VERSION 5.8 ;
BUSBITCHARS "[]" ;
DIVIDERCHAR "/" ;
UNITS
    DATABASE MICRONS 1000 ;
END UNITS

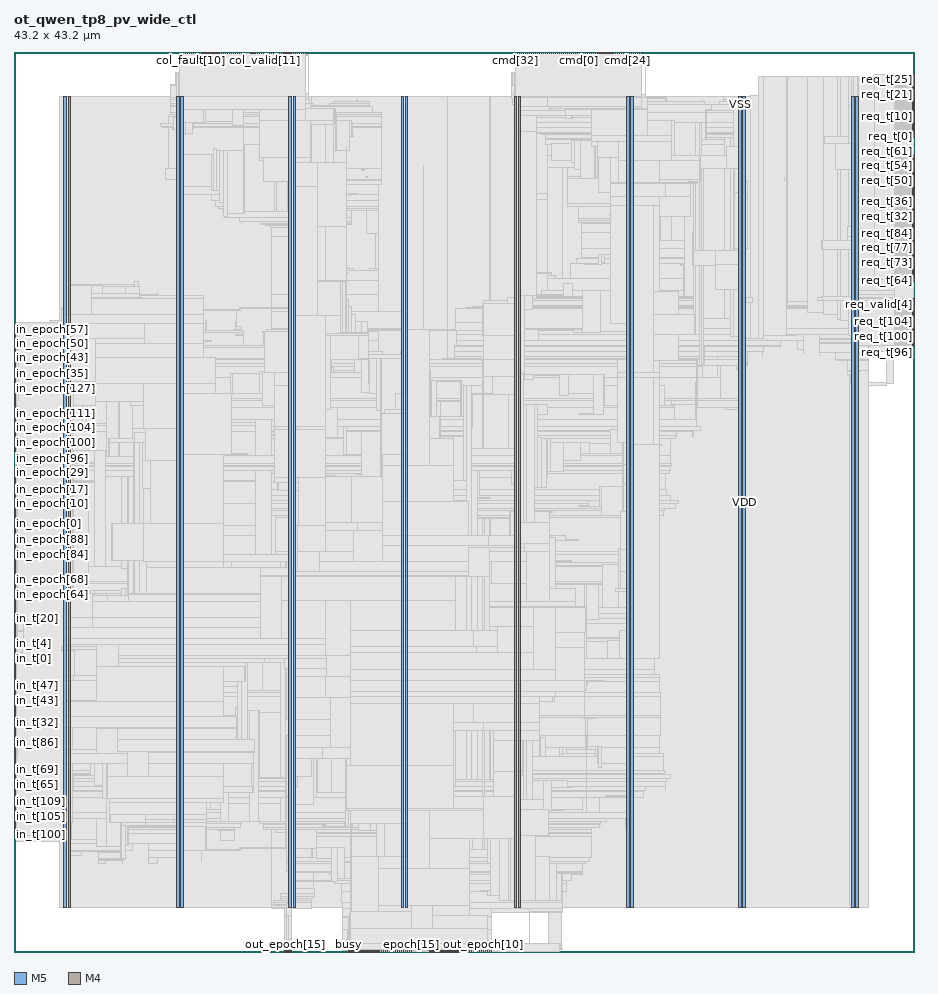
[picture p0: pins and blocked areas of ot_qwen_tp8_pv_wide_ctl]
MACRO ot_qwen_tp8_pv_wide_ctl
  FOREIGN ot_qwen_tp8_pv_wide_ctl 0 0 ;
  CLASS BLOCK ;
  SIZE 43.2 BY 43.2 ;
  PIN busy
    DIRECTION OUTPUT ;
    USE SIGNAL ;
    PORT
      LAYER M5 ;
        RECT  16.08 0 16.104 0.084 ;
    END
  END busy
  PIN clk
    DIRECTION INPUT ;
    USE SIGNAL ;
    PORT
      LAYER M5 ;
        RECT  16.176 0 16.2 0.084 ;
    END
  END clk
  PIN cmd[0]
    DIRECTION OUTPUT ;
    USE SIGNAL ;
    PORT
      LAYER M5 ;
        RECT  27.12 43.116 27.144 43.2 ;
    END
  END cmd[0]
  PIN cmd[10]
    DIRECTION OUTPUT ;
    USE SIGNAL ;
    PORT
      LAYER M5 ;
        RECT  28.08 43.116 28.104 43.2 ;
    END
  END cmd[10]
  PIN cmd[11]
    DIRECTION OUTPUT ;
    USE SIGNAL ;
    PORT
      LAYER M5 ;
        RECT  28.176 43.116 28.2 43.2 ;
    END
  END cmd[11]
  PIN cmd[12]
    DIRECTION OUTPUT ;
    USE SIGNAL ;
    PORT
      LAYER M5 ;
        RECT  28.272 43.116 28.296 43.2 ;
    END
  END cmd[12]
  PIN cmd[13]
    DIRECTION OUTPUT ;
    USE SIGNAL ;
    PORT
      LAYER M5 ;
        RECT  28.368 43.116 28.392 43.2 ;
    END
  END cmd[13]
  PIN cmd[14]
    DIRECTION OUTPUT ;
    USE SIGNAL ;
    PORT
      LAYER M5 ;
        RECT  28.464 43.116 28.488 43.2 ;
    END
  END cmd[14]
  PIN cmd[15]
    DIRECTION OUTPUT ;
    USE SIGNAL ;
    PORT
      LAYER M5 ;
        RECT  28.56 43.116 28.584 43.2 ;
    END
  END cmd[15]
  PIN cmd[16]
    DIRECTION OUTPUT ;
    USE SIGNAL ;
    PORT
      LAYER M5 ;
        RECT  28.656 43.116 28.68 43.2 ;
    END
  END cmd[16]
  PIN cmd[17]
    DIRECTION OUTPUT ;
    USE SIGNAL ;
    PORT
      LAYER M5 ;
        RECT  28.752 43.116 28.776 43.2 ;
    END
  END cmd[17]
  PIN cmd[18]
    DIRECTION OUTPUT ;
    USE SIGNAL ;
    PORT
      LAYER M5 ;
        RECT  28.848 43.116 28.872 43.2 ;
    END
  END cmd[18]
  PIN cmd[19]
    DIRECTION OUTPUT ;
    USE SIGNAL ;
    PORT
      LAYER M5 ;
        RECT  28.944 43.116 28.968 43.2 ;
    END
  END cmd[19]
  PIN cmd[1]
    DIRECTION OUTPUT ;
    USE SIGNAL ;
    PORT
      LAYER M5 ;
        RECT  27.216 43.116 27.24 43.2 ;
    END
  END cmd[1]
  PIN cmd[20]
    DIRECTION OUTPUT ;
    USE SIGNAL ;
    PORT
      LAYER M5 ;
        RECT  29.04 43.116 29.064 43.2 ;
    END
  END cmd[20]
  PIN cmd[21]
    DIRECTION OUTPUT ;
    USE SIGNAL ;
    PORT
      LAYER M5 ;
        RECT  29.136 43.116 29.16 43.2 ;
    END
  END cmd[21]
  PIN cmd[22]
    DIRECTION OUTPUT ;
    USE SIGNAL ;
    PORT
      LAYER M5 ;
        RECT  29.232 43.116 29.256 43.2 ;
    END
  END cmd[22]
  PIN cmd[23]
    DIRECTION OUTPUT ;
    USE SIGNAL ;
    PORT
      LAYER M5 ;
        RECT  29.328 43.116 29.352 43.2 ;
    END
  END cmd[23]
  PIN cmd[24]
    DIRECTION OUTPUT ;
    USE SIGNAL ;
    PORT
      LAYER M5 ;
        RECT  29.424 43.116 29.448 43.2 ;
    END
  END cmd[24]
  PIN cmd[25]
    DIRECTION OUTPUT ;
    USE SIGNAL ;
    PORT
      LAYER M5 ;
        RECT  29.52 43.116 29.544 43.2 ;
    END
  END cmd[25]
  PIN cmd[26]
    DIRECTION OUTPUT ;
    USE SIGNAL ;
    PORT
      LAYER M5 ;
        RECT  29.616 43.116 29.64 43.2 ;
    END
  END cmd[26]
  PIN cmd[27]
    DIRECTION OUTPUT ;
    USE SIGNAL ;
    PORT
      LAYER M5 ;
        RECT  29.712 43.116 29.736 43.2 ;
    END
  END cmd[27]
  PIN cmd[28]
    DIRECTION OUTPUT ;
    USE SIGNAL ;
    PORT
      LAYER M5 ;
        RECT  29.808 43.116 29.832 43.2 ;
    END
  END cmd[28]
  PIN cmd[29]
    DIRECTION OUTPUT ;
    USE SIGNAL ;
    PORT
      LAYER M5 ;
        RECT  29.904 43.116 29.928 43.2 ;
    END
  END cmd[29]
  PIN cmd[2]
    DIRECTION OUTPUT ;
    USE SIGNAL ;
    PORT
      LAYER M5 ;
        RECT  27.312 43.116 27.336 43.2 ;
    END
  END cmd[2]
  PIN cmd[30]
    DIRECTION OUTPUT ;
    USE SIGNAL ;
    PORT
      LAYER M5 ;
        RECT  30 43.116 30.024 43.2 ;
    END
  END cmd[30]
  PIN cmd[31]
    DIRECTION OUTPUT ;
    USE SIGNAL ;
    PORT
      LAYER M5 ;
        RECT  30.096 43.116 30.12 43.2 ;
    END
  END cmd[31]
  PIN cmd[32]
    DIRECTION OUTPUT ;
    USE SIGNAL ;
    PORT
      LAYER M5 ;
        RECT  24.048 43.116 24.072 43.2 ;
    END
  END cmd[32]
  PIN cmd[33]
    DIRECTION OUTPUT ;
    USE SIGNAL ;
    PORT
      LAYER M5 ;
        RECT  24.144 43.116 24.168 43.2 ;
    END
  END cmd[33]
  PIN cmd[34]
    DIRECTION OUTPUT ;
    USE SIGNAL ;
    PORT
      LAYER M5 ;
        RECT  24.24 43.116 24.264 43.2 ;
    END
  END cmd[34]
  PIN cmd[35]
    DIRECTION OUTPUT ;
    USE SIGNAL ;
    PORT
      LAYER M5 ;
        RECT  24.336 43.116 24.36 43.2 ;
    END
  END cmd[35]
  PIN cmd[36]
    DIRECTION OUTPUT ;
    USE SIGNAL ;
    PORT
      LAYER M5 ;
        RECT  24.432 43.116 24.456 43.2 ;
    END
  END cmd[36]
  PIN cmd[37]
    DIRECTION OUTPUT ;
    USE SIGNAL ;
    PORT
      LAYER M5 ;
        RECT  24.528 43.116 24.552 43.2 ;
    END
  END cmd[37]
  PIN cmd[38]
    DIRECTION OUTPUT ;
    USE SIGNAL ;
    PORT
      LAYER M5 ;
        RECT  24.624 43.116 24.648 43.2 ;
    END
  END cmd[38]
  PIN cmd[39]
    DIRECTION OUTPUT ;
    USE SIGNAL ;
    PORT
      LAYER M5 ;
        RECT  24.72 43.116 24.744 43.2 ;
    END
  END cmd[39]
  PIN cmd[3]
    DIRECTION OUTPUT ;
    USE SIGNAL ;
    PORT
      LAYER M5 ;
        RECT  27.408 43.116 27.432 43.2 ;
    END
  END cmd[3]
  PIN cmd[40]
    DIRECTION OUTPUT ;
    USE SIGNAL ;
    PORT
      LAYER M5 ;
        RECT  24.816 43.116 24.84 43.2 ;
    END
  END cmd[40]
  PIN cmd[41]
    DIRECTION OUTPUT ;
    USE SIGNAL ;
    PORT
      LAYER M5 ;
        RECT  24.912 43.116 24.936 43.2 ;
    END
  END cmd[41]
  PIN cmd[42]
    DIRECTION OUTPUT ;
    USE SIGNAL ;
    PORT
      LAYER M5 ;
        RECT  25.008 43.116 25.032 43.2 ;
    END
  END cmd[42]
  PIN cmd[43]
    DIRECTION OUTPUT ;
    USE SIGNAL ;
    PORT
      LAYER M5 ;
        RECT  25.104 43.116 25.128 43.2 ;
    END
  END cmd[43]
  PIN cmd[44]
    DIRECTION OUTPUT ;
    USE SIGNAL ;
    PORT
      LAYER M5 ;
        RECT  25.2 43.116 25.224 43.2 ;
    END
  END cmd[44]
  PIN cmd[45]
    DIRECTION OUTPUT ;
    USE SIGNAL ;
    PORT
      LAYER M5 ;
        RECT  25.296 43.116 25.32 43.2 ;
    END
  END cmd[45]
  PIN cmd[46]
    DIRECTION OUTPUT ;
    USE SIGNAL ;
    PORT
      LAYER M5 ;
        RECT  25.392 43.116 25.416 43.2 ;
    END
  END cmd[46]
  PIN cmd[47]
    DIRECTION OUTPUT ;
    USE SIGNAL ;
    PORT
      LAYER M5 ;
        RECT  25.488 43.116 25.512 43.2 ;
    END
  END cmd[47]
  PIN cmd[48]
    DIRECTION OUTPUT ;
    USE SIGNAL ;
    PORT
      LAYER M5 ;
        RECT  25.584 43.116 25.608 43.2 ;
    END
  END cmd[48]
  PIN cmd[49]
    DIRECTION OUTPUT ;
    USE SIGNAL ;
    PORT
      LAYER M5 ;
        RECT  25.68 43.116 25.704 43.2 ;
    END
  END cmd[49]
  PIN cmd[4]
    DIRECTION OUTPUT ;
    USE SIGNAL ;
    PORT
      LAYER M5 ;
        RECT  27.504 43.116 27.528 43.2 ;
    END
  END cmd[4]
  PIN cmd[50]
    DIRECTION OUTPUT ;
    USE SIGNAL ;
    PORT
      LAYER M5 ;
        RECT  25.776 43.116 25.8 43.2 ;
    END
  END cmd[50]
  PIN cmd[51]
    DIRECTION OUTPUT ;
    USE SIGNAL ;
    PORT
      LAYER M5 ;
        RECT  25.872 43.116 25.896 43.2 ;
    END
  END cmd[51]
  PIN cmd[52]
    DIRECTION OUTPUT ;
    USE SIGNAL ;
    PORT
      LAYER M5 ;
        RECT  25.968 43.116 25.992 43.2 ;
    END
  END cmd[52]
  PIN cmd[53]
    DIRECTION OUTPUT ;
    USE SIGNAL ;
    PORT
      LAYER M5 ;
        RECT  26.064 43.116 26.088 43.2 ;
    END
  END cmd[53]
  PIN cmd[54]
    DIRECTION OUTPUT ;
    USE SIGNAL ;
    PORT
      LAYER M5 ;
        RECT  26.16 43.116 26.184 43.2 ;
    END
  END cmd[54]
  PIN cmd[55]
    DIRECTION OUTPUT ;
    USE SIGNAL ;
    PORT
      LAYER M5 ;
        RECT  26.256 43.116 26.28 43.2 ;
    END
  END cmd[55]
  PIN cmd[56]
    DIRECTION OUTPUT ;
    USE SIGNAL ;
    PORT
      LAYER M5 ;
        RECT  26.352 43.116 26.376 43.2 ;
    END
  END cmd[56]
  PIN cmd[57]
    DIRECTION OUTPUT ;
    USE SIGNAL ;
    PORT
      LAYER M5 ;
        RECT  26.448 43.116 26.472 43.2 ;
    END
  END cmd[57]
  PIN cmd[58]
    DIRECTION OUTPUT ;
    USE SIGNAL ;
    PORT
      LAYER M5 ;
        RECT  26.544 43.116 26.568 43.2 ;
    END
  END cmd[58]
  PIN cmd[59]
    DIRECTION OUTPUT ;
    USE SIGNAL ;
    PORT
      LAYER M5 ;
        RECT  26.64 43.116 26.664 43.2 ;
    END
  END cmd[59]
  PIN cmd[5]
    DIRECTION OUTPUT ;
    USE SIGNAL ;
    PORT
      LAYER M5 ;
        RECT  27.6 43.116 27.624 43.2 ;
    END
  END cmd[5]
  PIN cmd[6]
    DIRECTION OUTPUT ;
    USE SIGNAL ;
    PORT
      LAYER M5 ;
        RECT  27.696 43.116 27.72 43.2 ;
    END
  END cmd[6]
  PIN cmd[7]
    DIRECTION OUTPUT ;
    USE SIGNAL ;
    PORT
      LAYER M5 ;
        RECT  27.792 43.116 27.816 43.2 ;
    END
  END cmd[7]
  PIN cmd[8]
    DIRECTION OUTPUT ;
    USE SIGNAL ;
    PORT
      LAYER M5 ;
        RECT  27.888 43.116 27.912 43.2 ;
    END
  END cmd[8]
  PIN cmd[9]
    DIRECTION OUTPUT ;
    USE SIGNAL ;
    PORT
      LAYER M5 ;
        RECT  27.984 43.116 28.008 43.2 ;
    END
  END cmd[9]
  PIN col_fault[0]
    DIRECTION INPUT ;
    USE SIGNAL ;
    PORT
      LAYER M5 ;
        RECT  26.736 43.116 26.76 43.2 ;
    END
  END col_fault[0]
  PIN col_fault[10]
    DIRECTION INPUT ;
    USE SIGNAL ;
    PORT
      LAYER M5 ;
        RECT  8.496 43.116 8.52 43.2 ;
    END
  END col_fault[10]
  PIN col_fault[11]
    DIRECTION INPUT ;
    USE SIGNAL ;
    PORT
      LAYER M5 ;
        RECT  8.592 43.116 8.616 43.2 ;
    END
  END col_fault[11]
  PIN col_fault[12]
    DIRECTION INPUT ;
    USE SIGNAL ;
    PORT
      LAYER M5 ;
        RECT  8.688 43.116 8.712 43.2 ;
    END
  END col_fault[12]
  PIN col_fault[13]
    DIRECTION INPUT ;
    USE SIGNAL ;
    PORT
      LAYER M5 ;
        RECT  8.784 43.116 8.808 43.2 ;
    END
  END col_fault[13]
  PIN col_fault[14]
    DIRECTION INPUT ;
    USE SIGNAL ;
    PORT
      LAYER M5 ;
        RECT  8.88 43.116 8.904 43.2 ;
    END
  END col_fault[14]
  PIN col_fault[15]
    DIRECTION INPUT ;
    USE SIGNAL ;
    PORT
      LAYER M5 ;
        RECT  8.976 43.116 9 43.2 ;
    END
  END col_fault[15]
  PIN col_fault[16]
    DIRECTION INPUT ;
    USE SIGNAL ;
    PORT
      LAYER M5 ;
        RECT  9.072 43.116 9.096 43.2 ;
    END
  END col_fault[16]
  PIN col_fault[17]
    DIRECTION INPUT ;
    USE SIGNAL ;
    PORT
      LAYER M5 ;
        RECT  9.168 43.116 9.192 43.2 ;
    END
  END col_fault[17]
  PIN col_fault[18]
    DIRECTION INPUT ;
    USE SIGNAL ;
    PORT
      LAYER M5 ;
        RECT  9.264 43.116 9.288 43.2 ;
    END
  END col_fault[18]
  PIN col_fault[19]
    DIRECTION INPUT ;
    USE SIGNAL ;
    PORT
      LAYER M5 ;
        RECT  9.36 43.116 9.384 43.2 ;
    END
  END col_fault[19]
  PIN col_fault[1]
    DIRECTION INPUT ;
    USE SIGNAL ;
    PORT
      LAYER M5 ;
        RECT  26.832 43.116 26.856 43.2 ;
    END
  END col_fault[1]
  PIN col_fault[20]
    DIRECTION INPUT ;
    USE SIGNAL ;
    PORT
      LAYER M5 ;
        RECT  9.456 43.116 9.48 43.2 ;
    END
  END col_fault[20]
  PIN col_fault[21]
    DIRECTION INPUT ;
    USE SIGNAL ;
    PORT
      LAYER M5 ;
        RECT  9.552 43.116 9.576 43.2 ;
    END
  END col_fault[21]
  PIN col_fault[22]
    DIRECTION INPUT ;
    USE SIGNAL ;
    PORT
      LAYER M5 ;
        RECT  9.648 43.116 9.672 43.2 ;
    END
  END col_fault[22]
  PIN col_fault[23]
    DIRECTION INPUT ;
    USE SIGNAL ;
    PORT
      LAYER M5 ;
        RECT  9.744 43.116 9.768 43.2 ;
    END
  END col_fault[23]
  PIN col_fault[24]
    DIRECTION INPUT ;
    USE SIGNAL ;
    PORT
      LAYER M5 ;
        RECT  9.84 43.116 9.864 43.2 ;
    END
  END col_fault[24]
  PIN col_fault[25]
    DIRECTION INPUT ;
    USE SIGNAL ;
    PORT
      LAYER M5 ;
        RECT  9.936 43.116 9.96 43.2 ;
    END
  END col_fault[25]
  PIN col_fault[26]
    DIRECTION INPUT ;
    USE SIGNAL ;
    PORT
      LAYER M5 ;
        RECT  10.032 43.116 10.056 43.2 ;
    END
  END col_fault[26]
  PIN col_fault[27]
    DIRECTION INPUT ;
    USE SIGNAL ;
    PORT
      LAYER M5 ;
        RECT  10.128 43.116 10.152 43.2 ;
    END
  END col_fault[27]
  PIN col_fault[28]
    DIRECTION INPUT ;
    USE SIGNAL ;
    PORT
      LAYER M5 ;
        RECT  10.224 43.116 10.248 43.2 ;
    END
  END col_fault[28]
  PIN col_fault[29]
    DIRECTION INPUT ;
    USE SIGNAL ;
    PORT
      LAYER M5 ;
        RECT  10.32 43.116 10.344 43.2 ;
    END
  END col_fault[29]
  PIN col_fault[2]
    DIRECTION INPUT ;
    USE SIGNAL ;
    PORT
      LAYER M5 ;
        RECT  26.928 43.116 26.952 43.2 ;
    END
  END col_fault[2]
  PIN col_fault[30]
    DIRECTION INPUT ;
    USE SIGNAL ;
    PORT
      LAYER M5 ;
        RECT  10.416 43.116 10.44 43.2 ;
    END
  END col_fault[30]
  PIN col_fault[31]
    DIRECTION INPUT ;
    USE SIGNAL ;
    PORT
      LAYER M5 ;
        RECT  10.512 43.116 10.536 43.2 ;
    END
  END col_fault[31]
  PIN col_fault[3]
    DIRECTION INPUT ;
    USE SIGNAL ;
    PORT
      LAYER M5 ;
        RECT  27.024 43.116 27.048 43.2 ;
    END
  END col_fault[3]
  PIN col_fault[4]
    DIRECTION INPUT ;
    USE SIGNAL ;
    PORT
      LAYER M5 ;
        RECT  7.92 43.116 7.944 43.2 ;
    END
  END col_fault[4]
  PIN col_fault[5]
    DIRECTION INPUT ;
    USE SIGNAL ;
    PORT
      LAYER M5 ;
        RECT  8.016 43.116 8.04 43.2 ;
    END
  END col_fault[5]
  PIN col_fault[6]
    DIRECTION INPUT ;
    USE SIGNAL ;
    PORT
      LAYER M5 ;
        RECT  8.112 43.116 8.136 43.2 ;
    END
  END col_fault[6]
  PIN col_fault[7]
    DIRECTION INPUT ;
    USE SIGNAL ;
    PORT
      LAYER M5 ;
        RECT  8.208 43.116 8.232 43.2 ;
    END
  END col_fault[7]
  PIN col_fault[8]
    DIRECTION INPUT ;
    USE SIGNAL ;
    PORT
      LAYER M5 ;
        RECT  8.304 43.116 8.328 43.2 ;
    END
  END col_fault[8]
  PIN col_fault[9]
    DIRECTION INPUT ;
    USE SIGNAL ;
    PORT
      LAYER M5 ;
        RECT  8.4 43.116 8.424 43.2 ;
    END
  END col_fault[9]
  PIN col_valid[0]
    DIRECTION INPUT ;
    USE SIGNAL ;
    PORT
      LAYER M5 ;
        RECT  10.608 43.116 10.632 43.2 ;
    END
  END col_valid[0]
  PIN col_valid[10]
    DIRECTION INPUT ;
    USE SIGNAL ;
    PORT
      LAYER M5 ;
        RECT  11.952 43.116 11.976 43.2 ;
    END
  END col_valid[10]
  PIN col_valid[11]
    DIRECTION INPUT ;
    USE SIGNAL ;
    PORT
      LAYER M5 ;
        RECT  12.048 43.116 12.072 43.2 ;
    END
  END col_valid[11]
  PIN col_valid[12]
    DIRECTION INPUT ;
    USE SIGNAL ;
    PORT
      LAYER M5 ;
        RECT  12.144 43.116 12.168 43.2 ;
    END
  END col_valid[12]
  PIN col_valid[13]
    DIRECTION INPUT ;
    USE SIGNAL ;
    PORT
      LAYER M5 ;
        RECT  12.24 43.116 12.264 43.2 ;
    END
  END col_valid[13]
  PIN col_valid[14]
    DIRECTION INPUT ;
    USE SIGNAL ;
    PORT
      LAYER M5 ;
        RECT  12.336 43.116 12.36 43.2 ;
    END
  END col_valid[14]
  PIN col_valid[15]
    DIRECTION INPUT ;
    USE SIGNAL ;
    PORT
      LAYER M5 ;
        RECT  12.432 43.116 12.456 43.2 ;
    END
  END col_valid[15]
  PIN col_valid[16]
    DIRECTION INPUT ;
    USE SIGNAL ;
    PORT
      LAYER M5 ;
        RECT  12.528 43.116 12.552 43.2 ;
    END
  END col_valid[16]
  PIN col_valid[17]
    DIRECTION INPUT ;
    USE SIGNAL ;
    PORT
      LAYER M5 ;
        RECT  12.624 43.116 12.648 43.2 ;
    END
  END col_valid[17]
  PIN col_valid[18]
    DIRECTION INPUT ;
    USE SIGNAL ;
    PORT
      LAYER M5 ;
        RECT  12.72 43.116 12.744 43.2 ;
    END
  END col_valid[18]
  PIN col_valid[19]
    DIRECTION INPUT ;
    USE SIGNAL ;
    PORT
      LAYER M5 ;
        RECT  12.816 43.116 12.84 43.2 ;
    END
  END col_valid[19]
  PIN col_valid[1]
    DIRECTION INPUT ;
    USE SIGNAL ;
    PORT
      LAYER M5 ;
        RECT  10.704 43.116 10.728 43.2 ;
    END
  END col_valid[1]
  PIN col_valid[20]
    DIRECTION INPUT ;
    USE SIGNAL ;
    PORT
      LAYER M5 ;
        RECT  12.912 43.116 12.936 43.2 ;
    END
  END col_valid[20]
  PIN col_valid[21]
    DIRECTION INPUT ;
    USE SIGNAL ;
    PORT
      LAYER M5 ;
        RECT  13.008 43.116 13.032 43.2 ;
    END
  END col_valid[21]
  PIN col_valid[22]
    DIRECTION INPUT ;
    USE SIGNAL ;
    PORT
      LAYER M5 ;
        RECT  13.104 43.116 13.128 43.2 ;
    END
  END col_valid[22]
  PIN col_valid[23]
    DIRECTION INPUT ;
    USE SIGNAL ;
    PORT
      LAYER M5 ;
        RECT  13.2 43.116 13.224 43.2 ;
    END
  END col_valid[23]
  PIN col_valid[24]
    DIRECTION INPUT ;
    USE SIGNAL ;
    PORT
      LAYER M5 ;
        RECT  13.296 43.116 13.32 43.2 ;
    END
  END col_valid[24]
  PIN col_valid[25]
    DIRECTION INPUT ;
    USE SIGNAL ;
    PORT
      LAYER M5 ;
        RECT  13.392 43.116 13.416 43.2 ;
    END
  END col_valid[25]
  PIN col_valid[26]
    DIRECTION INPUT ;
    USE SIGNAL ;
    PORT
      LAYER M5 ;
        RECT  13.488 43.116 13.512 43.2 ;
    END
  END col_valid[26]
  PIN col_valid[27]
    DIRECTION INPUT ;
    USE SIGNAL ;
    PORT
      LAYER M5 ;
        RECT  13.584 43.116 13.608 43.2 ;
    END
  END col_valid[27]
  PIN col_valid[28]
    DIRECTION INPUT ;
    USE SIGNAL ;
    PORT
      LAYER M5 ;
        RECT  13.68 43.116 13.704 43.2 ;
    END
  END col_valid[28]
  PIN col_valid[29]
    DIRECTION INPUT ;
    USE SIGNAL ;
    PORT
      LAYER M5 ;
        RECT  13.776 43.116 13.8 43.2 ;
    END
  END col_valid[29]
  PIN col_valid[2]
    DIRECTION INPUT ;
    USE SIGNAL ;
    PORT
      LAYER M5 ;
        RECT  10.8 43.116 10.824 43.2 ;
    END
  END col_valid[2]
  PIN col_valid[30]
    DIRECTION INPUT ;
    USE SIGNAL ;
    PORT
      LAYER M5 ;
        RECT  13.872 43.116 13.896 43.2 ;
    END
  END col_valid[30]
  PIN col_valid[31]
    DIRECTION INPUT ;
    USE SIGNAL ;
    PORT
      LAYER M5 ;
        RECT  13.968 43.116 13.992 43.2 ;
    END
  END col_valid[31]
  PIN col_valid[3]
    DIRECTION INPUT ;
    USE SIGNAL ;
    PORT
      LAYER M5 ;
        RECT  10.896 43.116 10.92 43.2 ;
    END
  END col_valid[3]
  PIN col_valid[4]
    DIRECTION INPUT ;
    USE SIGNAL ;
    PORT
      LAYER M5 ;
        RECT  11.376 43.116 11.4 43.2 ;
    END
  END col_valid[4]
  PIN col_valid[5]
    DIRECTION INPUT ;
    USE SIGNAL ;
    PORT
      LAYER M5 ;
        RECT  11.472 43.116 11.496 43.2 ;
    END
  END col_valid[5]
  PIN col_valid[6]
    DIRECTION INPUT ;
    USE SIGNAL ;
    PORT
      LAYER M5 ;
        RECT  11.568 43.116 11.592 43.2 ;
    END
  END col_valid[6]
  PIN col_valid[7]
    DIRECTION INPUT ;
    USE SIGNAL ;
    PORT
      LAYER M5 ;
        RECT  11.664 43.116 11.688 43.2 ;
    END
  END col_valid[7]
  PIN col_valid[8]
    DIRECTION INPUT ;
    USE SIGNAL ;
    PORT
      LAYER M5 ;
        RECT  11.76 43.116 11.784 43.2 ;
    END
  END col_valid[8]
  PIN col_valid[9]
    DIRECTION INPUT ;
    USE SIGNAL ;
    PORT
      LAYER M5 ;
        RECT  11.856 43.116 11.88 43.2 ;
    END
  END col_valid[9]
  PIN context_len[0]
    DIRECTION INPUT ;
    USE SIGNAL ;
    PORT
      LAYER M5 ;
        RECT  16.272 0 16.296 0.084 ;
    END
  END context_len[0]
  PIN context_len[10]
    DIRECTION INPUT ;
    USE SIGNAL ;
    PORT
      LAYER M5 ;
        RECT  17.232 0 17.256 0.084 ;
    END
  END context_len[10]
  PIN context_len[11]
    DIRECTION INPUT ;
    USE SIGNAL ;
    PORT
      LAYER M5 ;
        RECT  17.328 0 17.352 0.084 ;
    END
  END context_len[11]
  PIN context_len[12]
    DIRECTION INPUT ;
    USE SIGNAL ;
    PORT
      LAYER M5 ;
        RECT  17.424 0 17.448 0.084 ;
    END
  END context_len[12]
  PIN context_len[13]
    DIRECTION INPUT ;
    USE SIGNAL ;
    PORT
      LAYER M5 ;
        RECT  17.52 0 17.544 0.084 ;
    END
  END context_len[13]
  PIN context_len[1]
    DIRECTION INPUT ;
    USE SIGNAL ;
    PORT
      LAYER M5 ;
        RECT  16.368 0 16.392 0.084 ;
    END
  END context_len[1]
  PIN context_len[2]
    DIRECTION INPUT ;
    USE SIGNAL ;
    PORT
      LAYER M5 ;
        RECT  16.464 0 16.488 0.084 ;
    END
  END context_len[2]
  PIN context_len[3]
    DIRECTION INPUT ;
    USE SIGNAL ;
    PORT
      LAYER M5 ;
        RECT  16.56 0 16.584 0.084 ;
    END
  END context_len[3]
  PIN context_len[4]
    DIRECTION INPUT ;
    USE SIGNAL ;
    PORT
      LAYER M5 ;
        RECT  16.656 0 16.68 0.084 ;
    END
  END context_len[4]
  PIN context_len[5]
    DIRECTION INPUT ;
    USE SIGNAL ;
    PORT
      LAYER M5 ;
        RECT  16.752 0 16.776 0.084 ;
    END
  END context_len[5]
  PIN context_len[6]
    DIRECTION INPUT ;
    USE SIGNAL ;
    PORT
      LAYER M5 ;
        RECT  16.848 0 16.872 0.084 ;
    END
  END context_len[6]
  PIN context_len[7]
    DIRECTION INPUT ;
    USE SIGNAL ;
    PORT
      LAYER M5 ;
        RECT  16.944 0 16.968 0.084 ;
    END
  END context_len[7]
  PIN context_len[8]
    DIRECTION INPUT ;
    USE SIGNAL ;
    PORT
      LAYER M5 ;
        RECT  17.04 0 17.064 0.084 ;
    END
  END context_len[8]
  PIN context_len[9]
    DIRECTION INPUT ;
    USE SIGNAL ;
    PORT
      LAYER M5 ;
        RECT  17.136 0 17.16 0.084 ;
    END
  END context_len[9]
  PIN epoch[0]
    DIRECTION INPUT ;
    USE SIGNAL ;
    PORT
      LAYER M5 ;
        RECT  17.616 0 17.64 0.084 ;
    END
  END epoch[0]
  PIN epoch[10]
    DIRECTION INPUT ;
    USE SIGNAL ;
    PORT
      LAYER M5 ;
        RECT  18.576 0 18.6 0.084 ;
    END
  END epoch[10]
  PIN epoch[11]
    DIRECTION INPUT ;
    USE SIGNAL ;
    PORT
      LAYER M5 ;
        RECT  18.672 0 18.696 0.084 ;
    END
  END epoch[11]
  PIN epoch[12]
    DIRECTION INPUT ;
    USE SIGNAL ;
    PORT
      LAYER M5 ;
        RECT  18.768 0 18.792 0.084 ;
    END
  END epoch[12]
  PIN epoch[13]
    DIRECTION INPUT ;
    USE SIGNAL ;
    PORT
      LAYER M5 ;
        RECT  18.864 0 18.888 0.084 ;
    END
  END epoch[13]
  PIN epoch[14]
    DIRECTION INPUT ;
    USE SIGNAL ;
    PORT
      LAYER M5 ;
        RECT  18.96 0 18.984 0.084 ;
    END
  END epoch[14]
  PIN epoch[15]
    DIRECTION INPUT ;
    USE SIGNAL ;
    PORT
      LAYER M5 ;
        RECT  19.056 0 19.08 0.084 ;
    END
  END epoch[15]
  PIN epoch[1]
    DIRECTION INPUT ;
    USE SIGNAL ;
    PORT
      LAYER M5 ;
        RECT  17.712 0 17.736 0.084 ;
    END
  END epoch[1]
  PIN epoch[2]
    DIRECTION INPUT ;
    USE SIGNAL ;
    PORT
      LAYER M5 ;
        RECT  17.808 0 17.832 0.084 ;
    END
  END epoch[2]
  PIN epoch[3]
    DIRECTION INPUT ;
    USE SIGNAL ;
    PORT
      LAYER M5 ;
        RECT  17.904 0 17.928 0.084 ;
    END
  END epoch[3]
  PIN epoch[4]
    DIRECTION INPUT ;
    USE SIGNAL ;
    PORT
      LAYER M5 ;
        RECT  18 0 18.024 0.084 ;
    END
  END epoch[4]
  PIN epoch[5]
    DIRECTION INPUT ;
    USE SIGNAL ;
    PORT
      LAYER M5 ;
        RECT  18.096 0 18.12 0.084 ;
    END
  END epoch[5]
  PIN epoch[6]
    DIRECTION INPUT ;
    USE SIGNAL ;
    PORT
      LAYER M5 ;
        RECT  18.192 0 18.216 0.084 ;
    END
  END epoch[6]
  PIN epoch[7]
    DIRECTION INPUT ;
    USE SIGNAL ;
    PORT
      LAYER M5 ;
        RECT  18.288 0 18.312 0.084 ;
    END
  END epoch[7]
  PIN epoch[8]
    DIRECTION INPUT ;
    USE SIGNAL ;
    PORT
      LAYER M5 ;
        RECT  18.384 0 18.408 0.084 ;
    END
  END epoch[8]
  PIN epoch[9]
    DIRECTION INPUT ;
    USE SIGNAL ;
    PORT
      LAYER M5 ;
        RECT  18.48 0 18.504 0.084 ;
    END
  END epoch[9]
  PIN fault
    DIRECTION OUTPUT ;
    USE SIGNAL ;
    PORT
      LAYER M5 ;
        RECT  19.92 0 19.944 0.084 ;
    END
  END fault
  PIN in_epoch[0]
    DIRECTION INPUT ;
    USE SIGNAL ;
    PORT
      LAYER M4 ;
        RECT  0 20.208 0.084 20.232 ;
    END
  END in_epoch[0]
  PIN in_epoch[100]
    DIRECTION INPUT ;
    USE SIGNAL ;
    PORT
      LAYER M4 ;
        RECT  0 24.432 0.084 24.456 ;
    END
  END in_epoch[100]
  PIN in_epoch[101]
    DIRECTION INPUT ;
    USE SIGNAL ;
    PORT
      LAYER M4 ;
        RECT  0 24.528 0.084 24.552 ;
    END
  END in_epoch[101]
  PIN in_epoch[102]
    DIRECTION INPUT ;
    USE SIGNAL ;
    PORT
      LAYER M4 ;
        RECT  0 24.624 0.084 24.648 ;
    END
  END in_epoch[102]
  PIN in_epoch[103]
    DIRECTION INPUT ;
    USE SIGNAL ;
    PORT
      LAYER M4 ;
        RECT  0 24.72 0.084 24.744 ;
    END
  END in_epoch[103]
  PIN in_epoch[104]
    DIRECTION INPUT ;
    USE SIGNAL ;
    PORT
      LAYER M4 ;
        RECT  0 24.816 0.084 24.84 ;
    END
  END in_epoch[104]
  PIN in_epoch[105]
    DIRECTION INPUT ;
    USE SIGNAL ;
    PORT
      LAYER M4 ;
        RECT  0 24.912 0.084 24.936 ;
    END
  END in_epoch[105]
  PIN in_epoch[106]
    DIRECTION INPUT ;
    USE SIGNAL ;
    PORT
      LAYER M4 ;
        RECT  0 25.008 0.084 25.032 ;
    END
  END in_epoch[106]
  PIN in_epoch[107]
    DIRECTION INPUT ;
    USE SIGNAL ;
    PORT
      LAYER M4 ;
        RECT  0 25.104 0.084 25.128 ;
    END
  END in_epoch[107]
  PIN in_epoch[108]
    DIRECTION INPUT ;
    USE SIGNAL ;
    PORT
      LAYER M4 ;
        RECT  0 25.2 0.084 25.224 ;
    END
  END in_epoch[108]
  PIN in_epoch[109]
    DIRECTION INPUT ;
    USE SIGNAL ;
    PORT
      LAYER M4 ;
        RECT  0 25.296 0.084 25.32 ;
    END
  END in_epoch[109]
  PIN in_epoch[10]
    DIRECTION INPUT ;
    USE SIGNAL ;
    PORT
      LAYER M4 ;
        RECT  0 21.168 0.084 21.192 ;
    END
  END in_epoch[10]
  PIN in_epoch[110]
    DIRECTION INPUT ;
    USE SIGNAL ;
    PORT
      LAYER M4 ;
        RECT  0 25.392 0.084 25.416 ;
    END
  END in_epoch[110]
  PIN in_epoch[111]
    DIRECTION INPUT ;
    USE SIGNAL ;
    PORT
      LAYER M4 ;
        RECT  0 25.488 0.084 25.512 ;
    END
  END in_epoch[111]
  PIN in_epoch[112]
    DIRECTION INPUT ;
    USE SIGNAL ;
    PORT
      LAYER M4 ;
        RECT  0 25.584 0.084 25.608 ;
    END
  END in_epoch[112]
  PIN in_epoch[113]
    DIRECTION INPUT ;
    USE SIGNAL ;
    PORT
      LAYER M4 ;
        RECT  0 25.68 0.084 25.704 ;
    END
  END in_epoch[113]
  PIN in_epoch[114]
    DIRECTION INPUT ;
    USE SIGNAL ;
    PORT
      LAYER M4 ;
        RECT  0 25.776 0.084 25.8 ;
    END
  END in_epoch[114]
  PIN in_epoch[115]
    DIRECTION INPUT ;
    USE SIGNAL ;
    PORT
      LAYER M4 ;
        RECT  0 25.872 0.084 25.896 ;
    END
  END in_epoch[115]
  PIN in_epoch[116]
    DIRECTION INPUT ;
    USE SIGNAL ;
    PORT
      LAYER M4 ;
        RECT  0 25.968 0.084 25.992 ;
    END
  END in_epoch[116]
  PIN in_epoch[117]
    DIRECTION INPUT ;
    USE SIGNAL ;
    PORT
      LAYER M4 ;
        RECT  0 26.064 0.084 26.088 ;
    END
  END in_epoch[117]
  PIN in_epoch[118]
    DIRECTION INPUT ;
    USE SIGNAL ;
    PORT
      LAYER M4 ;
        RECT  0 26.16 0.084 26.184 ;
    END
  END in_epoch[118]
  PIN in_epoch[119]
    DIRECTION INPUT ;
    USE SIGNAL ;
    PORT
      LAYER M4 ;
        RECT  0 26.256 0.084 26.28 ;
    END
  END in_epoch[119]
  PIN in_epoch[11]
    DIRECTION INPUT ;
    USE SIGNAL ;
    PORT
      LAYER M4 ;
        RECT  0 21.264 0.084 21.288 ;
    END
  END in_epoch[11]
  PIN in_epoch[120]
    DIRECTION INPUT ;
    USE SIGNAL ;
    PORT
      LAYER M4 ;
        RECT  0 26.352 0.084 26.376 ;
    END
  END in_epoch[120]
  PIN in_epoch[121]
    DIRECTION INPUT ;
    USE SIGNAL ;
    PORT
      LAYER M4 ;
        RECT  0 26.448 0.084 26.472 ;
    END
  END in_epoch[121]
  PIN in_epoch[122]
    DIRECTION INPUT ;
    USE SIGNAL ;
    PORT
      LAYER M4 ;
        RECT  0 26.544 0.084 26.568 ;
    END
  END in_epoch[122]
  PIN in_epoch[123]
    DIRECTION INPUT ;
    USE SIGNAL ;
    PORT
      LAYER M4 ;
        RECT  0 26.64 0.084 26.664 ;
    END
  END in_epoch[123]
  PIN in_epoch[124]
    DIRECTION INPUT ;
    USE SIGNAL ;
    PORT
      LAYER M4 ;
        RECT  0 26.736 0.084 26.76 ;
    END
  END in_epoch[124]
  PIN in_epoch[125]
    DIRECTION INPUT ;
    USE SIGNAL ;
    PORT
      LAYER M4 ;
        RECT  0 26.832 0.084 26.856 ;
    END
  END in_epoch[125]
  PIN in_epoch[126]
    DIRECTION INPUT ;
    USE SIGNAL ;
    PORT
      LAYER M4 ;
        RECT  0 26.928 0.084 26.952 ;
    END
  END in_epoch[126]
  PIN in_epoch[127]
    DIRECTION INPUT ;
    USE SIGNAL ;
    PORT
      LAYER M4 ;
        RECT  0 27.024 0.084 27.048 ;
    END
  END in_epoch[127]
  PIN in_epoch[12]
    DIRECTION INPUT ;
    USE SIGNAL ;
    PORT
      LAYER M4 ;
        RECT  0 21.36 0.084 21.384 ;
    END
  END in_epoch[12]
  PIN in_epoch[13]
    DIRECTION INPUT ;
    USE SIGNAL ;
    PORT
      LAYER M4 ;
        RECT  0 21.456 0.084 21.48 ;
    END
  END in_epoch[13]
  PIN in_epoch[14]
    DIRECTION INPUT ;
    USE SIGNAL ;
    PORT
      LAYER M4 ;
        RECT  0 21.552 0.084 21.576 ;
    END
  END in_epoch[14]
  PIN in_epoch[15]
    DIRECTION INPUT ;
    USE SIGNAL ;
    PORT
      LAYER M4 ;
        RECT  0 21.648 0.084 21.672 ;
    END
  END in_epoch[15]
  PIN in_epoch[16]
    DIRECTION INPUT ;
    USE SIGNAL ;
    PORT
      LAYER M4 ;
        RECT  0 21.744 0.084 21.768 ;
    END
  END in_epoch[16]
  PIN in_epoch[17]
    DIRECTION INPUT ;
    USE SIGNAL ;
    PORT
      LAYER M4 ;
        RECT  0 21.84 0.084 21.864 ;
    END
  END in_epoch[17]
  PIN in_epoch[18]
    DIRECTION INPUT ;
    USE SIGNAL ;
    PORT
      LAYER M4 ;
        RECT  0 21.936 0.084 21.96 ;
    END
  END in_epoch[18]
  PIN in_epoch[19]
    DIRECTION INPUT ;
    USE SIGNAL ;
    PORT
      LAYER M4 ;
        RECT  0 22.032 0.084 22.056 ;
    END
  END in_epoch[19]
  PIN in_epoch[1]
    DIRECTION INPUT ;
    USE SIGNAL ;
    PORT
      LAYER M4 ;
        RECT  0 20.304 0.084 20.328 ;
    END
  END in_epoch[1]
  PIN in_epoch[20]
    DIRECTION INPUT ;
    USE SIGNAL ;
    PORT
      LAYER M4 ;
        RECT  0 22.128 0.084 22.152 ;
    END
  END in_epoch[20]
  PIN in_epoch[21]
    DIRECTION INPUT ;
    USE SIGNAL ;
    PORT
      LAYER M4 ;
        RECT  0 22.224 0.084 22.248 ;
    END
  END in_epoch[21]
  PIN in_epoch[22]
    DIRECTION INPUT ;
    USE SIGNAL ;
    PORT
      LAYER M4 ;
        RECT  0 22.32 0.084 22.344 ;
    END
  END in_epoch[22]
  PIN in_epoch[23]
    DIRECTION INPUT ;
    USE SIGNAL ;
    PORT
      LAYER M4 ;
        RECT  0 22.416 0.084 22.44 ;
    END
  END in_epoch[23]
  PIN in_epoch[24]
    DIRECTION INPUT ;
    USE SIGNAL ;
    PORT
      LAYER M4 ;
        RECT  0 22.512 0.084 22.536 ;
    END
  END in_epoch[24]
  PIN in_epoch[25]
    DIRECTION INPUT ;
    USE SIGNAL ;
    PORT
      LAYER M4 ;
        RECT  0 22.608 0.084 22.632 ;
    END
  END in_epoch[25]
  PIN in_epoch[26]
    DIRECTION INPUT ;
    USE SIGNAL ;
    PORT
      LAYER M4 ;
        RECT  0 22.704 0.084 22.728 ;
    END
  END in_epoch[26]
  PIN in_epoch[27]
    DIRECTION INPUT ;
    USE SIGNAL ;
    PORT
      LAYER M4 ;
        RECT  0 22.8 0.084 22.824 ;
    END
  END in_epoch[27]
  PIN in_epoch[28]
    DIRECTION INPUT ;
    USE SIGNAL ;
    PORT
      LAYER M4 ;
        RECT  0 22.896 0.084 22.92 ;
    END
  END in_epoch[28]
  PIN in_epoch[29]
    DIRECTION INPUT ;
    USE SIGNAL ;
    PORT
      LAYER M4 ;
        RECT  0 22.992 0.084 23.016 ;
    END
  END in_epoch[29]
  PIN in_epoch[2]
    DIRECTION INPUT ;
    USE SIGNAL ;
    PORT
      LAYER M4 ;
        RECT  0 20.4 0.084 20.424 ;
    END
  END in_epoch[2]
  PIN in_epoch[30]
    DIRECTION INPUT ;
    USE SIGNAL ;
    PORT
      LAYER M4 ;
        RECT  0 23.088 0.084 23.112 ;
    END
  END in_epoch[30]
  PIN in_epoch[31]
    DIRECTION INPUT ;
    USE SIGNAL ;
    PORT
      LAYER M4 ;
        RECT  0 23.184 0.084 23.208 ;
    END
  END in_epoch[31]
  PIN in_epoch[32]
    DIRECTION INPUT ;
    USE SIGNAL ;
    PORT
      LAYER M4 ;
        RECT  0 27.12 0.084 27.144 ;
    END
  END in_epoch[32]
  PIN in_epoch[33]
    DIRECTION INPUT ;
    USE SIGNAL ;
    PORT
      LAYER M4 ;
        RECT  0 27.216 0.084 27.24 ;
    END
  END in_epoch[33]
  PIN in_epoch[34]
    DIRECTION INPUT ;
    USE SIGNAL ;
    PORT
      LAYER M4 ;
        RECT  0 27.312 0.084 27.336 ;
    END
  END in_epoch[34]
  PIN in_epoch[35]
    DIRECTION INPUT ;
    USE SIGNAL ;
    PORT
      LAYER M4 ;
        RECT  0 27.408 0.084 27.432 ;
    END
  END in_epoch[35]
  PIN in_epoch[36]
    DIRECTION INPUT ;
    USE SIGNAL ;
    PORT
      LAYER M4 ;
        RECT  0 27.504 0.084 27.528 ;
    END
  END in_epoch[36]
  PIN in_epoch[37]
    DIRECTION INPUT ;
    USE SIGNAL ;
    PORT
      LAYER M4 ;
        RECT  0 27.6 0.084 27.624 ;
    END
  END in_epoch[37]
  PIN in_epoch[38]
    DIRECTION INPUT ;
    USE SIGNAL ;
    PORT
      LAYER M4 ;
        RECT  0 27.696 0.084 27.72 ;
    END
  END in_epoch[38]
  PIN in_epoch[39]
    DIRECTION INPUT ;
    USE SIGNAL ;
    PORT
      LAYER M4 ;
        RECT  0 27.792 0.084 27.816 ;
    END
  END in_epoch[39]
  PIN in_epoch[3]
    DIRECTION INPUT ;
    USE SIGNAL ;
    PORT
      LAYER M4 ;
        RECT  0 20.496 0.084 20.52 ;
    END
  END in_epoch[3]
  PIN in_epoch[40]
    DIRECTION INPUT ;
    USE SIGNAL ;
    PORT
      LAYER M4 ;
        RECT  0 27.888 0.084 27.912 ;
    END
  END in_epoch[40]
  PIN in_epoch[41]
    DIRECTION INPUT ;
    USE SIGNAL ;
    PORT
      LAYER M4 ;
        RECT  0 27.984 0.084 28.008 ;
    END
  END in_epoch[41]
  PIN in_epoch[42]
    DIRECTION INPUT ;
    USE SIGNAL ;
    PORT
      LAYER M4 ;
        RECT  0 28.08 0.084 28.104 ;
    END
  END in_epoch[42]
  PIN in_epoch[43]
    DIRECTION INPUT ;
    USE SIGNAL ;
    PORT
      LAYER M4 ;
        RECT  0 28.176 0.084 28.2 ;
    END
  END in_epoch[43]
  PIN in_epoch[44]
    DIRECTION INPUT ;
    USE SIGNAL ;
    PORT
      LAYER M4 ;
        RECT  0 28.272 0.084 28.296 ;
    END
  END in_epoch[44]
  PIN in_epoch[45]
    DIRECTION INPUT ;
    USE SIGNAL ;
    PORT
      LAYER M4 ;
        RECT  0 28.368 0.084 28.392 ;
    END
  END in_epoch[45]
  PIN in_epoch[46]
    DIRECTION INPUT ;
    USE SIGNAL ;
    PORT
      LAYER M4 ;
        RECT  0 28.464 0.084 28.488 ;
    END
  END in_epoch[46]
  PIN in_epoch[47]
    DIRECTION INPUT ;
    USE SIGNAL ;
    PORT
      LAYER M4 ;
        RECT  0 28.56 0.084 28.584 ;
    END
  END in_epoch[47]
  PIN in_epoch[48]
    DIRECTION INPUT ;
    USE SIGNAL ;
    PORT
      LAYER M4 ;
        RECT  0 28.656 0.084 28.68 ;
    END
  END in_epoch[48]
  PIN in_epoch[49]
    DIRECTION INPUT ;
    USE SIGNAL ;
    PORT
      LAYER M4 ;
        RECT  0 28.752 0.084 28.776 ;
    END
  END in_epoch[49]
  PIN in_epoch[4]
    DIRECTION INPUT ;
    USE SIGNAL ;
    PORT
      LAYER M4 ;
        RECT  0 20.592 0.084 20.616 ;
    END
  END in_epoch[4]
  PIN in_epoch[50]
    DIRECTION INPUT ;
    USE SIGNAL ;
    PORT
      LAYER M4 ;
        RECT  0 28.848 0.084 28.872 ;
    END
  END in_epoch[50]
  PIN in_epoch[51]
    DIRECTION INPUT ;
    USE SIGNAL ;
    PORT
      LAYER M4 ;
        RECT  0 28.944 0.084 28.968 ;
    END
  END in_epoch[51]
  PIN in_epoch[52]
    DIRECTION INPUT ;
    USE SIGNAL ;
    PORT
      LAYER M4 ;
        RECT  0 29.04 0.084 29.064 ;
    END
  END in_epoch[52]
  PIN in_epoch[53]
    DIRECTION INPUT ;
    USE SIGNAL ;
    PORT
      LAYER M4 ;
        RECT  0 29.136 0.084 29.16 ;
    END
  END in_epoch[53]
  PIN in_epoch[54]
    DIRECTION INPUT ;
    USE SIGNAL ;
    PORT
      LAYER M4 ;
        RECT  0 29.232 0.084 29.256 ;
    END
  END in_epoch[54]
  PIN in_epoch[55]
    DIRECTION INPUT ;
    USE SIGNAL ;
    PORT
      LAYER M4 ;
        RECT  0 29.328 0.084 29.352 ;
    END
  END in_epoch[55]
  PIN in_epoch[56]
    DIRECTION INPUT ;
    USE SIGNAL ;
    PORT
      LAYER M4 ;
        RECT  0 29.424 0.084 29.448 ;
    END
  END in_epoch[56]
  PIN in_epoch[57]
    DIRECTION INPUT ;
    USE SIGNAL ;
    PORT
      LAYER M4 ;
        RECT  0 29.52 0.084 29.544 ;
    END
  END in_epoch[57]
  PIN in_epoch[58]
    DIRECTION INPUT ;
    USE SIGNAL ;
    PORT
      LAYER M4 ;
        RECT  0 29.616 0.084 29.64 ;
    END
  END in_epoch[58]
  PIN in_epoch[59]
    DIRECTION INPUT ;
    USE SIGNAL ;
    PORT
      LAYER M4 ;
        RECT  0 29.712 0.084 29.736 ;
    END
  END in_epoch[59]
  PIN in_epoch[5]
    DIRECTION INPUT ;
    USE SIGNAL ;
    PORT
      LAYER M4 ;
        RECT  0 20.688 0.084 20.712 ;
    END
  END in_epoch[5]
  PIN in_epoch[60]
    DIRECTION INPUT ;
    USE SIGNAL ;
    PORT
      LAYER M4 ;
        RECT  0 29.808 0.084 29.832 ;
    END
  END in_epoch[60]
  PIN in_epoch[61]
    DIRECTION INPUT ;
    USE SIGNAL ;
    PORT
      LAYER M4 ;
        RECT  0 29.904 0.084 29.928 ;
    END
  END in_epoch[61]
  PIN in_epoch[62]
    DIRECTION INPUT ;
    USE SIGNAL ;
    PORT
      LAYER M4 ;
        RECT  0 30 0.084 30.024 ;
    END
  END in_epoch[62]
  PIN in_epoch[63]
    DIRECTION INPUT ;
    USE SIGNAL ;
    PORT
      LAYER M4 ;
        RECT  0 30.096 0.084 30.12 ;
    END
  END in_epoch[63]
  PIN in_epoch[64]
    DIRECTION INPUT ;
    USE SIGNAL ;
    PORT
      LAYER M4 ;
        RECT  0 17.136 0.084 17.16 ;
    END
  END in_epoch[64]
  PIN in_epoch[65]
    DIRECTION INPUT ;
    USE SIGNAL ;
    PORT
      LAYER M4 ;
        RECT  0 17.232 0.084 17.256 ;
    END
  END in_epoch[65]
  PIN in_epoch[66]
    DIRECTION INPUT ;
    USE SIGNAL ;
    PORT
      LAYER M4 ;
        RECT  0 17.328 0.084 17.352 ;
    END
  END in_epoch[66]
  PIN in_epoch[67]
    DIRECTION INPUT ;
    USE SIGNAL ;
    PORT
      LAYER M4 ;
        RECT  0 17.424 0.084 17.448 ;
    END
  END in_epoch[67]
  PIN in_epoch[68]
    DIRECTION INPUT ;
    USE SIGNAL ;
    PORT
      LAYER M4 ;
        RECT  0 17.52 0.084 17.544 ;
    END
  END in_epoch[68]
  PIN in_epoch[69]
    DIRECTION INPUT ;
    USE SIGNAL ;
    PORT
      LAYER M4 ;
        RECT  0 17.616 0.084 17.64 ;
    END
  END in_epoch[69]
  PIN in_epoch[6]
    DIRECTION INPUT ;
    USE SIGNAL ;
    PORT
      LAYER M4 ;
        RECT  0 20.784 0.084 20.808 ;
    END
  END in_epoch[6]
  PIN in_epoch[70]
    DIRECTION INPUT ;
    USE SIGNAL ;
    PORT
      LAYER M4 ;
        RECT  0 17.712 0.084 17.736 ;
    END
  END in_epoch[70]
  PIN in_epoch[71]
    DIRECTION INPUT ;
    USE SIGNAL ;
    PORT
      LAYER M4 ;
        RECT  0 17.808 0.084 17.832 ;
    END
  END in_epoch[71]
  PIN in_epoch[72]
    DIRECTION INPUT ;
    USE SIGNAL ;
    PORT
      LAYER M4 ;
        RECT  0 17.904 0.084 17.928 ;
    END
  END in_epoch[72]
  PIN in_epoch[73]
    DIRECTION INPUT ;
    USE SIGNAL ;
    PORT
      LAYER M4 ;
        RECT  0 18 0.084 18.024 ;
    END
  END in_epoch[73]
  PIN in_epoch[74]
    DIRECTION INPUT ;
    USE SIGNAL ;
    PORT
      LAYER M4 ;
        RECT  0 18.096 0.084 18.12 ;
    END
  END in_epoch[74]
  PIN in_epoch[75]
    DIRECTION INPUT ;
    USE SIGNAL ;
    PORT
      LAYER M4 ;
        RECT  0 18.192 0.084 18.216 ;
    END
  END in_epoch[75]
  PIN in_epoch[76]
    DIRECTION INPUT ;
    USE SIGNAL ;
    PORT
      LAYER M4 ;
        RECT  0 18.288 0.084 18.312 ;
    END
  END in_epoch[76]
  PIN in_epoch[77]
    DIRECTION INPUT ;
    USE SIGNAL ;
    PORT
      LAYER M4 ;
        RECT  0 18.384 0.084 18.408 ;
    END
  END in_epoch[77]
  PIN in_epoch[78]
    DIRECTION INPUT ;
    USE SIGNAL ;
    PORT
      LAYER M4 ;
        RECT  0 18.48 0.084 18.504 ;
    END
  END in_epoch[78]
  PIN in_epoch[79]
    DIRECTION INPUT ;
    USE SIGNAL ;
    PORT
      LAYER M4 ;
        RECT  0 18.576 0.084 18.6 ;
    END
  END in_epoch[79]
  PIN in_epoch[7]
    DIRECTION INPUT ;
    USE SIGNAL ;
    PORT
      LAYER M4 ;
        RECT  0 20.88 0.084 20.904 ;
    END
  END in_epoch[7]
  PIN in_epoch[80]
    DIRECTION INPUT ;
    USE SIGNAL ;
    PORT
      LAYER M4 ;
        RECT  0 18.672 0.084 18.696 ;
    END
  END in_epoch[80]
  PIN in_epoch[81]
    DIRECTION INPUT ;
    USE SIGNAL ;
    PORT
      LAYER M4 ;
        RECT  0 18.768 0.084 18.792 ;
    END
  END in_epoch[81]
  PIN in_epoch[82]
    DIRECTION INPUT ;
    USE SIGNAL ;
    PORT
      LAYER M4 ;
        RECT  0 18.864 0.084 18.888 ;
    END
  END in_epoch[82]
  PIN in_epoch[83]
    DIRECTION INPUT ;
    USE SIGNAL ;
    PORT
      LAYER M4 ;
        RECT  0 18.96 0.084 18.984 ;
    END
  END in_epoch[83]
  PIN in_epoch[84]
    DIRECTION INPUT ;
    USE SIGNAL ;
    PORT
      LAYER M4 ;
        RECT  0 19.056 0.084 19.08 ;
    END
  END in_epoch[84]
  PIN in_epoch[85]
    DIRECTION INPUT ;
    USE SIGNAL ;
    PORT
      LAYER M4 ;
        RECT  0 19.152 0.084 19.176 ;
    END
  END in_epoch[85]
  PIN in_epoch[86]
    DIRECTION INPUT ;
    USE SIGNAL ;
    PORT
      LAYER M4 ;
        RECT  0 19.248 0.084 19.272 ;
    END
  END in_epoch[86]
  PIN in_epoch[87]
    DIRECTION INPUT ;
    USE SIGNAL ;
    PORT
      LAYER M4 ;
        RECT  0 19.344 0.084 19.368 ;
    END
  END in_epoch[87]
  PIN in_epoch[88]
    DIRECTION INPUT ;
    USE SIGNAL ;
    PORT
      LAYER M4 ;
        RECT  0 19.44 0.084 19.464 ;
    END
  END in_epoch[88]
  PIN in_epoch[89]
    DIRECTION INPUT ;
    USE SIGNAL ;
    PORT
      LAYER M4 ;
        RECT  0 19.536 0.084 19.56 ;
    END
  END in_epoch[89]
  PIN in_epoch[8]
    DIRECTION INPUT ;
    USE SIGNAL ;
    PORT
      LAYER M4 ;
        RECT  0 20.976 0.084 21 ;
    END
  END in_epoch[8]
  PIN in_epoch[90]
    DIRECTION INPUT ;
    USE SIGNAL ;
    PORT
      LAYER M4 ;
        RECT  0 19.632 0.084 19.656 ;
    END
  END in_epoch[90]
  PIN in_epoch[91]
    DIRECTION INPUT ;
    USE SIGNAL ;
    PORT
      LAYER M4 ;
        RECT  0 19.728 0.084 19.752 ;
    END
  END in_epoch[91]
  PIN in_epoch[92]
    DIRECTION INPUT ;
    USE SIGNAL ;
    PORT
      LAYER M4 ;
        RECT  0 19.824 0.084 19.848 ;
    END
  END in_epoch[92]
  PIN in_epoch[93]
    DIRECTION INPUT ;
    USE SIGNAL ;
    PORT
      LAYER M4 ;
        RECT  0 19.92 0.084 19.944 ;
    END
  END in_epoch[93]
  PIN in_epoch[94]
    DIRECTION INPUT ;
    USE SIGNAL ;
    PORT
      LAYER M4 ;
        RECT  0 20.016 0.084 20.04 ;
    END
  END in_epoch[94]
  PIN in_epoch[95]
    DIRECTION INPUT ;
    USE SIGNAL ;
    PORT
      LAYER M4 ;
        RECT  0 20.112 0.084 20.136 ;
    END
  END in_epoch[95]
  PIN in_epoch[96]
    DIRECTION INPUT ;
    USE SIGNAL ;
    PORT
      LAYER M4 ;
        RECT  0 24.048 0.084 24.072 ;
    END
  END in_epoch[96]
  PIN in_epoch[97]
    DIRECTION INPUT ;
    USE SIGNAL ;
    PORT
      LAYER M4 ;
        RECT  0 24.144 0.084 24.168 ;
    END
  END in_epoch[97]
  PIN in_epoch[98]
    DIRECTION INPUT ;
    USE SIGNAL ;
    PORT
      LAYER M4 ;
        RECT  0 24.24 0.084 24.264 ;
    END
  END in_epoch[98]
  PIN in_epoch[99]
    DIRECTION INPUT ;
    USE SIGNAL ;
    PORT
      LAYER M4 ;
        RECT  0 24.336 0.084 24.36 ;
    END
  END in_epoch[99]
  PIN in_epoch[9]
    DIRECTION INPUT ;
    USE SIGNAL ;
    PORT
      LAYER M4 ;
        RECT  0 21.072 0.084 21.096 ;
    END
  END in_epoch[9]
  PIN in_t[0]
    DIRECTION INPUT ;
    USE SIGNAL ;
    PORT
      LAYER M4 ;
        RECT  0 14.064 0.084 14.088 ;
    END
  END in_t[0]
  PIN in_t[100]
    DIRECTION INPUT ;
    USE SIGNAL ;
    PORT
      LAYER M4 ;
        RECT  0 6 0.084 6.024 ;
    END
  END in_t[100]
  PIN in_t[101]
    DIRECTION INPUT ;
    USE SIGNAL ;
    PORT
      LAYER M4 ;
        RECT  0 6.096 0.084 6.12 ;
    END
  END in_t[101]
  PIN in_t[102]
    DIRECTION INPUT ;
    USE SIGNAL ;
    PORT
      LAYER M4 ;
        RECT  0 6.192 0.084 6.216 ;
    END
  END in_t[102]
  PIN in_t[103]
    DIRECTION INPUT ;
    USE SIGNAL ;
    PORT
      LAYER M4 ;
        RECT  0 6.288 0.084 6.312 ;
    END
  END in_t[103]
  PIN in_t[104]
    DIRECTION INPUT ;
    USE SIGNAL ;
    PORT
      LAYER M4 ;
        RECT  0 6.384 0.084 6.408 ;
    END
  END in_t[104]
  PIN in_t[105]
    DIRECTION INPUT ;
    USE SIGNAL ;
    PORT
      LAYER M4 ;
        RECT  0 6.48 0.084 6.504 ;
    END
  END in_t[105]
  PIN in_t[106]
    DIRECTION INPUT ;
    USE SIGNAL ;
    PORT
      LAYER M4 ;
        RECT  0 6.576 0.084 6.6 ;
    END
  END in_t[106]
  PIN in_t[107]
    DIRECTION INPUT ;
    USE SIGNAL ;
    PORT
      LAYER M4 ;
        RECT  0 6.672 0.084 6.696 ;
    END
  END in_t[107]
  PIN in_t[108]
    DIRECTION INPUT ;
    USE SIGNAL ;
    PORT
      LAYER M4 ;
        RECT  0 6.768 0.084 6.792 ;
    END
  END in_t[108]
  PIN in_t[109]
    DIRECTION INPUT ;
    USE SIGNAL ;
    PORT
      LAYER M4 ;
        RECT  0 6.864 0.084 6.888 ;
    END
  END in_t[109]
  PIN in_t[10]
    DIRECTION INPUT ;
    USE SIGNAL ;
    PORT
      LAYER M4 ;
        RECT  0 15.024 0.084 15.048 ;
    END
  END in_t[10]
  PIN in_t[110]
    DIRECTION INPUT ;
    USE SIGNAL ;
    PORT
      LAYER M4 ;
        RECT  0 6.96 0.084 6.984 ;
    END
  END in_t[110]
  PIN in_t[111]
    DIRECTION INPUT ;
    USE SIGNAL ;
    PORT
      LAYER M4 ;
        RECT  0 7.056 0.084 7.08 ;
    END
  END in_t[111]
  PIN in_t[11]
    DIRECTION INPUT ;
    USE SIGNAL ;
    PORT
      LAYER M4 ;
        RECT  0 15.12 0.084 15.144 ;
    END
  END in_t[11]
  PIN in_t[12]
    DIRECTION INPUT ;
    USE SIGNAL ;
    PORT
      LAYER M4 ;
        RECT  0 15.216 0.084 15.24 ;
    END
  END in_t[12]
  PIN in_t[13]
    DIRECTION INPUT ;
    USE SIGNAL ;
    PORT
      LAYER M4 ;
        RECT  0 15.312 0.084 15.336 ;
    END
  END in_t[13]
  PIN in_t[14]
    DIRECTION INPUT ;
    USE SIGNAL ;
    PORT
      LAYER M4 ;
        RECT  0 15.408 0.084 15.432 ;
    END
  END in_t[14]
  PIN in_t[15]
    DIRECTION INPUT ;
    USE SIGNAL ;
    PORT
      LAYER M4 ;
        RECT  0 15.504 0.084 15.528 ;
    END
  END in_t[15]
  PIN in_t[16]
    DIRECTION INPUT ;
    USE SIGNAL ;
    PORT
      LAYER M4 ;
        RECT  0 15.6 0.084 15.624 ;
    END
  END in_t[16]
  PIN in_t[17]
    DIRECTION INPUT ;
    USE SIGNAL ;
    PORT
      LAYER M4 ;
        RECT  0 15.696 0.084 15.72 ;
    END
  END in_t[17]
  PIN in_t[18]
    DIRECTION INPUT ;
    USE SIGNAL ;
    PORT
      LAYER M4 ;
        RECT  0 15.792 0.084 15.816 ;
    END
  END in_t[18]
  PIN in_t[19]
    DIRECTION INPUT ;
    USE SIGNAL ;
    PORT
      LAYER M4 ;
        RECT  0 15.888 0.084 15.912 ;
    END
  END in_t[19]
  PIN in_t[1]
    DIRECTION INPUT ;
    USE SIGNAL ;
    PORT
      LAYER M4 ;
        RECT  0 14.16 0.084 14.184 ;
    END
  END in_t[1]
  PIN in_t[20]
    DIRECTION INPUT ;
    USE SIGNAL ;
    PORT
      LAYER M4 ;
        RECT  0 15.984 0.084 16.008 ;
    END
  END in_t[20]
  PIN in_t[21]
    DIRECTION INPUT ;
    USE SIGNAL ;
    PORT
      LAYER M4 ;
        RECT  0 16.08 0.084 16.104 ;
    END
  END in_t[21]
  PIN in_t[22]
    DIRECTION INPUT ;
    USE SIGNAL ;
    PORT
      LAYER M4 ;
        RECT  0 16.176 0.084 16.2 ;
    END
  END in_t[22]
  PIN in_t[23]
    DIRECTION INPUT ;
    USE SIGNAL ;
    PORT
      LAYER M4 ;
        RECT  0 16.272 0.084 16.296 ;
    END
  END in_t[23]
  PIN in_t[24]
    DIRECTION INPUT ;
    USE SIGNAL ;
    PORT
      LAYER M4 ;
        RECT  0 16.368 0.084 16.392 ;
    END
  END in_t[24]
  PIN in_t[25]
    DIRECTION INPUT ;
    USE SIGNAL ;
    PORT
      LAYER M4 ;
        RECT  0 16.464 0.084 16.488 ;
    END
  END in_t[25]
  PIN in_t[26]
    DIRECTION INPUT ;
    USE SIGNAL ;
    PORT
      LAYER M4 ;
        RECT  0 16.56 0.084 16.584 ;
    END
  END in_t[26]
  PIN in_t[27]
    DIRECTION INPUT ;
    USE SIGNAL ;
    PORT
      LAYER M4 ;
        RECT  0 16.656 0.084 16.68 ;
    END
  END in_t[27]
  PIN in_t[28]
    DIRECTION INPUT ;
    USE SIGNAL ;
    PORT
      LAYER M4 ;
        RECT  0 16.752 0.084 16.776 ;
    END
  END in_t[28]
  PIN in_t[29]
    DIRECTION INPUT ;
    USE SIGNAL ;
    PORT
      LAYER M4 ;
        RECT  0 16.848 0.084 16.872 ;
    END
  END in_t[29]
  PIN in_t[2]
    DIRECTION INPUT ;
    USE SIGNAL ;
    PORT
      LAYER M4 ;
        RECT  0 14.256 0.084 14.28 ;
    END
  END in_t[2]
  PIN in_t[30]
    DIRECTION INPUT ;
    USE SIGNAL ;
    PORT
      LAYER M4 ;
        RECT  0 16.944 0.084 16.968 ;
    END
  END in_t[30]
  PIN in_t[31]
    DIRECTION INPUT ;
    USE SIGNAL ;
    PORT
      LAYER M4 ;
        RECT  0 17.04 0.084 17.064 ;
    END
  END in_t[31]
  PIN in_t[32]
    DIRECTION INPUT ;
    USE SIGNAL ;
    PORT
      LAYER M4 ;
        RECT  0 10.992 0.084 11.016 ;
    END
  END in_t[32]
  PIN in_t[33]
    DIRECTION INPUT ;
    USE SIGNAL ;
    PORT
      LAYER M4 ;
        RECT  0 11.088 0.084 11.112 ;
    END
  END in_t[33]
  PIN in_t[34]
    DIRECTION INPUT ;
    USE SIGNAL ;
    PORT
      LAYER M4 ;
        RECT  0 11.184 0.084 11.208 ;
    END
  END in_t[34]
  PIN in_t[35]
    DIRECTION INPUT ;
    USE SIGNAL ;
    PORT
      LAYER M4 ;
        RECT  0 11.28 0.084 11.304 ;
    END
  END in_t[35]
  PIN in_t[36]
    DIRECTION INPUT ;
    USE SIGNAL ;
    PORT
      LAYER M4 ;
        RECT  0 11.376 0.084 11.4 ;
    END
  END in_t[36]
  PIN in_t[37]
    DIRECTION INPUT ;
    USE SIGNAL ;
    PORT
      LAYER M4 ;
        RECT  0 11.472 0.084 11.496 ;
    END
  END in_t[37]
  PIN in_t[38]
    DIRECTION INPUT ;
    USE SIGNAL ;
    PORT
      LAYER M4 ;
        RECT  0 11.568 0.084 11.592 ;
    END
  END in_t[38]
  PIN in_t[39]
    DIRECTION INPUT ;
    USE SIGNAL ;
    PORT
      LAYER M4 ;
        RECT  0 11.664 0.084 11.688 ;
    END
  END in_t[39]
  PIN in_t[3]
    DIRECTION INPUT ;
    USE SIGNAL ;
    PORT
      LAYER M4 ;
        RECT  0 14.352 0.084 14.376 ;
    END
  END in_t[3]
  PIN in_t[40]
    DIRECTION INPUT ;
    USE SIGNAL ;
    PORT
      LAYER M4 ;
        RECT  0 11.76 0.084 11.784 ;
    END
  END in_t[40]
  PIN in_t[41]
    DIRECTION INPUT ;
    USE SIGNAL ;
    PORT
      LAYER M4 ;
        RECT  0 11.856 0.084 11.88 ;
    END
  END in_t[41]
  PIN in_t[42]
    DIRECTION INPUT ;
    USE SIGNAL ;
    PORT
      LAYER M4 ;
        RECT  0 11.952 0.084 11.976 ;
    END
  END in_t[42]
  PIN in_t[43]
    DIRECTION INPUT ;
    USE SIGNAL ;
    PORT
      LAYER M4 ;
        RECT  0 12.048 0.084 12.072 ;
    END
  END in_t[43]
  PIN in_t[44]
    DIRECTION INPUT ;
    USE SIGNAL ;
    PORT
      LAYER M4 ;
        RECT  0 12.144 0.084 12.168 ;
    END
  END in_t[44]
  PIN in_t[45]
    DIRECTION INPUT ;
    USE SIGNAL ;
    PORT
      LAYER M4 ;
        RECT  0 12.24 0.084 12.264 ;
    END
  END in_t[45]
  PIN in_t[46]
    DIRECTION INPUT ;
    USE SIGNAL ;
    PORT
      LAYER M4 ;
        RECT  0 12.336 0.084 12.36 ;
    END
  END in_t[46]
  PIN in_t[47]
    DIRECTION INPUT ;
    USE SIGNAL ;
    PORT
      LAYER M4 ;
        RECT  0 12.432 0.084 12.456 ;
    END
  END in_t[47]
  PIN in_t[48]
    DIRECTION INPUT ;
    USE SIGNAL ;
    PORT
      LAYER M4 ;
        RECT  0 12.528 0.084 12.552 ;
    END
  END in_t[48]
  PIN in_t[49]
    DIRECTION INPUT ;
    USE SIGNAL ;
    PORT
      LAYER M4 ;
        RECT  0 12.624 0.084 12.648 ;
    END
  END in_t[49]
  PIN in_t[4]
    DIRECTION INPUT ;
    USE SIGNAL ;
    PORT
      LAYER M4 ;
        RECT  0 14.448 0.084 14.472 ;
    END
  END in_t[4]
  PIN in_t[50]
    DIRECTION INPUT ;
    USE SIGNAL ;
    PORT
      LAYER M4 ;
        RECT  0 12.72 0.084 12.744 ;
    END
  END in_t[50]
  PIN in_t[51]
    DIRECTION INPUT ;
    USE SIGNAL ;
    PORT
      LAYER M4 ;
        RECT  0 12.816 0.084 12.84 ;
    END
  END in_t[51]
  PIN in_t[52]
    DIRECTION INPUT ;
    USE SIGNAL ;
    PORT
      LAYER M4 ;
        RECT  0 12.912 0.084 12.936 ;
    END
  END in_t[52]
  PIN in_t[53]
    DIRECTION INPUT ;
    USE SIGNAL ;
    PORT
      LAYER M4 ;
        RECT  0 13.008 0.084 13.032 ;
    END
  END in_t[53]
  PIN in_t[54]
    DIRECTION INPUT ;
    USE SIGNAL ;
    PORT
      LAYER M4 ;
        RECT  0 13.104 0.084 13.128 ;
    END
  END in_t[54]
  PIN in_t[55]
    DIRECTION INPUT ;
    USE SIGNAL ;
    PORT
      LAYER M4 ;
        RECT  0 13.2 0.084 13.224 ;
    END
  END in_t[55]
  PIN in_t[56]
    DIRECTION INPUT ;
    USE SIGNAL ;
    PORT
      LAYER M4 ;
        RECT  0 13.296 0.084 13.32 ;
    END
  END in_t[56]
  PIN in_t[57]
    DIRECTION INPUT ;
    USE SIGNAL ;
    PORT
      LAYER M4 ;
        RECT  0 13.392 0.084 13.416 ;
    END
  END in_t[57]
  PIN in_t[58]
    DIRECTION INPUT ;
    USE SIGNAL ;
    PORT
      LAYER M4 ;
        RECT  0 13.488 0.084 13.512 ;
    END
  END in_t[58]
  PIN in_t[59]
    DIRECTION INPUT ;
    USE SIGNAL ;
    PORT
      LAYER M4 ;
        RECT  0 13.584 0.084 13.608 ;
    END
  END in_t[59]
  PIN in_t[5]
    DIRECTION INPUT ;
    USE SIGNAL ;
    PORT
      LAYER M4 ;
        RECT  0 14.544 0.084 14.568 ;
    END
  END in_t[5]
  PIN in_t[60]
    DIRECTION INPUT ;
    USE SIGNAL ;
    PORT
      LAYER M4 ;
        RECT  0 13.68 0.084 13.704 ;
    END
  END in_t[60]
  PIN in_t[61]
    DIRECTION INPUT ;
    USE SIGNAL ;
    PORT
      LAYER M4 ;
        RECT  0 13.776 0.084 13.8 ;
    END
  END in_t[61]
  PIN in_t[62]
    DIRECTION INPUT ;
    USE SIGNAL ;
    PORT
      LAYER M4 ;
        RECT  0 13.872 0.084 13.896 ;
    END
  END in_t[62]
  PIN in_t[63]
    DIRECTION INPUT ;
    USE SIGNAL ;
    PORT
      LAYER M4 ;
        RECT  0 13.968 0.084 13.992 ;
    END
  END in_t[63]
  PIN in_t[64]
    DIRECTION INPUT ;
    USE SIGNAL ;
    PORT
      LAYER M4 ;
        RECT  0 7.92 0.084 7.944 ;
    END
  END in_t[64]
  PIN in_t[65]
    DIRECTION INPUT ;
    USE SIGNAL ;
    PORT
      LAYER M4 ;
        RECT  0 8.016 0.084 8.04 ;
    END
  END in_t[65]
  PIN in_t[66]
    DIRECTION INPUT ;
    USE SIGNAL ;
    PORT
      LAYER M4 ;
        RECT  0 8.112 0.084 8.136 ;
    END
  END in_t[66]
  PIN in_t[67]
    DIRECTION INPUT ;
    USE SIGNAL ;
    PORT
      LAYER M4 ;
        RECT  0 8.208 0.084 8.232 ;
    END
  END in_t[67]
  PIN in_t[68]
    DIRECTION INPUT ;
    USE SIGNAL ;
    PORT
      LAYER M4 ;
        RECT  0 8.304 0.084 8.328 ;
    END
  END in_t[68]
  PIN in_t[69]
    DIRECTION INPUT ;
    USE SIGNAL ;
    PORT
      LAYER M4 ;
        RECT  0 8.4 0.084 8.424 ;
    END
  END in_t[69]
  PIN in_t[6]
    DIRECTION INPUT ;
    USE SIGNAL ;
    PORT
      LAYER M4 ;
        RECT  0 14.64 0.084 14.664 ;
    END
  END in_t[6]
  PIN in_t[70]
    DIRECTION INPUT ;
    USE SIGNAL ;
    PORT
      LAYER M4 ;
        RECT  0 8.496 0.084 8.52 ;
    END
  END in_t[70]
  PIN in_t[71]
    DIRECTION INPUT ;
    USE SIGNAL ;
    PORT
      LAYER M4 ;
        RECT  0 8.592 0.084 8.616 ;
    END
  END in_t[71]
  PIN in_t[72]
    DIRECTION INPUT ;
    USE SIGNAL ;
    PORT
      LAYER M4 ;
        RECT  0 8.688 0.084 8.712 ;
    END
  END in_t[72]
  PIN in_t[73]
    DIRECTION INPUT ;
    USE SIGNAL ;
    PORT
      LAYER M4 ;
        RECT  0 8.784 0.084 8.808 ;
    END
  END in_t[73]
  PIN in_t[74]
    DIRECTION INPUT ;
    USE SIGNAL ;
    PORT
      LAYER M4 ;
        RECT  0 8.88 0.084 8.904 ;
    END
  END in_t[74]
  PIN in_t[75]
    DIRECTION INPUT ;
    USE SIGNAL ;
    PORT
      LAYER M4 ;
        RECT  0 8.976 0.084 9 ;
    END
  END in_t[75]
  PIN in_t[76]
    DIRECTION INPUT ;
    USE SIGNAL ;
    PORT
      LAYER M4 ;
        RECT  0 9.072 0.084 9.096 ;
    END
  END in_t[76]
  PIN in_t[77]
    DIRECTION INPUT ;
    USE SIGNAL ;
    PORT
      LAYER M4 ;
        RECT  0 9.168 0.084 9.192 ;
    END
  END in_t[77]
  PIN in_t[78]
    DIRECTION INPUT ;
    USE SIGNAL ;
    PORT
      LAYER M4 ;
        RECT  0 9.264 0.084 9.288 ;
    END
  END in_t[78]
  PIN in_t[79]
    DIRECTION INPUT ;
    USE SIGNAL ;
    PORT
      LAYER M4 ;
        RECT  0 9.36 0.084 9.384 ;
    END
  END in_t[79]
  PIN in_t[7]
    DIRECTION INPUT ;
    USE SIGNAL ;
    PORT
      LAYER M4 ;
        RECT  0 14.736 0.084 14.76 ;
    END
  END in_t[7]
  PIN in_t[80]
    DIRECTION INPUT ;
    USE SIGNAL ;
    PORT
      LAYER M4 ;
        RECT  0 9.456 0.084 9.48 ;
    END
  END in_t[80]
  PIN in_t[81]
    DIRECTION INPUT ;
    USE SIGNAL ;
    PORT
      LAYER M4 ;
        RECT  0 9.552 0.084 9.576 ;
    END
  END in_t[81]
  PIN in_t[82]
    DIRECTION INPUT ;
    USE SIGNAL ;
    PORT
      LAYER M4 ;
        RECT  0 9.648 0.084 9.672 ;
    END
  END in_t[82]
  PIN in_t[83]
    DIRECTION INPUT ;
    USE SIGNAL ;
    PORT
      LAYER M4 ;
        RECT  0 9.744 0.084 9.768 ;
    END
  END in_t[83]
  PIN in_t[84]
    DIRECTION INPUT ;
    USE SIGNAL ;
    PORT
      LAYER M4 ;
        RECT  0 9.84 0.084 9.864 ;
    END
  END in_t[84]
  PIN in_t[85]
    DIRECTION INPUT ;
    USE SIGNAL ;
    PORT
      LAYER M4 ;
        RECT  0 9.936 0.084 9.96 ;
    END
  END in_t[85]
  PIN in_t[86]
    DIRECTION INPUT ;
    USE SIGNAL ;
    PORT
      LAYER M4 ;
        RECT  0 10.032 0.084 10.056 ;
    END
  END in_t[86]
  PIN in_t[87]
    DIRECTION INPUT ;
    USE SIGNAL ;
    PORT
      LAYER M4 ;
        RECT  0 10.128 0.084 10.152 ;
    END
  END in_t[87]
  PIN in_t[88]
    DIRECTION INPUT ;
    USE SIGNAL ;
    PORT
      LAYER M4 ;
        RECT  0 10.224 0.084 10.248 ;
    END
  END in_t[88]
  PIN in_t[89]
    DIRECTION INPUT ;
    USE SIGNAL ;
    PORT
      LAYER M4 ;
        RECT  0 10.32 0.084 10.344 ;
    END
  END in_t[89]
  PIN in_t[8]
    DIRECTION INPUT ;
    USE SIGNAL ;
    PORT
      LAYER M4 ;
        RECT  0 14.832 0.084 14.856 ;
    END
  END in_t[8]
  PIN in_t[90]
    DIRECTION INPUT ;
    USE SIGNAL ;
    PORT
      LAYER M4 ;
        RECT  0 10.416 0.084 10.44 ;
    END
  END in_t[90]
  PIN in_t[91]
    DIRECTION INPUT ;
    USE SIGNAL ;
    PORT
      LAYER M4 ;
        RECT  0 10.512 0.084 10.536 ;
    END
  END in_t[91]
  PIN in_t[92]
    DIRECTION INPUT ;
    USE SIGNAL ;
    PORT
      LAYER M4 ;
        RECT  0 10.608 0.084 10.632 ;
    END
  END in_t[92]
  PIN in_t[93]
    DIRECTION INPUT ;
    USE SIGNAL ;
    PORT
      LAYER M4 ;
        RECT  0 10.704 0.084 10.728 ;
    END
  END in_t[93]
  PIN in_t[94]
    DIRECTION INPUT ;
    USE SIGNAL ;
    PORT
      LAYER M4 ;
        RECT  0 10.8 0.084 10.824 ;
    END
  END in_t[94]
  PIN in_t[95]
    DIRECTION INPUT ;
    USE SIGNAL ;
    PORT
      LAYER M4 ;
        RECT  0 10.896 0.084 10.92 ;
    END
  END in_t[95]
  PIN in_t[96]
    DIRECTION INPUT ;
    USE SIGNAL ;
    PORT
      LAYER M4 ;
        RECT  0 5.616 0.084 5.64 ;
    END
  END in_t[96]
  PIN in_t[97]
    DIRECTION INPUT ;
    USE SIGNAL ;
    PORT
      LAYER M4 ;
        RECT  0 5.712 0.084 5.736 ;
    END
  END in_t[97]
  PIN in_t[98]
    DIRECTION INPUT ;
    USE SIGNAL ;
    PORT
      LAYER M4 ;
        RECT  0 5.808 0.084 5.832 ;
    END
  END in_t[98]
  PIN in_t[99]
    DIRECTION INPUT ;
    USE SIGNAL ;
    PORT
      LAYER M4 ;
        RECT  0 5.904 0.084 5.928 ;
    END
  END in_t[99]
  PIN in_t[9]
    DIRECTION INPUT ;
    USE SIGNAL ;
    PORT
      LAYER M4 ;
        RECT  0 14.928 0.084 14.952 ;
    END
  END in_t[9]
  PIN in_valid[0]
    DIRECTION INPUT ;
    USE SIGNAL ;
    PORT
      LAYER M4 ;
        RECT  0 7.152 0.084 7.176 ;
    END
  END in_valid[0]
  PIN in_valid[1]
    DIRECTION INPUT ;
    USE SIGNAL ;
    PORT
      LAYER M4 ;
        RECT  0 7.248 0.084 7.272 ;
    END
  END in_valid[1]
  PIN in_valid[2]
    DIRECTION INPUT ;
    USE SIGNAL ;
    PORT
      LAYER M4 ;
        RECT  0 7.344 0.084 7.368 ;
    END
  END in_valid[2]
  PIN in_valid[3]
    DIRECTION INPUT ;
    USE SIGNAL ;
    PORT
      LAYER M4 ;
        RECT  0 7.44 0.084 7.464 ;
    END
  END in_valid[3]
  PIN in_valid[4]
    DIRECTION INPUT ;
    USE SIGNAL ;
    PORT
      LAYER M4 ;
        RECT  0 7.536 0.084 7.56 ;
    END
  END in_valid[4]
  PIN in_valid[5]
    DIRECTION INPUT ;
    USE SIGNAL ;
    PORT
      LAYER M4 ;
        RECT  0 7.632 0.084 7.656 ;
    END
  END in_valid[5]
  PIN in_valid[6]
    DIRECTION INPUT ;
    USE SIGNAL ;
    PORT
      LAYER M4 ;
        RECT  0 7.728 0.084 7.752 ;
    END
  END in_valid[6]
  PIN in_valid[7]
    DIRECTION INPUT ;
    USE SIGNAL ;
    PORT
      LAYER M4 ;
        RECT  0 7.824 0.084 7.848 ;
    END
  END in_valid[7]
  PIN out_age[0]
    DIRECTION OUTPUT ;
    USE SIGNAL ;
    PORT
      LAYER M5 ;
        RECT  20.016 0 20.04 0.084 ;
    END
  END out_age[0]
  PIN out_age[10]
    DIRECTION OUTPUT ;
    USE SIGNAL ;
    PORT
      LAYER M5 ;
        RECT  20.976 0 21 0.084 ;
    END
  END out_age[10]
  PIN out_age[11]
    DIRECTION OUTPUT ;
    USE SIGNAL ;
    PORT
      LAYER M5 ;
        RECT  21.072 0 21.096 0.084 ;
    END
  END out_age[11]
  PIN out_age[12]
    DIRECTION OUTPUT ;
    USE SIGNAL ;
    PORT
      LAYER M5 ;
        RECT  21.168 0 21.192 0.084 ;
    END
  END out_age[12]
  PIN out_age[13]
    DIRECTION OUTPUT ;
    USE SIGNAL ;
    PORT
      LAYER M5 ;
        RECT  21.264 0 21.288 0.084 ;
    END
  END out_age[13]
  PIN out_age[14]
    DIRECTION OUTPUT ;
    USE SIGNAL ;
    PORT
      LAYER M5 ;
        RECT  21.36 0 21.384 0.084 ;
    END
  END out_age[14]
  PIN out_age[15]
    DIRECTION OUTPUT ;
    USE SIGNAL ;
    PORT
      LAYER M5 ;
        RECT  21.456 0 21.48 0.084 ;
    END
  END out_age[15]
  PIN out_age[1]
    DIRECTION OUTPUT ;
    USE SIGNAL ;
    PORT
      LAYER M5 ;
        RECT  20.112 0 20.136 0.084 ;
    END
  END out_age[1]
  PIN out_age[2]
    DIRECTION OUTPUT ;
    USE SIGNAL ;
    PORT
      LAYER M5 ;
        RECT  20.208 0 20.232 0.084 ;
    END
  END out_age[2]
  PIN out_age[3]
    DIRECTION OUTPUT ;
    USE SIGNAL ;
    PORT
      LAYER M5 ;
        RECT  20.304 0 20.328 0.084 ;
    END
  END out_age[3]
  PIN out_age[4]
    DIRECTION OUTPUT ;
    USE SIGNAL ;
    PORT
      LAYER M5 ;
        RECT  20.4 0 20.424 0.084 ;
    END
  END out_age[4]
  PIN out_age[5]
    DIRECTION OUTPUT ;
    USE SIGNAL ;
    PORT
      LAYER M5 ;
        RECT  20.496 0 20.52 0.084 ;
    END
  END out_age[5]
  PIN out_age[6]
    DIRECTION OUTPUT ;
    USE SIGNAL ;
    PORT
      LAYER M5 ;
        RECT  20.592 0 20.616 0.084 ;
    END
  END out_age[6]
  PIN out_age[7]
    DIRECTION OUTPUT ;
    USE SIGNAL ;
    PORT
      LAYER M5 ;
        RECT  20.688 0 20.712 0.084 ;
    END
  END out_age[7]
  PIN out_age[8]
    DIRECTION OUTPUT ;
    USE SIGNAL ;
    PORT
      LAYER M5 ;
        RECT  20.784 0 20.808 0.084 ;
    END
  END out_age[8]
  PIN out_age[9]
    DIRECTION OUTPUT ;
    USE SIGNAL ;
    PORT
      LAYER M5 ;
        RECT  20.88 0 20.904 0.084 ;
    END
  END out_age[9]
  PIN out_epoch[0]
    DIRECTION OUTPUT ;
    USE SIGNAL ;
    PORT
      LAYER M5 ;
        RECT  21.552 0 21.576 0.084 ;
    END
  END out_epoch[0]
  PIN out_epoch[10]
    DIRECTION OUTPUT ;
    USE SIGNAL ;
    PORT
      LAYER M5 ;
        RECT  22.512 0 22.536 0.084 ;
    END
  END out_epoch[10]
  PIN out_epoch[11]
    DIRECTION OUTPUT ;
    USE SIGNAL ;
    PORT
      LAYER M5 ;
        RECT  22.608 0 22.632 0.084 ;
    END
  END out_epoch[11]
  PIN out_epoch[12]
    DIRECTION OUTPUT ;
    USE SIGNAL ;
    PORT
      LAYER M5 ;
        RECT  22.704 0 22.728 0.084 ;
    END
  END out_epoch[12]
  PIN out_epoch[13]
    DIRECTION OUTPUT ;
    USE SIGNAL ;
    PORT
      LAYER M5 ;
        RECT  22.8 0 22.824 0.084 ;
    END
  END out_epoch[13]
  PIN out_epoch[14]
    DIRECTION OUTPUT ;
    USE SIGNAL ;
    PORT
      LAYER M5 ;
        RECT  22.896 0 22.92 0.084 ;
    END
  END out_epoch[14]
  PIN out_epoch[15]
    DIRECTION OUTPUT ;
    USE SIGNAL ;
    PORT
      LAYER M5 ;
        RECT  13.008 0 13.032 0.084 ;
    END
  END out_epoch[15]
  PIN out_epoch[1]
    DIRECTION OUTPUT ;
    USE SIGNAL ;
    PORT
      LAYER M5 ;
        RECT  21.648 0 21.672 0.084 ;
    END
  END out_epoch[1]
  PIN out_epoch[2]
    DIRECTION OUTPUT ;
    USE SIGNAL ;
    PORT
      LAYER M5 ;
        RECT  21.744 0 21.768 0.084 ;
    END
  END out_epoch[2]
  PIN out_epoch[3]
    DIRECTION OUTPUT ;
    USE SIGNAL ;
    PORT
      LAYER M5 ;
        RECT  21.84 0 21.864 0.084 ;
    END
  END out_epoch[3]
  PIN out_epoch[4]
    DIRECTION OUTPUT ;
    USE SIGNAL ;
    PORT
      LAYER M5 ;
        RECT  21.936 0 21.96 0.084 ;
    END
  END out_epoch[4]
  PIN out_epoch[5]
    DIRECTION OUTPUT ;
    USE SIGNAL ;
    PORT
      LAYER M5 ;
        RECT  22.032 0 22.056 0.084 ;
    END
  END out_epoch[5]
  PIN out_epoch[6]
    DIRECTION OUTPUT ;
    USE SIGNAL ;
    PORT
      LAYER M5 ;
        RECT  22.128 0 22.152 0.084 ;
    END
  END out_epoch[6]
  PIN out_epoch[7]
    DIRECTION OUTPUT ;
    USE SIGNAL ;
    PORT
      LAYER M5 ;
        RECT  22.224 0 22.248 0.084 ;
    END
  END out_epoch[7]
  PIN out_epoch[8]
    DIRECTION OUTPUT ;
    USE SIGNAL ;
    PORT
      LAYER M5 ;
        RECT  22.32 0 22.344 0.084 ;
    END
  END out_epoch[8]
  PIN out_epoch[9]
    DIRECTION OUTPUT ;
    USE SIGNAL ;
    PORT
      LAYER M5 ;
        RECT  22.416 0 22.44 0.084 ;
    END
  END out_epoch[9]
  PIN pair_id
    DIRECTION INPUT ;
    USE SIGNAL ;
    PORT
      LAYER M5 ;
        RECT  13.104 0 13.128 0.084 ;
    END
  END pair_id
  PIN req_t[0]
    DIRECTION OUTPUT ;
    USE SIGNAL ;
    PORT
      LAYER M4 ;
        RECT  43.116 39.12 43.2 39.144 ;
    END
  END req_t[0]
  PIN req_t[100]
    DIRECTION OUTPUT ;
    USE SIGNAL ;
    PORT
      LAYER M4 ;
        RECT  43.116 29.52 43.2 29.544 ;
    END
  END req_t[100]
  PIN req_t[101]
    DIRECTION OUTPUT ;
    USE SIGNAL ;
    PORT
      LAYER M4 ;
        RECT  43.116 29.616 43.2 29.64 ;
    END
  END req_t[101]
  PIN req_t[102]
    DIRECTION OUTPUT ;
    USE SIGNAL ;
    PORT
      LAYER M4 ;
        RECT  43.116 29.712 43.2 29.736 ;
    END
  END req_t[102]
  PIN req_t[103]
    DIRECTION OUTPUT ;
    USE SIGNAL ;
    PORT
      LAYER M4 ;
        RECT  43.116 29.808 43.2 29.832 ;
    END
  END req_t[103]
  PIN req_t[104]
    DIRECTION OUTPUT ;
    USE SIGNAL ;
    PORT
      LAYER M4 ;
        RECT  43.116 29.904 43.2 29.928 ;
    END
  END req_t[104]
  PIN req_t[105]
    DIRECTION OUTPUT ;
    USE SIGNAL ;
    PORT
      LAYER M4 ;
        RECT  43.116 30 43.2 30.024 ;
    END
  END req_t[105]
  PIN req_t[106]
    DIRECTION OUTPUT ;
    USE SIGNAL ;
    PORT
      LAYER M4 ;
        RECT  43.116 30.096 43.2 30.12 ;
    END
  END req_t[106]
  PIN req_t[107]
    DIRECTION OUTPUT ;
    USE SIGNAL ;
    PORT
      LAYER M4 ;
        RECT  43.116 30.192 43.2 30.216 ;
    END
  END req_t[107]
  PIN req_t[108]
    DIRECTION OUTPUT ;
    USE SIGNAL ;
    PORT
      LAYER M4 ;
        RECT  43.116 30.288 43.2 30.312 ;
    END
  END req_t[108]
  PIN req_t[109]
    DIRECTION OUTPUT ;
    USE SIGNAL ;
    PORT
      LAYER M4 ;
        RECT  43.116 30.384 43.2 30.408 ;
    END
  END req_t[109]
  PIN req_t[10]
    DIRECTION OUTPUT ;
    USE SIGNAL ;
    PORT
      LAYER M4 ;
        RECT  43.116 40.08 43.2 40.104 ;
    END
  END req_t[10]
  PIN req_t[110]
    DIRECTION OUTPUT ;
    USE SIGNAL ;
    PORT
      LAYER M4 ;
        RECT  43.116 30.48 43.2 30.504 ;
    END
  END req_t[110]
  PIN req_t[111]
    DIRECTION OUTPUT ;
    USE SIGNAL ;
    PORT
      LAYER M4 ;
        RECT  43.116 30.576 43.2 30.6 ;
    END
  END req_t[111]
  PIN req_t[11]
    DIRECTION OUTPUT ;
    USE SIGNAL ;
    PORT
      LAYER M4 ;
        RECT  43.116 40.176 43.2 40.2 ;
    END
  END req_t[11]
  PIN req_t[12]
    DIRECTION OUTPUT ;
    USE SIGNAL ;
    PORT
      LAYER M4 ;
        RECT  43.116 40.272 43.2 40.296 ;
    END
  END req_t[12]
  PIN req_t[13]
    DIRECTION OUTPUT ;
    USE SIGNAL ;
    PORT
      LAYER M4 ;
        RECT  43.116 40.368 43.2 40.392 ;
    END
  END req_t[13]
  PIN req_t[14]
    DIRECTION OUTPUT ;
    USE SIGNAL ;
    PORT
      LAYER M4 ;
        RECT  43.116 40.464 43.2 40.488 ;
    END
  END req_t[14]
  PIN req_t[15]
    DIRECTION OUTPUT ;
    USE SIGNAL ;
    PORT
      LAYER M4 ;
        RECT  43.116 40.56 43.2 40.584 ;
    END
  END req_t[15]
  PIN req_t[16]
    DIRECTION OUTPUT ;
    USE SIGNAL ;
    PORT
      LAYER M4 ;
        RECT  43.116 40.656 43.2 40.68 ;
    END
  END req_t[16]
  PIN req_t[17]
    DIRECTION OUTPUT ;
    USE SIGNAL ;
    PORT
      LAYER M4 ;
        RECT  43.116 40.752 43.2 40.776 ;
    END
  END req_t[17]
  PIN req_t[18]
    DIRECTION OUTPUT ;
    USE SIGNAL ;
    PORT
      LAYER M4 ;
        RECT  43.116 40.848 43.2 40.872 ;
    END
  END req_t[18]
  PIN req_t[19]
    DIRECTION OUTPUT ;
    USE SIGNAL ;
    PORT
      LAYER M4 ;
        RECT  43.116 40.944 43.2 40.968 ;
    END
  END req_t[19]
  PIN req_t[1]
    DIRECTION OUTPUT ;
    USE SIGNAL ;
    PORT
      LAYER M4 ;
        RECT  43.116 39.216 43.2 39.24 ;
    END
  END req_t[1]
  PIN req_t[20]
    DIRECTION OUTPUT ;
    USE SIGNAL ;
    PORT
      LAYER M4 ;
        RECT  43.116 41.04 43.2 41.064 ;
    END
  END req_t[20]
  PIN req_t[21]
    DIRECTION OUTPUT ;
    USE SIGNAL ;
    PORT
      LAYER M4 ;
        RECT  43.116 41.136 43.2 41.16 ;
    END
  END req_t[21]
  PIN req_t[22]
    DIRECTION OUTPUT ;
    USE SIGNAL ;
    PORT
      LAYER M4 ;
        RECT  43.116 41.232 43.2 41.256 ;
    END
  END req_t[22]
  PIN req_t[23]
    DIRECTION OUTPUT ;
    USE SIGNAL ;
    PORT
      LAYER M4 ;
        RECT  43.116 41.328 43.2 41.352 ;
    END
  END req_t[23]
  PIN req_t[24]
    DIRECTION OUTPUT ;
    USE SIGNAL ;
    PORT
      LAYER M4 ;
        RECT  43.116 41.424 43.2 41.448 ;
    END
  END req_t[24]
  PIN req_t[25]
    DIRECTION OUTPUT ;
    USE SIGNAL ;
    PORT
      LAYER M4 ;
        RECT  43.116 41.52 43.2 41.544 ;
    END
  END req_t[25]
  PIN req_t[26]
    DIRECTION OUTPUT ;
    USE SIGNAL ;
    PORT
      LAYER M4 ;
        RECT  43.116 41.616 43.2 41.64 ;
    END
  END req_t[26]
  PIN req_t[27]
    DIRECTION OUTPUT ;
    USE SIGNAL ;
    PORT
      LAYER M4 ;
        RECT  43.116 41.712 43.2 41.736 ;
    END
  END req_t[27]
  PIN req_t[28]
    DIRECTION OUTPUT ;
    USE SIGNAL ;
    PORT
      LAYER M4 ;
        RECT  43.116 41.808 43.2 41.832 ;
    END
  END req_t[28]
  PIN req_t[29]
    DIRECTION OUTPUT ;
    USE SIGNAL ;
    PORT
      LAYER M4 ;
        RECT  43.116 41.904 43.2 41.928 ;
    END
  END req_t[29]
  PIN req_t[2]
    DIRECTION OUTPUT ;
    USE SIGNAL ;
    PORT
      LAYER M4 ;
        RECT  43.116 39.312 43.2 39.336 ;
    END
  END req_t[2]
  PIN req_t[30]
    DIRECTION OUTPUT ;
    USE SIGNAL ;
    PORT
      LAYER M4 ;
        RECT  43.116 42 43.2 42.024 ;
    END
  END req_t[30]
  PIN req_t[31]
    DIRECTION OUTPUT ;
    USE SIGNAL ;
    PORT
      LAYER M4 ;
        RECT  43.116 42.096 43.2 42.12 ;
    END
  END req_t[31]
  PIN req_t[32]
    DIRECTION OUTPUT ;
    USE SIGNAL ;
    PORT
      LAYER M4 ;
        RECT  43.116 35.28 43.2 35.304 ;
    END
  END req_t[32]
  PIN req_t[33]
    DIRECTION OUTPUT ;
    USE SIGNAL ;
    PORT
      LAYER M4 ;
        RECT  43.116 35.376 43.2 35.4 ;
    END
  END req_t[33]
  PIN req_t[34]
    DIRECTION OUTPUT ;
    USE SIGNAL ;
    PORT
      LAYER M4 ;
        RECT  43.116 35.472 43.2 35.496 ;
    END
  END req_t[34]
  PIN req_t[35]
    DIRECTION OUTPUT ;
    USE SIGNAL ;
    PORT
      LAYER M4 ;
        RECT  43.116 35.568 43.2 35.592 ;
    END
  END req_t[35]
  PIN req_t[36]
    DIRECTION OUTPUT ;
    USE SIGNAL ;
    PORT
      LAYER M4 ;
        RECT  43.116 35.664 43.2 35.688 ;
    END
  END req_t[36]
  PIN req_t[37]
    DIRECTION OUTPUT ;
    USE SIGNAL ;
    PORT
      LAYER M4 ;
        RECT  43.116 35.76 43.2 35.784 ;
    END
  END req_t[37]
  PIN req_t[38]
    DIRECTION OUTPUT ;
    USE SIGNAL ;
    PORT
      LAYER M4 ;
        RECT  43.116 35.856 43.2 35.88 ;
    END
  END req_t[38]
  PIN req_t[39]
    DIRECTION OUTPUT ;
    USE SIGNAL ;
    PORT
      LAYER M4 ;
        RECT  43.116 35.952 43.2 35.976 ;
    END
  END req_t[39]
  PIN req_t[3]
    DIRECTION OUTPUT ;
    USE SIGNAL ;
    PORT
      LAYER M4 ;
        RECT  43.116 39.408 43.2 39.432 ;
    END
  END req_t[3]
  PIN req_t[40]
    DIRECTION OUTPUT ;
    USE SIGNAL ;
    PORT
      LAYER M4 ;
        RECT  43.116 36.048 43.2 36.072 ;
    END
  END req_t[40]
  PIN req_t[41]
    DIRECTION OUTPUT ;
    USE SIGNAL ;
    PORT
      LAYER M4 ;
        RECT  43.116 36.144 43.2 36.168 ;
    END
  END req_t[41]
  PIN req_t[42]
    DIRECTION OUTPUT ;
    USE SIGNAL ;
    PORT
      LAYER M4 ;
        RECT  43.116 36.24 43.2 36.264 ;
    END
  END req_t[42]
  PIN req_t[43]
    DIRECTION OUTPUT ;
    USE SIGNAL ;
    PORT
      LAYER M4 ;
        RECT  43.116 36.336 43.2 36.36 ;
    END
  END req_t[43]
  PIN req_t[44]
    DIRECTION OUTPUT ;
    USE SIGNAL ;
    PORT
      LAYER M4 ;
        RECT  43.116 36.432 43.2 36.456 ;
    END
  END req_t[44]
  PIN req_t[45]
    DIRECTION OUTPUT ;
    USE SIGNAL ;
    PORT
      LAYER M4 ;
        RECT  43.116 36.528 43.2 36.552 ;
    END
  END req_t[45]
  PIN req_t[46]
    DIRECTION OUTPUT ;
    USE SIGNAL ;
    PORT
      LAYER M4 ;
        RECT  43.116 36.624 43.2 36.648 ;
    END
  END req_t[46]
  PIN req_t[47]
    DIRECTION OUTPUT ;
    USE SIGNAL ;
    PORT
      LAYER M4 ;
        RECT  43.116 36.72 43.2 36.744 ;
    END
  END req_t[47]
  PIN req_t[48]
    DIRECTION OUTPUT ;
    USE SIGNAL ;
    PORT
      LAYER M4 ;
        RECT  43.116 36.816 43.2 36.84 ;
    END
  END req_t[48]
  PIN req_t[49]
    DIRECTION OUTPUT ;
    USE SIGNAL ;
    PORT
      LAYER M4 ;
        RECT  43.116 36.912 43.2 36.936 ;
    END
  END req_t[49]
  PIN req_t[4]
    DIRECTION OUTPUT ;
    USE SIGNAL ;
    PORT
      LAYER M4 ;
        RECT  43.116 39.504 43.2 39.528 ;
    END
  END req_t[4]
  PIN req_t[50]
    DIRECTION OUTPUT ;
    USE SIGNAL ;
    PORT
      LAYER M4 ;
        RECT  43.116 37.008 43.2 37.032 ;
    END
  END req_t[50]
  PIN req_t[51]
    DIRECTION OUTPUT ;
    USE SIGNAL ;
    PORT
      LAYER M4 ;
        RECT  43.116 37.104 43.2 37.128 ;
    END
  END req_t[51]
  PIN req_t[52]
    DIRECTION OUTPUT ;
    USE SIGNAL ;
    PORT
      LAYER M4 ;
        RECT  43.116 37.2 43.2 37.224 ;
    END
  END req_t[52]
  PIN req_t[53]
    DIRECTION OUTPUT ;
    USE SIGNAL ;
    PORT
      LAYER M4 ;
        RECT  43.116 37.296 43.2 37.32 ;
    END
  END req_t[53]
  PIN req_t[54]
    DIRECTION OUTPUT ;
    USE SIGNAL ;
    PORT
      LAYER M4 ;
        RECT  43.116 37.392 43.2 37.416 ;
    END
  END req_t[54]
  PIN req_t[55]
    DIRECTION OUTPUT ;
    USE SIGNAL ;
    PORT
      LAYER M4 ;
        RECT  43.116 37.488 43.2 37.512 ;
    END
  END req_t[55]
  PIN req_t[56]
    DIRECTION OUTPUT ;
    USE SIGNAL ;
    PORT
      LAYER M4 ;
        RECT  43.116 37.584 43.2 37.608 ;
    END
  END req_t[56]
  PIN req_t[57]
    DIRECTION OUTPUT ;
    USE SIGNAL ;
    PORT
      LAYER M4 ;
        RECT  43.116 37.68 43.2 37.704 ;
    END
  END req_t[57]
  PIN req_t[58]
    DIRECTION OUTPUT ;
    USE SIGNAL ;
    PORT
      LAYER M4 ;
        RECT  43.116 37.776 43.2 37.8 ;
    END
  END req_t[58]
  PIN req_t[59]
    DIRECTION OUTPUT ;
    USE SIGNAL ;
    PORT
      LAYER M4 ;
        RECT  43.116 37.872 43.2 37.896 ;
    END
  END req_t[59]
  PIN req_t[5]
    DIRECTION OUTPUT ;
    USE SIGNAL ;
    PORT
      LAYER M4 ;
        RECT  43.116 39.6 43.2 39.624 ;
    END
  END req_t[5]
  PIN req_t[60]
    DIRECTION OUTPUT ;
    USE SIGNAL ;
    PORT
      LAYER M4 ;
        RECT  43.116 37.968 43.2 37.992 ;
    END
  END req_t[60]
  PIN req_t[61]
    DIRECTION OUTPUT ;
    USE SIGNAL ;
    PORT
      LAYER M4 ;
        RECT  43.116 38.064 43.2 38.088 ;
    END
  END req_t[61]
  PIN req_t[62]
    DIRECTION OUTPUT ;
    USE SIGNAL ;
    PORT
      LAYER M4 ;
        RECT  43.116 38.16 43.2 38.184 ;
    END
  END req_t[62]
  PIN req_t[63]
    DIRECTION OUTPUT ;
    USE SIGNAL ;
    PORT
      LAYER M4 ;
        RECT  43.116 38.256 43.2 38.28 ;
    END
  END req_t[63]
  PIN req_t[64]
    DIRECTION OUTPUT ;
    USE SIGNAL ;
    PORT
      LAYER M4 ;
        RECT  43.116 32.208 43.2 32.232 ;
    END
  END req_t[64]
  PIN req_t[65]
    DIRECTION OUTPUT ;
    USE SIGNAL ;
    PORT
      LAYER M4 ;
        RECT  43.116 32.304 43.2 32.328 ;
    END
  END req_t[65]
  PIN req_t[66]
    DIRECTION OUTPUT ;
    USE SIGNAL ;
    PORT
      LAYER M4 ;
        RECT  43.116 32.4 43.2 32.424 ;
    END
  END req_t[66]
  PIN req_t[67]
    DIRECTION OUTPUT ;
    USE SIGNAL ;
    PORT
      LAYER M4 ;
        RECT  43.116 32.496 43.2 32.52 ;
    END
  END req_t[67]
  PIN req_t[68]
    DIRECTION OUTPUT ;
    USE SIGNAL ;
    PORT
      LAYER M4 ;
        RECT  43.116 32.592 43.2 32.616 ;
    END
  END req_t[68]
  PIN req_t[69]
    DIRECTION OUTPUT ;
    USE SIGNAL ;
    PORT
      LAYER M4 ;
        RECT  43.116 32.688 43.2 32.712 ;
    END
  END req_t[69]
  PIN req_t[6]
    DIRECTION OUTPUT ;
    USE SIGNAL ;
    PORT
      LAYER M4 ;
        RECT  43.116 39.696 43.2 39.72 ;
    END
  END req_t[6]
  PIN req_t[70]
    DIRECTION OUTPUT ;
    USE SIGNAL ;
    PORT
      LAYER M4 ;
        RECT  43.116 32.784 43.2 32.808 ;
    END
  END req_t[70]
  PIN req_t[71]
    DIRECTION OUTPUT ;
    USE SIGNAL ;
    PORT
      LAYER M4 ;
        RECT  43.116 32.88 43.2 32.904 ;
    END
  END req_t[71]
  PIN req_t[72]
    DIRECTION OUTPUT ;
    USE SIGNAL ;
    PORT
      LAYER M4 ;
        RECT  43.116 32.976 43.2 33 ;
    END
  END req_t[72]
  PIN req_t[73]
    DIRECTION OUTPUT ;
    USE SIGNAL ;
    PORT
      LAYER M4 ;
        RECT  43.116 33.072 43.2 33.096 ;
    END
  END req_t[73]
  PIN req_t[74]
    DIRECTION OUTPUT ;
    USE SIGNAL ;
    PORT
      LAYER M4 ;
        RECT  43.116 33.168 43.2 33.192 ;
    END
  END req_t[74]
  PIN req_t[75]
    DIRECTION OUTPUT ;
    USE SIGNAL ;
    PORT
      LAYER M4 ;
        RECT  43.116 33.264 43.2 33.288 ;
    END
  END req_t[75]
  PIN req_t[76]
    DIRECTION OUTPUT ;
    USE SIGNAL ;
    PORT
      LAYER M4 ;
        RECT  43.116 33.36 43.2 33.384 ;
    END
  END req_t[76]
  PIN req_t[77]
    DIRECTION OUTPUT ;
    USE SIGNAL ;
    PORT
      LAYER M4 ;
        RECT  43.116 33.456 43.2 33.48 ;
    END
  END req_t[77]
  PIN req_t[78]
    DIRECTION OUTPUT ;
    USE SIGNAL ;
    PORT
      LAYER M4 ;
        RECT  43.116 33.552 43.2 33.576 ;
    END
  END req_t[78]
  PIN req_t[79]
    DIRECTION OUTPUT ;
    USE SIGNAL ;
    PORT
      LAYER M4 ;
        RECT  43.116 33.648 43.2 33.672 ;
    END
  END req_t[79]
  PIN req_t[7]
    DIRECTION OUTPUT ;
    USE SIGNAL ;
    PORT
      LAYER M4 ;
        RECT  43.116 39.792 43.2 39.816 ;
    END
  END req_t[7]
  PIN req_t[80]
    DIRECTION OUTPUT ;
    USE SIGNAL ;
    PORT
      LAYER M4 ;
        RECT  43.116 33.744 43.2 33.768 ;
    END
  END req_t[80]
  PIN req_t[81]
    DIRECTION OUTPUT ;
    USE SIGNAL ;
    PORT
      LAYER M4 ;
        RECT  43.116 33.84 43.2 33.864 ;
    END
  END req_t[81]
  PIN req_t[82]
    DIRECTION OUTPUT ;
    USE SIGNAL ;
    PORT
      LAYER M4 ;
        RECT  43.116 33.936 43.2 33.96 ;
    END
  END req_t[82]
  PIN req_t[83]
    DIRECTION OUTPUT ;
    USE SIGNAL ;
    PORT
      LAYER M4 ;
        RECT  43.116 34.032 43.2 34.056 ;
    END
  END req_t[83]
  PIN req_t[84]
    DIRECTION OUTPUT ;
    USE SIGNAL ;
    PORT
      LAYER M4 ;
        RECT  43.116 34.128 43.2 34.152 ;
    END
  END req_t[84]
  PIN req_t[85]
    DIRECTION OUTPUT ;
    USE SIGNAL ;
    PORT
      LAYER M4 ;
        RECT  43.116 34.224 43.2 34.248 ;
    END
  END req_t[85]
  PIN req_t[86]
    DIRECTION OUTPUT ;
    USE SIGNAL ;
    PORT
      LAYER M4 ;
        RECT  43.116 34.32 43.2 34.344 ;
    END
  END req_t[86]
  PIN req_t[87]
    DIRECTION OUTPUT ;
    USE SIGNAL ;
    PORT
      LAYER M4 ;
        RECT  43.116 34.416 43.2 34.44 ;
    END
  END req_t[87]
  PIN req_t[88]
    DIRECTION OUTPUT ;
    USE SIGNAL ;
    PORT
      LAYER M4 ;
        RECT  43.116 34.512 43.2 34.536 ;
    END
  END req_t[88]
  PIN req_t[89]
    DIRECTION OUTPUT ;
    USE SIGNAL ;
    PORT
      LAYER M4 ;
        RECT  43.116 34.608 43.2 34.632 ;
    END
  END req_t[89]
  PIN req_t[8]
    DIRECTION OUTPUT ;
    USE SIGNAL ;
    PORT
      LAYER M4 ;
        RECT  43.116 39.888 43.2 39.912 ;
    END
  END req_t[8]
  PIN req_t[90]
    DIRECTION OUTPUT ;
    USE SIGNAL ;
    PORT
      LAYER M4 ;
        RECT  43.116 34.704 43.2 34.728 ;
    END
  END req_t[90]
  PIN req_t[91]
    DIRECTION OUTPUT ;
    USE SIGNAL ;
    PORT
      LAYER M4 ;
        RECT  43.116 34.8 43.2 34.824 ;
    END
  END req_t[91]
  PIN req_t[92]
    DIRECTION OUTPUT ;
    USE SIGNAL ;
    PORT
      LAYER M4 ;
        RECT  43.116 34.896 43.2 34.92 ;
    END
  END req_t[92]
  PIN req_t[93]
    DIRECTION OUTPUT ;
    USE SIGNAL ;
    PORT
      LAYER M4 ;
        RECT  43.116 34.992 43.2 35.016 ;
    END
  END req_t[93]
  PIN req_t[94]
    DIRECTION OUTPUT ;
    USE SIGNAL ;
    PORT
      LAYER M4 ;
        RECT  43.116 35.088 43.2 35.112 ;
    END
  END req_t[94]
  PIN req_t[95]
    DIRECTION OUTPUT ;
    USE SIGNAL ;
    PORT
      LAYER M4 ;
        RECT  43.116 35.184 43.2 35.208 ;
    END
  END req_t[95]
  PIN req_t[96]
    DIRECTION OUTPUT ;
    USE SIGNAL ;
    PORT
      LAYER M4 ;
        RECT  43.116 29.136 43.2 29.16 ;
    END
  END req_t[96]
  PIN req_t[97]
    DIRECTION OUTPUT ;
    USE SIGNAL ;
    PORT
      LAYER M4 ;
        RECT  43.116 29.232 43.2 29.256 ;
    END
  END req_t[97]
  PIN req_t[98]
    DIRECTION OUTPUT ;
    USE SIGNAL ;
    PORT
      LAYER M4 ;
        RECT  43.116 29.328 43.2 29.352 ;
    END
  END req_t[98]
  PIN req_t[99]
    DIRECTION OUTPUT ;
    USE SIGNAL ;
    PORT
      LAYER M4 ;
        RECT  43.116 29.424 43.2 29.448 ;
    END
  END req_t[99]
  PIN req_t[9]
    DIRECTION OUTPUT ;
    USE SIGNAL ;
    PORT
      LAYER M4 ;
        RECT  43.116 39.984 43.2 40.008 ;
    END
  END req_t[9]
  PIN req_valid[0]
    DIRECTION OUTPUT ;
    USE SIGNAL ;
    PORT
      LAYER M4 ;
        RECT  43.116 30.672 43.2 30.696 ;
    END
  END req_valid[0]
  PIN req_valid[1]
    DIRECTION OUTPUT ;
    USE SIGNAL ;
    PORT
      LAYER M4 ;
        RECT  43.116 30.768 43.2 30.792 ;
    END
  END req_valid[1]
  PIN req_valid[2]
    DIRECTION OUTPUT ;
    USE SIGNAL ;
    PORT
      LAYER M4 ;
        RECT  43.116 30.864 43.2 30.888 ;
    END
  END req_valid[2]
  PIN req_valid[3]
    DIRECTION OUTPUT ;
    USE SIGNAL ;
    PORT
      LAYER M4 ;
        RECT  43.116 30.96 43.2 30.984 ;
    END
  END req_valid[3]
  PIN req_valid[4]
    DIRECTION OUTPUT ;
    USE SIGNAL ;
    PORT
      LAYER M4 ;
        RECT  43.116 31.056 43.2 31.08 ;
    END
  END req_valid[4]
  PIN req_valid[5]
    DIRECTION OUTPUT ;
    USE SIGNAL ;
    PORT
      LAYER M4 ;
        RECT  43.116 31.152 43.2 31.176 ;
    END
  END req_valid[5]
  PIN req_valid[6]
    DIRECTION OUTPUT ;
    USE SIGNAL ;
    PORT
      LAYER M4 ;
        RECT  43.116 31.248 43.2 31.272 ;
    END
  END req_valid[6]
  PIN req_valid[7]
    DIRECTION OUTPUT ;
    USE SIGNAL ;
    PORT
      LAYER M4 ;
        RECT  43.116 31.344 43.2 31.368 ;
    END
  END req_valid[7]
  PIN rst_n
    DIRECTION INPUT ;
    USE SIGNAL ;
    PORT
      LAYER M5 ;
        RECT  13.2 0 13.224 0.084 ;
    END
  END rst_n
  PIN start
    DIRECTION INPUT ;
    USE SIGNAL ;
    PORT
      LAYER M5 ;
        RECT  13.296 0 13.32 0.084 ;
    END
  END start
  PIN VDD
    DIRECTION INOUT ;
    USE POWER ;
    PORT
      LAYER M5 ;
        RECT  40.392 2.151 40.512 41.049 ;
        RECT  34.992 2.151 35.112 41.049 ;
        RECT  29.592 2.151 29.712 41.049 ;
        RECT  24.192 2.151 24.312 41.049 ;
        RECT  18.792 2.151 18.912 41.049 ;
        RECT  13.392 2.151 13.512 41.049 ;
        RECT  7.992 2.151 8.112 41.049 ;
        RECT  2.592 2.151 2.712 41.049 ;
    END
  END VDD
  PIN VSS
    DIRECTION INOUT ;
    USE GROUND ;
    PORT
      LAYER M5 ;
        RECT  40.2 2.137 40.32 41.063 ;
        RECT  34.8 2.137 34.92 41.063 ;
        RECT  29.4 2.137 29.52 41.063 ;
        RECT  24 2.137 24.12 41.063 ;
        RECT  18.6 2.137 18.72 41.063 ;
        RECT  13.2 2.137 13.32 41.063 ;
        RECT  7.8 2.137 7.92 41.063 ;
        RECT  2.4 2.137 2.52 41.063 ;
    END
  END VSS
  # OT_OBS_CLOSED layer=M5 d_um=1.536 added=127
  OBS
    LAYER RVTN ;
     RECT  2.16 2.16 41.04 2.295 ;
     RECT  2.16 2.565 41.04 2.835 ;
     RECT  2.16 3.105 41.04 3.375 ;
     RECT  2.16 3.645 41.04 3.915 ;
     RECT  2.16 4.185 41.04 4.455 ;
     RECT  2.16 4.725 41.04 4.995 ;
     RECT  2.16 5.265 41.04 5.535 ;
     RECT  2.16 5.805 41.04 6.075 ;
     RECT  2.16 6.345 41.04 6.615 ;
     RECT  2.16 6.885 41.04 7.155 ;
     RECT  2.16 7.425 41.04 7.695 ;
     RECT  2.16 7.965 41.04 8.235 ;
     RECT  2.16 8.505 41.04 8.775 ;
     RECT  2.16 9.045 41.04 9.315 ;
     RECT  2.16 9.585 41.04 9.855 ;
     RECT  2.16 10.125 41.04 10.395 ;
     RECT  2.16 10.665 41.04 10.935 ;
     RECT  2.16 11.205 41.04 11.475 ;
     RECT  2.16 11.745 41.04 12.015 ;
     RECT  2.16 12.285 41.04 12.555 ;
     RECT  2.16 12.825 41.04 13.095 ;
     RECT  2.16 13.365 41.04 13.635 ;
     RECT  2.16 13.905 41.04 14.175 ;
     RECT  2.16 14.445 41.04 14.715 ;
     RECT  2.16 14.985 41.04 15.255 ;
     RECT  2.16 15.525 41.04 15.795 ;
     RECT  2.16 16.065 41.04 16.335 ;
     RECT  2.16 16.605 41.04 16.875 ;
     RECT  2.16 17.145 41.04 17.415 ;
     RECT  2.16 17.685 41.04 17.955 ;
     RECT  2.16 18.225 41.04 18.495 ;
     RECT  2.16 18.765 41.04 19.035 ;
     RECT  2.16 19.305 41.04 19.575 ;
     RECT  2.16 19.845 41.04 20.115 ;
     RECT  2.16 20.385 41.04 20.655 ;
     RECT  2.16 20.925 41.04 21.195 ;
     RECT  2.16 21.465 41.04 21.735 ;
     RECT  2.16 22.005 41.04 22.275 ;
     RECT  2.16 22.545 41.04 22.815 ;
     RECT  2.16 23.085 41.04 23.355 ;
     RECT  2.16 23.625 41.04 23.895 ;
     RECT  2.16 24.165 41.04 24.435 ;
     RECT  2.16 24.705 41.04 24.975 ;
     RECT  2.16 25.245 41.04 25.515 ;
     RECT  2.16 25.785 41.04 26.055 ;
     RECT  2.16 26.325 41.04 26.595 ;
     RECT  2.16 26.865 41.04 27.135 ;
     RECT  2.16 27.405 41.04 27.675 ;
     RECT  2.16 27.945 41.04 28.215 ;
     RECT  2.16 28.485 41.04 28.755 ;
     RECT  2.16 29.025 41.04 29.295 ;
     RECT  2.16 29.565 41.04 29.835 ;
     RECT  2.16 30.105 41.04 30.375 ;
     RECT  2.16 30.645 41.04 30.915 ;
     RECT  2.16 31.185 41.04 31.455 ;
     RECT  2.16 31.725 41.04 31.995 ;
     RECT  2.16 32.265 41.04 32.535 ;
     RECT  2.16 32.805 41.04 33.075 ;
     RECT  2.16 33.345 41.04 33.615 ;
     RECT  2.16 33.885 41.04 34.155 ;
     RECT  2.16 34.425 41.04 34.695 ;
     RECT  2.16 34.965 41.04 35.235 ;
     RECT  2.16 35.505 41.04 35.775 ;
     RECT  2.16 36.045 41.04 36.315 ;
     RECT  2.16 36.585 41.04 36.855 ;
     RECT  2.16 37.125 41.04 37.395 ;
     RECT  2.16 37.665 41.04 37.935 ;
     RECT  2.16 38.205 41.04 38.475 ;
     RECT  2.16 38.745 41.04 39.015 ;
     RECT  2.16 39.285 41.04 39.555 ;
     RECT  2.16 39.825 41.04 40.095 ;
     RECT  2.16 40.365 41.04 40.635 ;
     RECT  2.16 40.905 41.04 41.04 ;
    LAYER RVTP ;
     RECT  2.16 2.295 41.04 2.565 ;
     RECT  2.16 2.835 41.04 3.105 ;
     RECT  2.16 3.375 41.04 3.645 ;
     RECT  2.16 3.915 41.04 4.185 ;
     RECT  2.16 4.455 41.04 4.725 ;
     RECT  2.16 4.995 41.04 5.265 ;
     RECT  2.16 5.535 41.04 5.805 ;
     RECT  2.16 6.075 41.04 6.345 ;
     RECT  2.16 6.615 41.04 6.885 ;
     RECT  2.16 7.155 41.04 7.425 ;
     RECT  2.16 7.695 41.04 7.965 ;
     RECT  2.16 8.235 41.04 8.505 ;
     RECT  2.16 8.775 41.04 9.045 ;
     RECT  2.16 9.315 41.04 9.585 ;
     RECT  2.16 9.855 41.04 10.125 ;
     RECT  2.16 10.395 41.04 10.665 ;
     RECT  2.16 10.935 41.04 11.205 ;
     RECT  2.16 11.475 41.04 11.745 ;
     RECT  2.16 12.015 41.04 12.285 ;
     RECT  2.16 12.555 41.04 12.825 ;
     RECT  2.16 13.095 41.04 13.365 ;
     RECT  2.16 13.635 41.04 13.905 ;
     RECT  2.16 14.175 41.04 14.445 ;
     RECT  2.16 14.715 41.04 14.985 ;
     RECT  2.16 15.255 41.04 15.525 ;
     RECT  2.16 15.795 41.04 16.065 ;
     RECT  2.16 16.335 41.04 16.605 ;
     RECT  2.16 16.875 41.04 17.145 ;
     RECT  2.16 17.415 41.04 17.685 ;
     RECT  2.16 17.955 41.04 18.225 ;
     RECT  2.16 18.495 41.04 18.765 ;
     RECT  2.16 19.035 41.04 19.305 ;
     RECT  2.16 19.575 41.04 19.845 ;
     RECT  2.16 20.115 41.04 20.385 ;
     RECT  2.16 20.655 41.04 20.925 ;
     RECT  2.16 21.195 41.04 21.465 ;
     RECT  2.16 21.735 41.04 22.005 ;
     RECT  2.16 22.275 41.04 22.545 ;
     RECT  2.16 22.815 41.04 23.085 ;
     RECT  2.16 23.355 41.04 23.625 ;
     RECT  2.16 23.895 41.04 24.165 ;
     RECT  2.16 24.435 41.04 24.705 ;
     RECT  2.16 24.975 41.04 25.245 ;
     RECT  2.16 25.515 41.04 25.785 ;
     RECT  2.16 26.055 41.04 26.325 ;
     RECT  2.16 26.595 41.04 26.865 ;
     RECT  2.16 27.135 41.04 27.405 ;
     RECT  2.16 27.675 41.04 27.945 ;
     RECT  2.16 28.215 41.04 28.485 ;
     RECT  2.16 28.755 41.04 29.025 ;
     RECT  2.16 29.295 41.04 29.565 ;
     RECT  2.16 29.835 41.04 30.105 ;
     RECT  2.16 30.375 41.04 30.645 ;
     RECT  2.16 30.915 41.04 31.185 ;
     RECT  2.16 31.455 41.04 31.725 ;
     RECT  2.16 31.995 41.04 32.265 ;
     RECT  2.16 32.535 41.04 32.805 ;
     RECT  2.16 33.075 41.04 33.345 ;
     RECT  2.16 33.615 41.04 33.885 ;
     RECT  2.16 34.155 41.04 34.425 ;
     RECT  2.16 34.695 41.04 34.965 ;
     RECT  2.16 35.235 41.04 35.505 ;
     RECT  2.16 35.775 41.04 36.045 ;
     RECT  2.16 36.315 41.04 36.585 ;
     RECT  2.16 36.855 41.04 37.125 ;
     RECT  2.16 37.395 41.04 37.665 ;
     RECT  2.16 37.935 41.04 38.205 ;
     RECT  2.16 38.475 41.04 38.745 ;
     RECT  2.16 39.015 41.04 39.285 ;
     RECT  2.16 39.555 41.04 39.825 ;
     RECT  2.16 40.095 41.04 40.365 ;
     RECT  2.16 40.635 41.04 40.905 ;
    LAYER M1 ;
     RECT  2.16 2.151 41.04 41.049 ;
    LAYER M2 ;
     RECT  0.103 5.31 0.139 5.328 ;
     RECT  0.103 23.904 0.175 24.66 ;
     RECT  0.103 25.758 0.175 25.776 ;
     RECT  0.103 19.278 0.203 19.368 ;
     RECT  0.175 23.904 0.203 25.776 ;
     RECT  0.139 8.244 0.275 8.262 ;
     RECT  0.103 26.64 0.347 26.658 ;
     RECT  0.103 28.26 0.347 28.278 ;
     RECT  0.103 29.502 0.347 29.52 ;
     RECT  0.103 9.054 0.499 9.072 ;
     RECT  0.499 7.236 0.535 7.254 ;
     RECT  0.103 12.87 0.535 12.888 ;
     RECT  0.499 13.644 0.535 13.662 ;
     RECT  0.103 17.964 1.723 17.982 ;
     RECT  1.723 16.074 1.759 16.092 ;
     RECT  1.759 16.074 1.795 16.398 ;
     RECT  0.139 5.31 2.16 5.868 ;
     RECT  0.535 6.696 2.16 7.254 ;
     RECT  0.499 8.28 2.16 9.072 ;
     RECT  0.499 10.98 2.16 10.998 ;
     RECT  0.535 12.87 2.16 13.662 ;
     RECT  1.759 15.192 2.16 15.21 ;
     RECT  1.795 16.074 2.16 16.866 ;
     RECT  1.723 17.766 2.16 17.982 ;
     RECT  0.203 19.35 2.16 19.368 ;
     RECT  0.535 22.086 2.16 22.104 ;
     RECT  0.203 23.904 2.16 25.038 ;
     RECT  1.723 30.312 2.16 30.33 ;
     RECT  2.16 2.151 12.343 41.049 ;
     RECT  12.343 2.106 14.279 41.049 ;
     RECT  14.279 2.151 20.803 41.049 ;
     RECT  20.803 2.034 22.819 41.049 ;
     RECT  22.819 1.962 22.855 41.049 ;
     RECT  22.855 1.881 26.339 41.049 ;
     RECT  26.339 2.151 40.099 41.049 ;
     RECT  40.099 2.151 40.415 41.094 ;
     RECT  40.415 2.151 41.04 41.049 ;
     RECT  41.04 28.836 41.063 37.386 ;
     RECT  41.063 30.312 41.423 31.914 ;
     RECT  41.063 32.85 41.639 37.386 ;
     RECT  41.04 27.18 41.891 27.324 ;
     RECT  41.063 28.836 41.927 29.484 ;
     RECT  41.639 32.886 41.927 37.386 ;
     RECT  41.927 35.748 41.999 37.386 ;
     RECT  41.04 38.25 42.035 39.546 ;
     RECT  41.999 35.748 42.071 37.116 ;
     RECT  41.927 28.836 42.179 29.394 ;
     RECT  41.423 30.312 42.179 31.824 ;
     RECT  42.071 35.784 42.179 37.116 ;
     RECT  41.891 27.306 42.215 27.324 ;
     RECT  41.927 32.886 42.215 34.614 ;
     RECT  42.179 30.312 42.251 31.554 ;
     RECT  42.215 33.246 42.359 34.614 ;
     RECT  42.251 30.312 43.043 31.41 ;
     RECT  42.035 38.718 43.043 39.546 ;
     RECT  42.359 33.246 43.079 33.3 ;
     RECT  42.359 34.398 43.079 34.614 ;
     RECT  43.043 30.312 43.115 30.6 ;
     RECT  43.043 31.392 43.115 31.41 ;
     RECT  43.079 33.282 43.115 33.3 ;
     RECT  43.079 34.398 43.115 34.524 ;
     RECT  42.179 35.784 43.115 36.846 ;
     RECT  43.043 38.718 43.115 39.312 ;
     RECT  42.179 28.836 43.151 28.854 ;
     RECT  43.115 38.718 43.151 38.772 ;
     RECT  43.115 30.312 43.187 30.33 ;
     RECT  43.115 34.506 43.187 34.524 ;
    LAYER M3 ;
     RECT  20.196 0.043 20.214 0.091 ;
     RECT  22.536 0.043 22.554 0.091 ;
     RECT  26.136 0.043 26.154 0.091 ;
     RECT  21.816 0.091 22.626 0.139 ;
     RECT  25.848 0.091 26.154 0.139 ;
     RECT  20.196 0.091 20.646 0.173 ;
     RECT  25.848 0.139 26.298 0.235 ;
     RECT  21.384 0.139 22.626 0.331 ;
     RECT  17.388 0.043 17.406 0.523 ;
     RECT  12.96 0.091 12.978 0.571 ;
     RECT  15.768 0.091 15.786 0.571 ;
     RECT  20.34 0.173 20.646 0.571 ;
     RECT  21.384 0.331 22.914 0.571 ;
     RECT  15.768 0.571 16.002 1.099 ;
     RECT  20.34 0.571 22.914 1.099 ;
     RECT  15.768 1.099 16.074 1.675 ;
     RECT  17.316 0.523 17.406 1.675 ;
     RECT  12.96 0.571 13.122 1.723 ;
     RECT  15.768 1.675 16.362 1.723 ;
     RECT  17.316 1.675 17.73 1.723 ;
     RECT  19.728 1.099 22.914 1.723 ;
     RECT  25.668 0.235 26.298 1.876 ;
     RECT  24.732 0.283 24.75 1.957 ;
     RECT  25.668 1.876 26.334 1.957 ;
     RECT  12.96 1.723 13.194 2.101 ;
     RECT  15.768 1.723 22.914 2.101 ;
     RECT  23.832 2.029 23.85 2.101 ;
     RECT  24.732 1.957 26.334 2.101 ;
     RECT  12.348 2.101 13.194 2.143 ;
     RECT  12.348 2.143 13.305 2.255 ;
     RECT  12.456 2.255 13.305 2.299 ;
     RECT  12.456 2.299 13.374 2.371 ;
     RECT  14.256 2.101 14.274 2.371 ;
     RECT  15.768 2.101 26.334 2.371 ;
     RECT  2.415 2.143 2.505 2.413 ;
     RECT  7.815 2.143 7.905 2.413 ;
     RECT  29.415 2.143 29.505 2.413 ;
     RECT  34.815 2.143 34.905 2.413 ;
     RECT  40.215 2.143 40.305 2.413 ;
     RECT  12.456 2.371 14.274 2.489 ;
     RECT  12.78 2.489 14.274 2.569 ;
     RECT  12.78 2.569 14.346 2.641 ;
     RECT  12.78 2.641 14.418 2.795 ;
     RECT  15.696 2.371 26.334 2.911 ;
     RECT  13.176 2.795 14.418 3.029 ;
     RECT  15.696 2.911 26.514 3.271 ;
     RECT  15.408 3.271 26.514 3.451 ;
     RECT  15.408 3.451 26.73 3.721 ;
     RECT  15.156 3.721 26.73 3.739 ;
     RECT  13.176 3.029 14.382 3.811 ;
     RECT  15.156 3.739 27.27 3.811 ;
     RECT  13.176 3.811 27.27 3.883 ;
     RECT  4.032 4.225 4.05 4.261 ;
     RECT  6.444 4.225 6.462 4.261 ;
     RECT  13.104 3.883 27.27 4.261 ;
     RECT  13.104 4.261 27.414 4.351 ;
     RECT  4.032 4.261 4.374 4.387 ;
     RECT  5.184 4.225 5.202 4.387 ;
     RECT  4.032 4.387 5.202 4.423 ;
     RECT  4.032 4.423 5.31 4.495 ;
     RECT  13.104 4.351 27.63 4.523 ;
     RECT  6.444 4.261 6.894 4.531 ;
     RECT  7.815 2.413 8.097 4.531 ;
     RECT  14.328 4.523 27.63 4.531 ;
     RECT  13.104 4.523 13.497 4.546 ;
     RECT  2.415 2.413 2.697 4.621 ;
     RECT  4.032 4.495 5.346 4.765 ;
     RECT  2.415 4.621 3.258 4.801 ;
     RECT  3.996 4.765 5.346 4.801 ;
     RECT  2.415 4.801 5.346 4.891 ;
     RECT  6.444 4.531 8.097 4.891 ;
     RECT  9 4.351 9.018 4.891 ;
     RECT  10.836 4.891 10.854 5.021 ;
     RECT  2.415 4.891 5.706 5.197 ;
     RECT  6.444 4.891 9.018 5.197 ;
     RECT  9.9 5.305 9.918 5.341 ;
     RECT  0.108 5.305 0.126 5.467 ;
     RECT  13.176 4.546 13.497 5.539 ;
     RECT  14.328 4.531 27.702 5.539 ;
     RECT  13.176 5.539 27.702 5.701 ;
     RECT  2.415 5.197 9.09 5.707 ;
     RECT  13.068 5.701 27.702 5.737 ;
     RECT  9.9 5.341 10.566 5.845 ;
     RECT  0.108 5.467 0.198 5.846 ;
     RECT  2.34 5.707 9.09 5.881 ;
     RECT  9.828 5.845 10.566 5.881 ;
     RECT  12.564 5.737 27.702 5.881 ;
     RECT  2.304 5.881 10.566 5.971 ;
     RECT  11.988 5.881 27.702 5.971 ;
     RECT  29.415 2.413 29.697 6.043 ;
     RECT  11.988 5.971 28.098 6.115 ;
     RECT  2.304 5.971 10.854 6.151 ;
     RECT  11.988 6.115 28.17 6.151 ;
     RECT  11.772 6.151 28.17 6.241 ;
     RECT  2.304 6.151 10.926 6.277 ;
     RECT  11.772 6.241 28.458 6.277 ;
     RECT  2.304 6.277 28.458 6.385 ;
     RECT  29.34 6.043 29.697 6.385 ;
     RECT  0.108 5.846 0.162 6.413 ;
     RECT  0.144 6.413 0.162 6.691 ;
     RECT  2.304 6.385 29.697 6.691 ;
     RECT  0.144 6.691 0.558 6.989 ;
     RECT  0.324 6.989 0.558 7.181 ;
     RECT  2.268 6.691 29.697 7.429 ;
     RECT  0.504 7.181 0.558 7.469 ;
     RECT  2.268 7.429 30.222 7.727 ;
     RECT  2.304 7.727 30.222 7.771 ;
     RECT  2.304 7.771 30.33 7.933 ;
     RECT  31.248 7.771 31.266 7.933 ;
     RECT  0.504 7.469 0.522 8.107 ;
     RECT  2.304 7.933 31.266 8.167 ;
     RECT  0.324 8.107 0.522 8.203 ;
     RECT  0.144 8.203 0.522 8.267 ;
     RECT  0.252 8.267 0.522 8.275 ;
     RECT  2.304 8.167 31.338 8.311 ;
     RECT  2.304 8.311 31.518 8.501 ;
     RECT  2.304 8.501 31.23 8.581 ;
     RECT  2.268 8.581 31.23 8.699 ;
     RECT  0.252 8.275 0.558 9.049 ;
     RECT  0.108 9.049 0.558 9.197 ;
     RECT  2.268 8.699 31.158 9.403 ;
     RECT  2.232 9.403 31.158 9.545 ;
     RECT  0.144 9.197 0.558 9.677 ;
     RECT  2.232 9.545 30.978 9.815 ;
     RECT  0.18 9.677 0.558 9.965 ;
     RECT  0.18 9.965 0.342 10.157 ;
     RECT  0.18 10.157 0.27 10.253 ;
     RECT  2.304 9.815 30.978 10.399 ;
     RECT  0.144 10.651 0.162 10.829 ;
     RECT  2.304 10.399 31.05 11.275 ;
     RECT  2.268 11.275 31.05 11.371 ;
     RECT  2.196 11.371 31.05 12.245 ;
     RECT  0.504 10.975 0.522 12.427 ;
     RECT  2.304 12.245 31.05 12.479 ;
     RECT  0.324 12.427 0.522 12.523 ;
     RECT  0.144 12.523 0.522 12.865 ;
     RECT  2.304 12.479 30.978 13.003 ;
     RECT  2.268 13.003 30.978 13.163 ;
     RECT  2.304 13.163 30.978 13.325 ;
     RECT  0.108 12.865 0.522 13.405 ;
     RECT  0.108 13.405 0.558 13.421 ;
     RECT  2.304 13.325 30.762 13.559 ;
     RECT  0.144 13.421 0.558 14.381 ;
     RECT  2.304 13.559 30.726 14.539 ;
     RECT  2.268 14.539 30.726 14.639 ;
     RECT  2.268 14.639 30.582 14.675 ;
     RECT  0.144 14.381 0.342 14.765 ;
     RECT  0.144 14.765 0.234 15.005 ;
     RECT  2.268 14.675 30.546 15.067 ;
     RECT  0.216 15.005 0.234 15.101 ;
     RECT  1.872 15.067 30.546 15.115 ;
     RECT  1.728 15.115 30.546 15.791 ;
     RECT  1.728 15.791 30.51 15.989 ;
     RECT  1.728 15.989 30.474 16.259 ;
     RECT  0.324 16.747 0.342 16.877 ;
     RECT  0.144 16.939 0.162 17.117 ;
     RECT  1.728 16.259 30.33 17.375 ;
     RECT  1.728 17.375 30.258 17.681 ;
     RECT  1.728 17.681 30.222 17.789 ;
     RECT  0.324 17.803 0.342 17.933 ;
     RECT  2.268 17.789 30.222 18.527 ;
     RECT  2.304 18.527 30.222 18.535 ;
     RECT  0.108 17.959 0.126 18.667 ;
     RECT  2.304 18.535 30.438 18.689 ;
     RECT  0.108 18.667 0.342 18.797 ;
     RECT  2.304 18.689 30.33 19.103 ;
     RECT  12.528 19.103 30.33 19.229 ;
     RECT  0.108 18.797 0.198 19.723 ;
     RECT  0.108 19.723 0.342 19.853 ;
     RECT  0.108 19.853 0.162 19.949 ;
     RECT  2.304 19.103 11.61 20.011 ;
     RECT  0.108 19.949 0.126 20.237 ;
     RECT  2.268 20.011 11.61 20.453 ;
     RECT  0.144 20.731 0.162 20.779 ;
     RECT  12.528 19.229 30.294 20.857 ;
     RECT  0.144 20.779 0.342 20.909 ;
     RECT  12.528 20.857 30.582 20.929 ;
     RECT  12.528 20.929 30.87 20.965 ;
     RECT  0.252 20.909 0.342 21.101 ;
     RECT  12.348 20.965 31.194 21.199 ;
     RECT  12.348 21.199 31.23 21.271 ;
     RECT  1.152 21.259 1.17 21.437 ;
     RECT  0.324 21.101 0.342 21.485 ;
     RECT  2.304 20.453 11.61 21.505 ;
     RECT  12.348 21.271 31.734 21.541 ;
     RECT  12.348 21.541 31.878 21.659 ;
     RECT  12.348 21.659 31.518 21.929 ;
     RECT  12.348 21.929 31.338 22.199 ;
     RECT  0.54 22.081 0.558 22.253 ;
     RECT  2.268 21.505 11.61 22.603 ;
     RECT  2.232 22.603 11.61 22.649 ;
     RECT  12.348 22.199 31.266 22.981 ;
     RECT  12.348 22.981 31.446 23.089 ;
     RECT  2.268 22.649 11.61 23.125 ;
     RECT  12.348 23.089 31.518 23.125 ;
     RECT  2.268 23.125 31.518 23.315 ;
     RECT  2.304 23.315 31.518 23.359 ;
     RECT  2.304 23.359 31.554 23.459 ;
     RECT  2.304 23.459 31.518 23.819 ;
     RECT  12.348 23.819 31.518 24.637 ;
     RECT  12.348 24.637 31.734 24.781 ;
     RECT  12.348 24.781 31.806 24.979 ;
     RECT  32.58 24.745 32.598 24.979 ;
     RECT  2.304 23.819 11.61 25.003 ;
     RECT  0.108 23.179 0.126 25.015 ;
     RECT  12.348 24.979 32.598 25.051 ;
     RECT  0.108 25.015 0.198 25.099 ;
     RECT  12.348 25.051 32.958 25.241 ;
     RECT  2.232 25.003 11.61 25.277 ;
     RECT  2.268 25.277 11.61 25.421 ;
     RECT  2.304 25.421 11.61 25.555 ;
     RECT  12.348 25.241 32.742 25.555 ;
     RECT  0.108 25.099 0.342 25.805 ;
     RECT  34.815 2.413 35.097 26.059 ;
     RECT  2.304 25.555 32.742 26.131 ;
     RECT  34.164 26.059 35.097 26.131 ;
     RECT  2.304 26.131 35.097 26.491 ;
     RECT  0.324 25.805 0.342 26.539 ;
     RECT  2.268 26.491 35.097 26.555 ;
     RECT  0.108 26.539 0.342 26.663 ;
     RECT  0.144 26.663 0.342 26.669 ;
     RECT  0.144 26.669 0.198 26.765 ;
     RECT  0.144 26.765 0.162 27.101 ;
     RECT  41.868 27.175 41.886 27.301 ;
     RECT  40.215 2.413 40.497 27.337 ;
     RECT  2.268 26.555 33.93 27.599 ;
     RECT  40.14 27.337 40.497 27.715 ;
     RECT  39.996 27.715 40.497 27.841 ;
     RECT  39.996 27.841 40.626 27.913 ;
     RECT  34.815 26.555 35.097 27.949 ;
     RECT  2.268 27.599 33.03 28.123 ;
     RECT  0.324 28.075 0.342 28.171 ;
     RECT  34.668 27.949 35.097 28.171 ;
     RECT  2.232 28.123 33.03 28.247 ;
     RECT  0.108 28.171 0.342 28.283 ;
     RECT  33.768 27.599 33.93 28.291 ;
     RECT  34.668 28.171 35.19 28.291 ;
     RECT  39.996 27.913 41.022 28.381 ;
     RECT  2.268 28.247 33.03 28.445 ;
     RECT  39.528 28.381 41.022 28.453 ;
     RECT  20.556 28.445 33.03 28.481 ;
     RECT  2.268 28.445 19.674 28.493 ;
     RECT  21.168 28.481 33.03 28.561 ;
     RECT  33.768 28.291 35.19 28.561 ;
     RECT  16.956 28.493 19.674 28.679 ;
     RECT  18.54 28.679 19.674 28.787 ;
     RECT  38.664 28.651 38.682 28.795 ;
     RECT  39.42 28.453 41.022 28.795 ;
     RECT  16.956 28.679 17.694 28.823 ;
     RECT  18.54 28.787 18.897 28.823 ;
     RECT  21.168 28.561 35.19 28.831 ;
     RECT  35.928 28.561 35.946 28.831 ;
     RECT  37.872 28.723 37.89 28.921 ;
     RECT  2.268 28.493 15.894 29.035 ;
     RECT  21.168 28.831 35.982 29.065 ;
     RECT  36.792 29.029 36.81 29.065 ;
     RECT  21.168 29.065 36.81 29.093 ;
     RECT  1.728 29.035 15.894 29.129 ;
     RECT  38.664 28.795 41.022 29.191 ;
     RECT  41.868 27.301 42.21 29.191 ;
     RECT  11.952 29.129 15.894 29.227 ;
     RECT  38.664 29.191 42.21 29.261 ;
     RECT  11.952 29.227 16.074 29.335 ;
     RECT  21.24 29.093 36.81 29.335 ;
     RECT  37.62 28.921 37.89 29.335 ;
     RECT  11.952 29.335 16.182 29.371 ;
     RECT  16.956 28.823 17.514 29.371 ;
     RECT  38.664 29.261 42.174 29.399 ;
     RECT  0.324 28.283 0.342 29.419 ;
     RECT  38.664 29.399 42.138 29.453 ;
     RECT  21.24 29.335 37.89 29.641 ;
     RECT  38.664 29.453 41.922 29.641 ;
     RECT  1.728 29.129 10.998 29.759 ;
     RECT  11.952 29.371 17.514 29.795 ;
     RECT  9.216 29.759 10.998 29.831 ;
     RECT  0.108 29.419 0.342 29.837 ;
     RECT  12.096 29.795 17.514 29.867 ;
     RECT  10.512 29.831 10.926 29.903 ;
     RECT  12.24 29.867 17.514 29.903 ;
     RECT  12.348 29.903 17.514 29.911 ;
     RECT  18.615 28.823 18.897 29.911 ;
     RECT  21.24 29.641 41.922 29.911 ;
     RECT  1.728 29.759 8.478 30.029 ;
     RECT  10.62 29.903 10.926 30.029 ;
     RECT  10.62 30.029 10.674 30.209 ;
     RECT  0.108 29.837 0.126 30.221 ;
     RECT  9.216 29.831 9.234 30.299 ;
     RECT  43.128 28.831 43.146 30.307 ;
     RECT  1.728 30.029 8.226 30.335 ;
     RECT  2.268 30.335 8.226 30.479 ;
     RECT  43.128 30.307 43.182 30.568 ;
     RECT  10.656 30.209 10.674 30.749 ;
     RECT  12.348 29.911 18.897 30.749 ;
     RECT  43.092 30.568 43.182 30.763 ;
     RECT  2.268 30.479 8.097 30.839 ;
     RECT  2.268 30.839 6.966 30.875 ;
     RECT  42.912 30.763 43.182 30.893 ;
     RECT  21.204 29.911 41.922 30.911 ;
     RECT  10.836 30.811 10.854 30.941 ;
     RECT  2.304 30.875 6.966 30.947 ;
     RECT  21.708 30.911 41.922 30.947 ;
     RECT  21.996 30.947 41.922 30.983 ;
     RECT  43.02 30.893 43.182 31.019 ;
     RECT  22.536 30.983 41.922 31.051 ;
     RECT  2.376 30.947 6.966 31.145 ;
     RECT  2.415 31.145 6.966 31.181 ;
     RECT  22.536 31.051 42.282 31.289 ;
     RECT  23.688 31.289 42.282 31.373 ;
     RECT  23.688 31.373 42.246 31.421 ;
     RECT  2.415 31.181 6.894 31.559 ;
     RECT  12.348 30.749 17.514 31.559 ;
     RECT  24.015 31.421 42.246 31.565 ;
     RECT  2.415 31.559 6.03 31.649 ;
     RECT  6.876 31.559 6.894 31.649 ;
     RECT  25.308 31.565 42.246 31.757 ;
     RECT  2.415 31.649 2.97 31.829 ;
     RECT  43.092 31.019 43.182 31.915 ;
     RECT  3.708 31.649 3.87 31.919 ;
     RECT  4.644 31.649 6.03 31.919 ;
     RECT  4.716 31.919 5.958 31.949 ;
     RECT  3.708 31.919 3.726 31.955 ;
     RECT  4.716 31.949 4.734 32 ;
     RECT  5.76 31.949 5.958 32.189 ;
     RECT  5.76 32.189 5.778 32.225 ;
     RECT  14.724 31.559 17.514 32.237 ;
     RECT  43.056 31.915 43.182 32.237 ;
     RECT  25.596 31.757 42.246 32.333 ;
     RECT  25.596 32.333 25.974 32.459 ;
     RECT  25.596 32.459 25.794 32.621 ;
     RECT  14.868 32.237 17.514 32.729 ;
     RECT  14.868 32.729 16.29 32.801 ;
     RECT  17.064 32.729 17.514 32.801 ;
     RECT  14.868 32.801 16.002 32.873 ;
     RECT  26.712 32.333 42.246 33.035 ;
     RECT  43.164 32.237 43.182 33.241 ;
     RECT  27 33.035 42.246 33.269 ;
     RECT  27.216 33.269 42.246 33.313 ;
     RECT  27.216 33.313 42.318 33.781 ;
     RECT  43.056 33.241 43.182 33.781 ;
     RECT  12.348 31.559 13.878 34.321 ;
     RECT  14.868 32.873 15.93 34.321 ;
     RECT  17.352 32.801 17.514 34.501 ;
     RECT  27.216 33.781 43.182 34.529 ;
     RECT  12.348 34.321 15.93 34.771 ;
     RECT  12.312 34.771 15.93 34.861 ;
     RECT  12.06 34.861 15.93 34.933 ;
     RECT  11.88 34.933 16.182 34.969 ;
     RECT  27.216 34.529 43.11 34.973 ;
     RECT  27.216 34.973 42.318 35.005 ;
     RECT  10.908 34.969 10.926 35.041 ;
     RECT  11.808 34.969 16.182 35.041 ;
     RECT  27.072 35.005 42.318 35.117 ;
     RECT  27.072 35.117 42.246 35.213 ;
     RECT  10.8 35.041 16.182 35.239 ;
     RECT  10.692 35.239 16.182 35.275 ;
     RECT  10.08 35.275 16.182 35.581 ;
     RECT  16.92 34.501 17.514 35.581 ;
     RECT  10.008 35.581 17.514 35.707 ;
     RECT  9.828 35.707 17.514 35.779 ;
     RECT  27.072 35.213 42.066 35.779 ;
     RECT  26.568 35.779 42.066 35.947 ;
     RECT  9.684 35.779 17.514 36.049 ;
     RECT  25.596 32.621 25.614 36.121 ;
     RECT  7.815 30.839 8.097 36.355 ;
     RECT  9.504 36.049 17.514 36.355 ;
     RECT  25.092 36.121 25.614 36.419 ;
     RECT  7.815 36.355 17.514 36.823 ;
     RECT  43.092 34.973 43.11 36.941 ;
     RECT  7.815 36.823 17.622 37.051 ;
     RECT  7.812 37.051 17.622 37.057 ;
     RECT  26.568 35.947 42.174 37.121 ;
     RECT  26.568 37.121 42.03 37.229 ;
     RECT  7.272 37.057 17.622 37.625 ;
     RECT  25.596 36.419 25.614 37.633 ;
     RECT  26.568 37.229 41.994 37.633 ;
     RECT  19.656 28.787 19.674 37.769 ;
     RECT  25.596 37.633 41.994 38.245 ;
     RECT  25.596 38.245 42.03 38.749 ;
     RECT  43.128 38.713 43.146 38.749 ;
     RECT  43.056 38.749 43.146 38.777 ;
     RECT  25.524 38.749 42.03 38.983 ;
     RECT  25.524 38.983 42.21 39.055 ;
     RECT  25.524 39.055 42.246 39.217 ;
     RECT  25.308 39.217 42.246 39.289 ;
     RECT  25.128 39.289 42.246 39.355 ;
     RECT  43.056 38.777 43.11 39.361 ;
     RECT  7.416 37.625 17.622 39.595 ;
     RECT  24.015 31.565 24.297 39.595 ;
     RECT  25.02 39.355 42.246 39.595 ;
     RECT  7.128 39.595 17.622 39.631 ;
     RECT  7.02 39.631 17.622 39.749 ;
     RECT  24.015 39.595 42.246 39.821 ;
     RECT  43.02 39.361 43.11 40.013 ;
     RECT  7.416 39.749 17.622 40.127 ;
     RECT  7.452 40.127 17.622 40.199 ;
     RECT  7.524 40.199 17.622 40.289 ;
     RECT  24.015 39.821 42.174 40.289 ;
     RECT  43.056 40.013 43.11 40.589 ;
     RECT  7.524 40.289 17.226 40.595 ;
     RECT  7.524 40.595 17.046 40.631 ;
     RECT  24.015 40.289 40.554 40.667 ;
     RECT  24.015 40.667 36.918 40.675 ;
     RECT  23.94 40.675 36.918 40.685 ;
     RECT  41.292 40.289 42.174 40.685 ;
     RECT  7.524 40.631 14.382 40.739 ;
     RECT  15.156 40.631 17.046 40.739 ;
     RECT  2.415 31.829 2.697 40.787 ;
     RECT  18.615 30.749 18.897 40.787 ;
     RECT  15.336 40.739 17.046 40.829 ;
     RECT  23.94 40.685 33.138 40.829 ;
     RECT  33.876 40.685 36.918 40.829 ;
     RECT  37.8 40.667 40.554 40.829 ;
     RECT  16.452 40.829 16.506 40.865 ;
     RECT  37.98 40.829 39.186 40.877 ;
     RECT  42.912 40.747 42.93 40.877 ;
     RECT  16.488 40.865 16.506 40.901 ;
     RECT  7.524 40.739 14.202 40.937 ;
     RECT  33.048 40.829 33.066 40.937 ;
     RECT  34.056 40.829 36.918 40.937 ;
     RECT  37.98 40.877 38.826 40.973 ;
     RECT  41.292 40.685 41.958 40.973 ;
     RECT  23.94 40.829 30.33 40.981 ;
     RECT  7.524 40.937 14.13 41.009 ;
     RECT  31.248 40.829 31.338 41.009 ;
     RECT  34.056 40.937 34.074 41.009 ;
     RECT  37.98 40.973 38.25 41.009 ;
     RECT  40.104 40.829 40.554 41.009 ;
     RECT  7.524 41.009 10.422 41.021 ;
     RECT  31.248 41.009 31.266 41.021 ;
     RECT  11.268 41.009 11.322 41.032 ;
     RECT  2.415 40.787 2.505 41.057 ;
     RECT  18.615 40.787 18.705 41.057 ;
     RECT  34.815 40.937 36.918 41.057 ;
     RECT  40.104 41.009 40.41 41.099 ;
     RECT  35.352 41.057 36.918 41.117 ;
     RECT  40.104 41.099 40.122 41.117 ;
     RECT  23.868 40.981 30.33 41.165 ;
     RECT  12.06 41.009 14.13 41.213 ;
     RECT  12.06 41.213 13.374 41.261 ;
     RECT  38.232 41.009 38.25 41.261 ;
     RECT  41.292 40.973 41.922 41.549 ;
     RECT  7.524 41.021 9.738 41.597 ;
     RECT  7.524 41.597 8.622 41.645 ;
     RECT  12.06 41.261 12.978 41.645 ;
     RECT  23.868 41.165 29.286 41.645 ;
     RECT  35.748 41.117 36.918 41.741 ;
     RECT  36.54 41.741 36.918 41.837 ;
     RECT  36.54 41.837 36.558 41.933 ;
     RECT  35.748 41.741 35.766 42.029 ;
     RECT  41.292 41.549 41.31 42.125 ;
     RECT  7.776 41.645 8.622 42.173 ;
     RECT  27.936 41.645 29.286 42.173 ;
     RECT  7.776 42.173 7.794 42.221 ;
     RECT  9.684 41.597 9.738 42.221 ;
     RECT  11.304 41.032 11.322 42.221 ;
     RECT  23.868 41.645 26.658 42.221 ;
     RECT  28.584 42.173 29.286 42.221 ;
     RECT  24.264 42.221 25.902 42.269 ;
     RECT  9.72 42.221 9.738 42.317 ;
     RECT  24.264 42.269 25.542 42.317 ;
     RECT  30.312 41.165 30.33 42.941 ;
     RECT  8.604 42.173 8.622 43.085 ;
     RECT  12.06 41.645 12.078 43.085 ;
     RECT  14.112 41.213 14.13 43.085 ;
     RECT  24.264 42.317 24.282 43.085 ;
     RECT  25.02 42.317 25.542 43.085 ;
     RECT  26.64 42.221 26.658 43.085 ;
    LAYER M4 ;
     RECT  0.084 5.616 0.097 5.64 ;
     RECT  0.06 5.64 0.097 5.712 ;
     RECT  0.084 5.712 0.097 5.736 ;
     RECT  0.06 5.736 0.097 5.808 ;
     RECT  0.084 5.808 0.097 5.832 ;
     RECT  0.06 5.832 0.097 5.904 ;
     RECT  0.084 5.904 0.097 5.928 ;
     RECT  0.06 5.928 0.097 6 ;
     RECT  0.084 6 0.097 6.024 ;
     RECT  0.06 6.024 0.097 6.096 ;
     RECT  0.084 6.096 0.097 6.12 ;
     RECT  0.06 6.12 0.097 6.192 ;
     RECT  0.084 6.192 0.097 6.216 ;
     RECT  0.06 6.216 0.097 6.288 ;
     RECT  0.084 6.288 0.097 6.312 ;
     RECT  0.06 6.312 0.097 6.384 ;
     RECT  0.084 6.384 0.097 6.408 ;
     RECT  0.06 6.408 0.097 6.48 ;
     RECT  0.084 6.48 0.097 6.504 ;
     RECT  0.06 6.504 0.097 6.576 ;
     RECT  0.084 6.576 0.097 6.6 ;
     RECT  0.06 6.6 0.097 6.672 ;
     RECT  0.084 6.672 0.097 6.696 ;
     RECT  0.06 6.696 0.097 6.768 ;
     RECT  0.084 6.768 0.097 6.792 ;
     RECT  0.06 6.792 0.097 6.864 ;
     RECT  0.084 6.864 0.097 6.888 ;
     RECT  0.06 6.888 0.097 6.96 ;
     RECT  0.084 6.96 0.097 6.984 ;
     RECT  0.06 6.984 0.097 7.056 ;
     RECT  0.084 7.056 0.097 7.08 ;
     RECT  0.06 7.08 0.097 7.152 ;
     RECT  0.084 7.152 0.097 7.176 ;
     RECT  0.06 7.176 0.097 7.248 ;
     RECT  0.084 7.248 0.097 7.272 ;
     RECT  0.06 7.272 0.097 7.344 ;
     RECT  0.084 7.344 0.097 7.368 ;
     RECT  0.06 7.368 0.097 7.44 ;
     RECT  0.084 7.44 0.097 7.464 ;
     RECT  0.06 7.464 0.097 7.536 ;
     RECT  0.084 7.536 0.097 7.56 ;
     RECT  0.06 7.56 0.097 7.632 ;
     RECT  0.084 7.632 0.097 7.656 ;
     RECT  0.06 7.656 0.097 7.728 ;
     RECT  0.084 7.728 0.097 7.752 ;
     RECT  0.06 7.752 0.097 7.824 ;
     RECT  0.084 7.824 0.097 7.848 ;
     RECT  0.06 7.848 0.097 7.92 ;
     RECT  0.084 7.92 0.097 7.944 ;
     RECT  0.06 7.944 0.097 8.016 ;
     RECT  0.084 8.016 0.097 8.04 ;
     RECT  0.06 8.04 0.097 8.112 ;
     RECT  0.084 8.112 0.097 8.136 ;
     RECT  0.06 8.136 0.097 8.208 ;
     RECT  0.084 8.208 0.097 8.232 ;
     RECT  0.06 8.232 0.097 8.304 ;
     RECT  0.084 8.304 0.097 8.328 ;
     RECT  0.06 8.328 0.097 8.4 ;
     RECT  0.084 8.4 0.097 8.424 ;
     RECT  0.06 8.424 0.097 8.496 ;
     RECT  0.084 8.496 0.097 8.52 ;
     RECT  0.06 8.52 0.097 8.592 ;
     RECT  0.084 8.592 0.097 8.616 ;
     RECT  0.06 8.616 0.097 8.688 ;
     RECT  0.084 8.688 0.097 8.712 ;
     RECT  0.06 8.712 0.097 8.784 ;
     RECT  0.084 8.784 0.097 8.808 ;
     RECT  0.06 8.808 0.097 8.88 ;
     RECT  0.084 8.88 0.097 8.904 ;
     RECT  0.06 8.904 0.097 8.976 ;
     RECT  0.084 8.976 0.097 9 ;
     RECT  0.06 9 0.097 9.072 ;
     RECT  0.084 9.072 0.097 9.096 ;
     RECT  0.06 9.096 0.097 9.168 ;
     RECT  0.084 9.168 0.097 9.192 ;
     RECT  0.06 9.192 0.097 9.264 ;
     RECT  0.084 9.264 0.097 9.288 ;
     RECT  0.06 9.288 0.097 9.36 ;
     RECT  0.084 9.36 0.097 9.384 ;
     RECT  0.06 9.384 0.097 9.456 ;
     RECT  0.084 9.456 0.097 9.48 ;
     RECT  0.06 9.48 0.097 9.552 ;
     RECT  0.084 9.552 0.097 9.576 ;
     RECT  0.06 9.576 0.097 9.648 ;
     RECT  0.084 9.648 0.097 9.672 ;
     RECT  0.06 9.672 0.097 9.744 ;
     RECT  0.084 9.744 0.097 9.768 ;
     RECT  0.06 9.768 0.097 9.84 ;
     RECT  0.084 9.84 0.097 9.864 ;
     RECT  0.06 9.864 0.097 9.936 ;
     RECT  0.084 9.936 0.097 9.96 ;
     RECT  0.06 9.96 0.097 10.032 ;
     RECT  0.084 10.032 0.097 10.056 ;
     RECT  0.06 10.056 0.097 10.128 ;
     RECT  0.084 10.128 0.097 10.152 ;
     RECT  0.06 10.152 0.097 10.224 ;
     RECT  0.084 10.224 0.097 10.248 ;
     RECT  0.06 10.248 0.097 10.32 ;
     RECT  0.084 10.32 0.097 10.344 ;
     RECT  0.06 10.344 0.097 10.416 ;
     RECT  0.084 10.416 0.097 10.44 ;
     RECT  0.06 10.44 0.097 10.512 ;
     RECT  0.084 10.512 0.097 10.536 ;
     RECT  0.06 10.536 0.097 10.608 ;
     RECT  0.084 10.608 0.097 10.632 ;
     RECT  0.06 10.632 0.097 10.704 ;
     RECT  0.084 10.704 0.097 10.728 ;
     RECT  0.06 10.728 0.097 10.8 ;
     RECT  0.084 10.8 0.097 10.824 ;
     RECT  0.06 10.824 0.097 10.896 ;
     RECT  0.084 10.896 0.097 10.92 ;
     RECT  0.06 10.92 0.097 10.992 ;
     RECT  0.084 10.992 0.097 11.016 ;
     RECT  0.06 11.016 0.097 11.088 ;
     RECT  0.084 11.088 0.097 11.112 ;
     RECT  0.06 11.112 0.097 11.184 ;
     RECT  0.084 11.184 0.097 11.208 ;
     RECT  0.06 11.208 0.097 11.28 ;
     RECT  0.084 11.28 0.097 11.304 ;
     RECT  0.06 11.304 0.097 11.376 ;
     RECT  0.084 11.376 0.097 11.4 ;
     RECT  0.06 11.4 0.097 11.472 ;
     RECT  0.084 11.472 0.097 11.496 ;
     RECT  0.06 11.496 0.097 11.568 ;
     RECT  0.084 11.568 0.097 11.592 ;
     RECT  0.06 11.592 0.097 11.664 ;
     RECT  0.084 11.664 0.097 11.688 ;
     RECT  0.06 11.688 0.097 11.76 ;
     RECT  0.084 11.76 0.097 11.784 ;
     RECT  0.06 11.784 0.097 11.856 ;
     RECT  0.084 11.856 0.097 11.88 ;
     RECT  0.06 11.88 0.097 11.952 ;
     RECT  0.084 11.952 0.097 11.976 ;
     RECT  0.06 11.976 0.097 12.048 ;
     RECT  0.084 12.048 0.097 12.072 ;
     RECT  0.06 12.072 0.097 12.144 ;
     RECT  0.084 12.144 0.097 12.168 ;
     RECT  0.06 12.168 0.097 12.24 ;
     RECT  0.084 12.24 0.097 12.264 ;
     RECT  0.06 12.264 0.097 12.336 ;
     RECT  0.084 12.336 0.097 12.36 ;
     RECT  0.06 12.36 0.097 12.432 ;
     RECT  0.084 12.432 0.097 12.456 ;
     RECT  0.06 12.456 0.097 12.528 ;
     RECT  0.084 12.528 0.097 12.552 ;
     RECT  0.06 12.552 0.097 12.624 ;
     RECT  0.084 12.624 0.097 12.648 ;
     RECT  0.06 12.648 0.097 12.72 ;
     RECT  0.084 12.72 0.097 12.744 ;
     RECT  0.06 12.744 0.097 12.816 ;
     RECT  0.084 12.816 0.097 12.84 ;
     RECT  0.06 12.84 0.097 12.912 ;
     RECT  0.084 12.912 0.097 12.936 ;
     RECT  0.06 12.936 0.097 13.008 ;
     RECT  0.084 13.008 0.097 13.032 ;
     RECT  0.06 13.032 0.097 13.104 ;
     RECT  0.084 13.104 0.097 13.128 ;
     RECT  0.06 13.128 0.097 13.2 ;
     RECT  0.084 13.2 0.097 13.224 ;
     RECT  0.06 13.224 0.097 13.296 ;
     RECT  0.084 13.296 0.097 13.32 ;
     RECT  0.06 13.32 0.097 13.392 ;
     RECT  0.084 13.392 0.097 13.416 ;
     RECT  0.06 13.416 0.097 13.488 ;
     RECT  0.084 13.488 0.097 13.512 ;
     RECT  0.06 13.512 0.097 13.584 ;
     RECT  0.084 13.584 0.097 13.608 ;
     RECT  0.06 13.608 0.097 13.68 ;
     RECT  0.084 13.68 0.097 13.704 ;
     RECT  0.06 13.704 0.097 13.776 ;
     RECT  0.084 13.776 0.097 13.8 ;
     RECT  0.06 13.8 0.097 13.872 ;
     RECT  0.084 13.872 0.097 13.896 ;
     RECT  0.06 13.896 0.097 13.968 ;
     RECT  0.084 13.968 0.097 13.992 ;
     RECT  0.06 13.992 0.097 14.064 ;
     RECT  0.084 14.064 0.097 14.088 ;
     RECT  0.06 14.088 0.097 14.16 ;
     RECT  0.084 14.16 0.097 14.184 ;
     RECT  0.06 14.184 0.097 14.256 ;
     RECT  0.084 14.256 0.097 14.28 ;
     RECT  0.06 14.28 0.097 14.352 ;
     RECT  0.084 14.352 0.097 14.376 ;
     RECT  0.06 14.376 0.097 14.448 ;
     RECT  0.084 14.448 0.097 14.472 ;
     RECT  0.06 14.472 0.097 14.544 ;
     RECT  0.084 14.544 0.097 14.568 ;
     RECT  0.06 14.568 0.097 14.64 ;
     RECT  0.084 14.64 0.097 14.664 ;
     RECT  0.06 14.664 0.097 14.736 ;
     RECT  0.084 14.736 0.097 14.76 ;
     RECT  0.06 14.76 0.097 14.832 ;
     RECT  0.084 14.832 0.097 14.856 ;
     RECT  0.06 14.856 0.097 14.928 ;
     RECT  0.084 14.928 0.097 14.952 ;
     RECT  0.06 14.952 0.097 15.024 ;
     RECT  0.084 15.024 0.097 15.048 ;
     RECT  0.06 15.048 0.097 15.12 ;
     RECT  0.084 15.12 0.097 15.144 ;
     RECT  0.06 15.144 0.097 15.216 ;
     RECT  0.084 15.216 0.097 15.24 ;
     RECT  0.06 15.24 0.097 15.312 ;
     RECT  0.084 15.312 0.097 15.336 ;
     RECT  0.06 15.336 0.097 15.408 ;
     RECT  0.084 15.408 0.097 15.432 ;
     RECT  0.06 15.432 0.097 15.504 ;
     RECT  0.084 15.504 0.097 15.528 ;
     RECT  0.06 15.528 0.097 15.6 ;
     RECT  0.084 15.6 0.097 15.624 ;
     RECT  0.06 15.624 0.097 15.696 ;
     RECT  0.084 15.696 0.097 15.72 ;
     RECT  0.06 15.72 0.097 15.792 ;
     RECT  0.084 15.792 0.097 15.816 ;
     RECT  0.06 15.816 0.097 15.888 ;
     RECT  0.084 15.888 0.097 15.912 ;
     RECT  0.06 15.912 0.097 15.984 ;
     RECT  0.084 15.984 0.097 16.008 ;
     RECT  0.06 16.008 0.097 16.08 ;
     RECT  0.084 16.08 0.097 16.104 ;
     RECT  0.06 16.104 0.097 16.176 ;
     RECT  0.084 16.176 0.097 16.2 ;
     RECT  0.06 16.2 0.097 16.272 ;
     RECT  0.084 16.272 0.097 16.296 ;
     RECT  0.06 16.296 0.097 16.368 ;
     RECT  0.084 16.368 0.097 16.392 ;
     RECT  0.06 16.392 0.097 16.464 ;
     RECT  0.084 16.464 0.097 16.488 ;
     RECT  0.06 16.488 0.097 16.56 ;
     RECT  0.084 16.56 0.097 16.584 ;
     RECT  0.06 16.584 0.097 16.656 ;
     RECT  0.084 16.656 0.097 16.68 ;
     RECT  0.06 16.68 0.097 16.752 ;
     RECT  0.084 16.752 0.097 16.776 ;
     RECT  0.06 16.776 0.097 16.848 ;
     RECT  0.084 16.848 0.097 16.872 ;
     RECT  0.06 16.872 0.097 16.944 ;
     RECT  0.084 16.944 0.097 16.968 ;
     RECT  0.06 16.968 0.097 17.04 ;
     RECT  0.084 17.04 0.097 17.064 ;
     RECT  0.06 17.064 0.097 17.136 ;
     RECT  0.084 17.136 0.097 17.16 ;
     RECT  0.06 17.16 0.097 17.232 ;
     RECT  0.084 17.232 0.097 17.256 ;
     RECT  0.06 17.256 0.097 17.328 ;
     RECT  0.084 17.328 0.097 17.352 ;
     RECT  0.06 17.352 0.097 17.424 ;
     RECT  0.084 17.424 0.097 17.448 ;
     RECT  0.06 17.448 0.097 17.52 ;
     RECT  0.084 17.52 0.097 17.544 ;
     RECT  0.06 17.544 0.097 17.616 ;
     RECT  0.084 17.616 0.097 17.64 ;
     RECT  0.06 17.64 0.097 17.712 ;
     RECT  0.084 17.712 0.097 17.736 ;
     RECT  0.06 17.736 0.097 17.808 ;
     RECT  0.084 17.808 0.097 17.832 ;
     RECT  0.06 17.832 0.097 17.904 ;
     RECT  0.084 17.904 0.097 17.928 ;
     RECT  0.06 17.928 0.097 18 ;
     RECT  0.084 18 0.097 18.024 ;
     RECT  0.06 18.024 0.097 18.096 ;
     RECT  0.084 18.096 0.097 18.12 ;
     RECT  0.06 18.12 0.097 18.192 ;
     RECT  0.084 18.192 0.097 18.216 ;
     RECT  0.06 18.216 0.097 18.288 ;
     RECT  0.084 18.288 0.097 18.312 ;
     RECT  0.06 18.312 0.097 18.384 ;
     RECT  0.084 18.384 0.097 18.408 ;
     RECT  0.06 18.408 0.097 18.48 ;
     RECT  0.084 18.48 0.097 18.504 ;
     RECT  0.06 18.504 0.097 18.576 ;
     RECT  0.084 18.576 0.097 18.6 ;
     RECT  0.06 18.6 0.097 18.672 ;
     RECT  0.084 18.672 0.097 18.696 ;
     RECT  0.06 18.696 0.097 18.768 ;
     RECT  0.084 18.768 0.097 18.792 ;
     RECT  0.06 18.792 0.097 18.864 ;
     RECT  0.084 18.864 0.097 18.888 ;
     RECT  0.06 18.888 0.097 18.96 ;
     RECT  0.084 18.96 0.097 18.984 ;
     RECT  0.06 18.984 0.097 19.056 ;
     RECT  0.084 19.056 0.097 19.08 ;
     RECT  0.06 19.08 0.097 19.152 ;
     RECT  0.084 19.152 0.097 19.176 ;
     RECT  0.06 19.176 0.097 19.248 ;
     RECT  0.084 19.248 0.097 19.272 ;
     RECT  0.06 19.272 0.097 19.344 ;
     RECT  0.084 19.344 0.097 19.368 ;
     RECT  0.06 19.368 0.097 19.44 ;
     RECT  0.084 19.44 0.097 19.464 ;
     RECT  0.06 19.464 0.097 19.536 ;
     RECT  0.084 19.536 0.097 19.56 ;
     RECT  0.06 19.56 0.097 19.632 ;
     RECT  0.084 19.632 0.097 19.656 ;
     RECT  0.06 19.656 0.097 19.728 ;
     RECT  0.084 19.728 0.097 19.752 ;
     RECT  0.06 19.752 0.097 19.824 ;
     RECT  0.084 19.824 0.097 19.848 ;
     RECT  0.06 19.848 0.097 19.92 ;
     RECT  0.084 19.92 0.097 19.944 ;
     RECT  0.06 19.944 0.097 20.016 ;
     RECT  0.084 20.016 0.097 20.04 ;
     RECT  0.06 20.04 0.097 20.112 ;
     RECT  0.084 20.112 0.097 20.136 ;
     RECT  0.06 20.136 0.097 20.208 ;
     RECT  0.084 20.208 0.097 20.232 ;
     RECT  0.06 20.232 0.097 20.304 ;
     RECT  0.084 20.304 0.097 20.328 ;
     RECT  0.06 20.328 0.097 20.4 ;
     RECT  0.084 20.4 0.097 20.424 ;
     RECT  0.06 20.424 0.097 20.496 ;
     RECT  0.084 20.496 0.097 20.52 ;
     RECT  0.06 20.52 0.097 20.592 ;
     RECT  0.084 20.592 0.097 20.616 ;
     RECT  0.06 20.616 0.097 20.688 ;
     RECT  0.084 20.688 0.097 20.712 ;
     RECT  0.06 20.712 0.097 20.784 ;
     RECT  0.084 20.784 0.097 20.808 ;
     RECT  0.06 20.808 0.097 20.88 ;
     RECT  0.084 20.88 0.097 20.904 ;
     RECT  0.06 20.904 0.097 20.976 ;
     RECT  0.084 20.976 0.097 21 ;
     RECT  0.06 21 0.097 21.072 ;
     RECT  0.084 21.072 0.097 21.096 ;
     RECT  0.06 21.096 0.097 21.168 ;
     RECT  0.084 21.168 0.097 21.192 ;
     RECT  0.06 21.192 0.097 21.264 ;
     RECT  0.084 21.264 0.097 21.288 ;
     RECT  0.06 21.288 0.097 21.36 ;
     RECT  0.084 21.36 0.097 21.384 ;
     RECT  0.06 21.384 0.097 21.456 ;
     RECT  0.084 21.456 0.097 21.48 ;
     RECT  0.06 21.48 0.097 21.552 ;
     RECT  0.084 21.552 0.097 21.576 ;
     RECT  0.06 21.576 0.097 21.648 ;
     RECT  0.084 21.648 0.097 21.672 ;
     RECT  0.06 21.672 0.097 21.744 ;
     RECT  0.084 21.744 0.097 21.768 ;
     RECT  0.06 21.768 0.097 21.84 ;
     RECT  0.084 21.84 0.097 21.864 ;
     RECT  0.06 21.864 0.097 21.936 ;
     RECT  0.084 21.936 0.097 21.96 ;
     RECT  0.06 21.96 0.097 22.032 ;
     RECT  0.084 22.032 0.097 22.056 ;
     RECT  0.06 22.056 0.097 22.128 ;
     RECT  0.084 22.128 0.097 22.152 ;
     RECT  0.06 22.152 0.097 22.224 ;
     RECT  0.084 22.224 0.097 22.248 ;
     RECT  0.06 22.248 0.097 22.32 ;
     RECT  0.084 22.32 0.097 22.344 ;
     RECT  0.06 22.344 0.097 22.416 ;
     RECT  0.084 22.416 0.097 22.44 ;
     RECT  0.06 22.44 0.097 22.512 ;
     RECT  0.084 22.512 0.097 22.536 ;
     RECT  0.06 22.536 0.097 22.608 ;
     RECT  0.084 22.608 0.097 22.632 ;
     RECT  0.06 22.632 0.097 22.704 ;
     RECT  0.084 22.704 0.097 22.728 ;
     RECT  0.06 22.728 0.097 22.8 ;
     RECT  0.084 22.8 0.097 22.824 ;
     RECT  0.06 22.824 0.097 22.896 ;
     RECT  0.084 22.896 0.097 22.92 ;
     RECT  0.06 22.92 0.097 22.992 ;
     RECT  0.084 22.992 0.097 23.016 ;
     RECT  0.06 23.016 0.097 23.088 ;
     RECT  0.084 23.088 0.097 23.112 ;
     RECT  0.06 23.112 0.097 23.184 ;
     RECT  0.084 23.184 0.097 23.208 ;
     RECT  0.06 23.208 0.097 24.048 ;
     RECT  0.084 24.048 0.097 24.072 ;
     RECT  0.06 24.072 0.097 24.144 ;
     RECT  0.084 24.144 0.097 24.168 ;
     RECT  0.06 24.168 0.097 24.24 ;
     RECT  0.084 24.24 0.097 24.264 ;
     RECT  0.06 24.264 0.097 24.336 ;
     RECT  0.084 24.336 0.097 24.36 ;
     RECT  0.06 24.36 0.097 24.432 ;
     RECT  0.084 24.432 0.097 24.456 ;
     RECT  0.06 24.456 0.097 24.528 ;
     RECT  0.084 24.528 0.097 24.552 ;
     RECT  0.06 24.552 0.097 24.624 ;
     RECT  0.084 24.624 0.097 24.648 ;
     RECT  0.06 24.648 0.097 24.72 ;
     RECT  0.084 24.72 0.097 24.744 ;
     RECT  0.06 24.744 0.097 24.816 ;
     RECT  0.084 24.816 0.097 24.84 ;
     RECT  0.06 24.84 0.097 24.912 ;
     RECT  0.084 24.912 0.097 24.936 ;
     RECT  0.06 24.936 0.097 25.008 ;
     RECT  0.084 25.008 0.097 25.032 ;
     RECT  0.06 25.032 0.097 25.104 ;
     RECT  0.084 25.104 0.097 25.128 ;
     RECT  0.06 25.128 0.097 25.2 ;
     RECT  0.084 25.2 0.097 25.224 ;
     RECT  0.06 25.224 0.097 25.296 ;
     RECT  0.084 25.296 0.097 25.32 ;
     RECT  0.06 25.32 0.097 25.392 ;
     RECT  0.084 25.392 0.097 25.416 ;
     RECT  0.06 25.416 0.097 25.488 ;
     RECT  0.084 25.488 0.097 25.512 ;
     RECT  0.06 25.512 0.097 25.584 ;
     RECT  0.084 25.584 0.097 25.608 ;
     RECT  0.06 25.608 0.097 25.68 ;
     RECT  0.084 25.68 0.097 25.704 ;
     RECT  0.06 25.704 0.097 25.776 ;
     RECT  0.084 25.776 0.097 25.8 ;
     RECT  0.06 25.8 0.097 25.872 ;
     RECT  0.084 25.872 0.097 25.896 ;
     RECT  0.06 25.896 0.097 25.968 ;
     RECT  0.084 25.968 0.097 25.992 ;
     RECT  0.06 25.992 0.097 26.064 ;
     RECT  0.084 26.064 0.097 26.088 ;
     RECT  0.06 26.088 0.097 26.16 ;
     RECT  0.084 26.16 0.097 26.184 ;
     RECT  0.06 26.184 0.097 26.256 ;
     RECT  0.084 26.256 0.097 26.28 ;
     RECT  0.06 26.28 0.097 26.352 ;
     RECT  0.084 26.352 0.097 26.376 ;
     RECT  0.06 26.376 0.097 26.448 ;
     RECT  0.084 26.448 0.097 26.472 ;
     RECT  0.06 26.472 0.097 26.544 ;
     RECT  0.084 26.544 0.097 26.568 ;
     RECT  0.06 26.568 0.097 26.64 ;
     RECT  0.084 26.64 0.097 26.664 ;
     RECT  0.06 26.664 0.097 26.736 ;
     RECT  0.084 26.736 0.097 26.76 ;
     RECT  0.06 26.76 0.097 26.832 ;
     RECT  0.084 26.832 0.097 26.856 ;
     RECT  0.06 26.856 0.097 26.928 ;
     RECT  0.084 26.928 0.097 26.952 ;
     RECT  0.06 26.952 0.097 27.024 ;
     RECT  0.084 27.024 0.097 27.048 ;
     RECT  0.06 27.048 0.097 27.12 ;
     RECT  0.084 27.12 0.097 27.144 ;
     RECT  0.06 27.144 0.097 27.216 ;
     RECT  0.084 27.216 0.097 27.24 ;
     RECT  0.06 27.24 0.097 27.312 ;
     RECT  0.084 27.312 0.097 27.336 ;
     RECT  0.06 27.336 0.097 27.408 ;
     RECT  0.084 27.408 0.097 27.432 ;
     RECT  0.06 27.432 0.097 27.504 ;
     RECT  0.084 27.504 0.097 27.528 ;
     RECT  0.06 27.528 0.097 27.6 ;
     RECT  0.084 27.6 0.097 27.624 ;
     RECT  0.06 27.624 0.097 27.696 ;
     RECT  0.084 27.696 0.097 27.72 ;
     RECT  0.06 27.72 0.097 27.792 ;
     RECT  0.084 27.792 0.097 27.816 ;
     RECT  0.06 27.816 0.097 27.888 ;
     RECT  0.084 27.888 0.097 27.912 ;
     RECT  0.06 27.912 0.097 27.984 ;
     RECT  0.084 27.984 0.097 28.008 ;
     RECT  0.06 28.008 0.097 28.08 ;
     RECT  0.084 28.08 0.097 28.104 ;
     RECT  0.06 28.104 0.097 28.176 ;
     RECT  0.084 28.176 0.097 28.2 ;
     RECT  0.06 28.2 0.097 28.272 ;
     RECT  0.084 28.272 0.097 28.296 ;
     RECT  0.06 28.296 0.097 28.368 ;
     RECT  0.084 28.368 0.097 28.392 ;
     RECT  0.06 28.392 0.097 28.464 ;
     RECT  0.084 28.464 0.097 28.488 ;
     RECT  0.06 28.488 0.097 28.56 ;
     RECT  0.084 28.56 0.097 28.584 ;
     RECT  0.06 28.584 0.097 28.656 ;
     RECT  0.084 28.656 0.097 28.68 ;
     RECT  0.06 28.68 0.097 28.752 ;
     RECT  0.084 28.752 0.097 28.776 ;
     RECT  0.06 28.776 0.097 28.848 ;
     RECT  0.084 28.848 0.097 28.872 ;
     RECT  0.06 28.872 0.097 28.944 ;
     RECT  0.084 28.944 0.097 28.968 ;
     RECT  0.06 28.968 0.097 29.04 ;
     RECT  0.084 29.04 0.097 29.064 ;
     RECT  0.06 29.064 0.097 29.136 ;
     RECT  0.084 29.136 0.097 29.16 ;
     RECT  0.06 29.16 0.097 29.232 ;
     RECT  0.084 29.232 0.097 29.256 ;
     RECT  0.06 29.256 0.097 29.328 ;
     RECT  0.084 29.328 0.097 29.352 ;
     RECT  0.06 29.352 0.097 29.424 ;
     RECT  0.084 29.424 0.097 29.448 ;
     RECT  0.06 29.448 0.097 29.52 ;
     RECT  0.084 29.52 0.097 29.544 ;
     RECT  0.06 29.544 0.097 29.616 ;
     RECT  0.084 29.616 0.097 29.64 ;
     RECT  0.06 29.64 0.097 29.712 ;
     RECT  0.084 29.712 0.097 29.736 ;
     RECT  0.06 29.736 0.097 29.808 ;
     RECT  0.084 29.808 0.097 29.832 ;
     RECT  0.06 29.832 0.097 29.904 ;
     RECT  0.084 29.904 0.097 29.928 ;
     RECT  0.06 29.928 0.097 30 ;
     RECT  0.084 30 0.097 30.024 ;
     RECT  0.06 30.024 0.097 30.096 ;
     RECT  0.084 30.096 0.097 30.12 ;
     RECT  0.097 5.616 2.408 30.216 ;
     RECT  2.408 2.148 2.512 41.052 ;
     RECT  2.512 2.418 2.704 40.782 ;
     RECT  2.704 5.424 2.765 8.52 ;
     RECT  2.704 9.504 2.819 31.608 ;
     RECT  2.765 7.728 2.837 8.52 ;
     RECT  2.819 25.056 2.867 31.608 ;
     RECT  2.837 8.208 2.873 8.52 ;
     RECT  2.819 9.504 2.873 24.072 ;
     RECT  2.867 25.2 3.305 31.608 ;
     RECT  3.305 25.392 3.491 31.608 ;
     RECT  2.873 9.504 3.557 22.536 ;
     RECT  3.491 30.192 3.685 31.608 ;
     RECT  2.873 8.496 3.692 8.52 ;
     RECT  3.557 9.504 3.692 17.352 ;
     RECT  3.692 8.496 3.841 17.352 ;
     RECT  3.557 18.528 3.841 22.536 ;
     RECT  2.873 23.52 3.841 24.072 ;
     RECT  3.841 8.016 3.845 17.352 ;
     RECT  2.765 5.424 3.949 6.408 ;
     RECT  3.685 30.192 4.213 31.992 ;
     RECT  3.845 8.016 4.237 17.208 ;
     RECT  3.841 18.528 4.385 24.072 ;
     RECT  3.949 5.088 4.417 6.408 ;
     RECT  4.237 7.392 4.417 17.208 ;
     RECT  4.385 23.808 4.417 24.072 ;
     RECT  3.491 25.392 4.417 29.016 ;
     RECT  4.417 23.808 5.029 29.016 ;
     RECT  5.029 23.808 5.077 29.112 ;
     RECT  4.213 30.192 5.077 32.04 ;
     RECT  4.417 5.088 5.125 17.208 ;
     RECT  5.125 4.512 5.173 17.208 ;
     RECT  4.385 18.528 5.173 22.824 ;
     RECT  5.173 4.512 5.357 17.448 ;
     RECT  5.357 5.136 5.461 17.448 ;
     RECT  5.173 18.432 5.461 22.824 ;
     RECT  5.461 5.136 5.501 22.824 ;
     RECT  5.501 6.048 5.713 22.824 ;
     RECT  5.077 23.808 5.713 32.04 ;
     RECT  5.713 6.048 5.789 32.04 ;
     RECT  5.789 6.048 6.035 31.944 ;
     RECT  7.117 39.6 7.585 39.624 ;
     RECT  7.585 39.504 7.657 39.624 ;
     RECT  7.513 41.616 7.765 41.64 ;
     RECT  6.035 6.048 7.808 31.512 ;
     RECT  7.801 37.056 7.808 37.08 ;
     RECT  7.657 39.504 7.808 40.056 ;
     RECT  7.765 41.616 7.808 42.216 ;
     RECT  7.808 2.148 7.912 42.216 ;
     RECT  7.912 2.418 8.104 42.216 ;
     RECT  8.104 6.048 8.201 29.544 ;
     RECT  8.104 39.264 8.243 42.216 ;
     RECT  8.201 19.824 8.309 29.544 ;
     RECT  8.201 6.048 8.381 18.792 ;
     RECT  8.309 29.088 8.453 29.544 ;
     RECT  8.453 29.328 8.489 29.544 ;
     RECT  8.381 6.048 8.531 9.576 ;
     RECT  8.243 39.312 8.549 42.216 ;
     RECT  8.549 39.312 8.561 43.08 ;
     RECT  8.561 39.552 8.597 43.08 ;
     RECT  8.309 19.824 8.633 27.672 ;
     RECT  8.597 39.84 8.633 43.08 ;
     RECT  8.633 19.824 8.741 24.792 ;
     RECT  8.741 19.824 8.813 24.504 ;
     RECT  8.633 25.824 8.813 27.672 ;
     RECT  8.531 6.096 8.849 9.576 ;
     RECT  8.813 20.736 9.037 24.504 ;
     RECT  8.104 30.816 9.107 31.512 ;
     RECT  8.813 27.36 9.137 27.672 ;
     RECT  9.037 23.856 9.173 24.504 ;
     RECT  8.633 39.84 9.173 42.168 ;
     RECT  9.173 39.888 9.203 42.168 ;
     RECT  9.037 20.736 9.209 22.776 ;
     RECT  9.137 27.36 9.209 27.384 ;
     RECT  8.381 10.56 9.281 18.792 ;
     RECT  9.281 10.56 9.299 11.784 ;
     RECT  9.173 23.856 9.309 24.36 ;
     RECT  9.209 20.736 9.317 21.864 ;
     RECT  9.309 23.904 9.347 24.36 ;
     RECT  8.813 25.824 9.389 25.848 ;
     RECT  8.849 6.864 9.425 9.576 ;
     RECT  9.281 12.768 9.425 18.792 ;
     RECT  8.489 29.328 9.461 29.352 ;
     RECT  8.104 36.768 9.493 38.28 ;
     RECT  9.299 10.56 9.497 11.736 ;
     RECT  9.493 36.576 9.565 38.28 ;
     RECT  9.425 9.504 9.637 9.576 ;
     RECT  9.497 10.56 9.637 11.064 ;
     RECT  9.601 28.512 9.685 28.536 ;
     RECT  9.673 42.192 9.709 42.216 ;
     RECT  9.317 20.736 9.713 21.144 ;
     RECT  9.565 36.576 9.713 38.568 ;
     RECT  9.709 42.192 9.779 42.312 ;
     RECT  9.713 20.736 9.785 20.76 ;
     RECT  9.713 36.576 9.853 38.472 ;
     RECT  9.425 6.864 9.925 8.424 ;
     RECT  9.425 12.768 9.971 18.744 ;
     RECT  9.779 42.288 10.067 42.312 ;
     RECT  9.853 36 10.069 38.472 ;
     RECT  9.989 25.68 10.073 25.704 ;
     RECT  10.069 35.328 10.259 38.472 ;
     RECT  9.925 6.288 10.289 8.424 ;
     RECT  9.971 14.976 10.433 18.744 ;
     RECT  9.203 39.888 10.465 41.016 ;
     RECT  10.393 26.784 10.477 27.768 ;
     RECT  9.637 9.504 10.645 11.064 ;
     RECT  10.645 9.504 10.717 11.736 ;
     RECT  9.971 12.768 10.717 13.992 ;
     RECT  9.205 4.896 10.825 4.92 ;
     RECT  9.107 30.816 10.825 30.84 ;
     RECT  10.825 4.896 10.865 5.016 ;
     RECT  10.825 30.816 10.865 30.936 ;
     RECT  10.289 8.112 10.94 8.424 ;
     RECT  10.717 9.504 10.94 13.992 ;
     RECT  10.609 29.616 10.973 29.64 ;
     RECT  10.259 35.472 11.005 38.472 ;
     RECT  10.465 39.696 11.005 41.016 ;
     RECT  11.005 35.472 11.009 41.016 ;
     RECT  11.009 35.472 11.045 38.76 ;
     RECT  10.94 8.112 11.189 13.992 ;
     RECT  9.347 23.904 11.189 23.928 ;
     RECT  10.289 6.288 11.293 7.128 ;
     RECT  11.189 8.112 11.293 11.592 ;
     RECT  10.433 14.976 11.369 17.16 ;
     RECT  11.009 40.464 11.411 41.016 ;
     RECT  11.293 6.288 11.729 11.592 ;
     RECT  11.729 8.4 11.765 11.592 ;
     RECT  11.293 42.192 11.795 42.216 ;
     RECT  10.477 26.832 11.797 27.768 ;
     RECT  11.797 26.832 11.905 27.864 ;
     RECT  11.189 12.576 11.941 13.992 ;
     RECT  11.369 14.976 11.941 17.064 ;
     RECT  11.941 29.76 12.035 29.784 ;
     RECT  12.005 43.056 12.089 43.08 ;
     RECT  11.411 40.464 12.373 40.728 ;
     RECT  11.045 35.568 12.517 38.76 ;
     RECT  12.517 35.568 12.613 39 ;
     RECT  12.373 40.464 12.613 41.64 ;
     RECT  12.469 24.864 12.62 24.888 ;
     RECT  12.469 22.56 12.661 22.584 ;
     RECT  11.905 26.256 12.661 27.864 ;
     RECT  11.729 6.288 12.769 7.128 ;
     RECT  11.765 8.4 12.805 11.496 ;
     RECT  11.941 12.576 12.805 17.064 ;
     RECT  10.433 18.432 12.805 18.744 ;
     RECT  12.769 6.288 13.021 7.416 ;
     RECT  12.805 8.4 13.021 18.744 ;
     RECT  12.949 0.096 13.043 0.12 ;
     RECT  10.865 4.992 13.052 5.016 ;
     RECT  13.021 6.288 13.052 18.744 ;
     RECT  13.052 4.992 13.093 18.744 ;
     RECT  12.661 22.176 13.129 22.584 ;
     RECT  12.613 35.568 13.139 41.64 ;
     RECT  13.093 1.776 13.165 2.328 ;
     RECT  13.093 0.576 13.177 0.6 ;
     RECT  13.165 1.728 13.208 2.328 ;
     RECT  13.201 3.408 13.208 3.432 ;
     RECT  13.093 4.512 13.208 18.744 ;
     RECT  13.129 22.176 13.208 22.824 ;
     RECT  12.62 23.952 13.208 24.888 ;
     RECT  12.661 26.112 13.208 27.864 ;
     RECT  12.265 29.088 13.208 29.112 ;
     RECT  10.865 30.912 13.208 30.936 ;
     RECT  13.139 35.568 13.208 41.256 ;
     RECT  13.208 1.728 13.249 41.256 ;
     RECT  13.249 1.776 13.331 41.256 ;
     RECT  13.331 2.418 13.385 41.256 ;
     RECT  13.385 2.418 13.504 41.208 ;
     RECT  13.504 34.752 13.565 41.208 ;
     RECT  13.504 19.872 13.619 21.096 ;
     RECT  13.619 20.496 13.667 21.096 ;
     RECT  13.504 22.512 13.667 22.776 ;
     RECT  13.565 34.752 13.673 41.16 ;
     RECT  13.667 21.072 13.709 21.096 ;
     RECT  13.673 34.752 13.825 41.016 ;
     RECT  13.504 24.72 13.997 27.336 ;
     RECT  13.997 24.72 14.069 27.192 ;
     RECT  13.573 43.056 14.141 43.08 ;
     RECT  13.825 34.752 14.249 40.728 ;
     RECT  14.249 34.752 14.285 40.248 ;
     RECT  13.504 7.104 14.393 18.744 ;
     RECT  13.504 30.288 14.497 30.936 ;
     RECT  13.504 4.992 14.501 5.88 ;
     RECT  14.501 4.992 14.533 5.016 ;
     RECT  14.393 7.44 14.537 18.744 ;
     RECT  13.667 22.512 14.569 22.584 ;
     RECT  14.537 7.68 14.579 18.744 ;
     RECT  14.579 16.608 14.629 18.744 ;
     RECT  14.569 21.792 14.821 22.584 ;
     RECT  14.785 6.048 14.929 6.072 ;
     RECT  14.285 34.8 14.969 40.248 ;
     RECT  14.069 27.168 15.037 27.192 ;
     RECT  15.037 27.168 15.145 27.912 ;
     RECT  15.073 28.992 15.145 29.016 ;
     RECT  15.145 27.168 15.157 29.016 ;
     RECT  14.497 30.24 15.157 30.936 ;
     RECT  15.157 27.168 15.181 30.936 ;
     RECT  15.181 27.168 15.203 30.984 ;
     RECT  14.629 16.608 15.217 19.224 ;
     RECT  15.203 27.84 15.218 30.984 ;
     RECT  13.504 3.408 15.253 3.432 ;
     RECT  14.533 4.512 15.253 5.016 ;
     RECT  14.579 7.68 15.257 15.624 ;
     RECT  14.821 21.792 15.317 22.68 ;
     RECT  14.969 35.712 15.325 40.248 ;
     RECT  15.218 27.84 15.329 28.056 ;
     RECT  15.325 35.712 15.329 40.488 ;
     RECT  15.217 16.608 15.349 19.944 ;
     RECT  15.349 16.608 15.395 20.712 ;
     RECT  15.317 21.792 15.401 22.872 ;
     RECT  15.218 29.04 15.401 30.984 ;
     RECT  15.329 38.496 15.409 40.488 ;
     RECT  15.401 21.792 15.473 22.824 ;
     RECT  15.329 35.712 15.473 37.464 ;
     RECT  15.409 38.496 15.473 40.248 ;
     RECT  14.069 24.72 15.509 26.136 ;
     RECT  15.253 3.408 15.545 5.016 ;
     RECT  15.473 37.44 15.545 37.464 ;
     RECT  15.395 19.968 15.649 20.712 ;
     RECT  15.401 29.616 15.757 30.984 ;
     RECT  14.713 32.208 15.757 32.232 ;
     RECT  15.509 24.72 15.793 25.224 ;
     RECT  15.473 22.704 15.827 22.824 ;
     RECT  14.929 6.048 15.865 6.168 ;
     RECT  15.545 3.552 15.869 5.016 ;
     RECT  15.865 6.048 15.901 6.264 ;
     RECT  15.257 7.68 15.901 13.368 ;
     RECT  15.257 14.4 15.901 15.624 ;
     RECT  15.395 16.608 15.901 18.984 ;
     RECT  15.757 29.616 15.925 32.232 ;
     RECT  15.793 23.904 15.941 25.224 ;
     RECT  15.473 35.712 15.941 36.408 ;
     RECT  15.901 14.4 15.971 18.984 ;
     RECT  15.925 29.616 15.971 32.616 ;
     RECT  15.757 0.096 15.973 0.12 ;
     RECT  15.941 35.856 15.977 36.408 ;
     RECT  15.971 32.592 16.012 32.616 ;
     RECT  15.973 0.096 16.045 0.6 ;
     RECT  15.901 6.048 16.045 13.368 ;
     RECT  15.971 29.616 16.049 31.32 ;
     RECT  16.045 0.096 16.115 1.128 ;
     RECT  16.115 0.576 16.117 1.128 ;
     RECT  15.473 38.496 16.121 39.912 ;
     RECT  15.977 36.336 16.157 36.408 ;
     RECT  15.971 14.4 16.193 17.064 ;
     RECT  16.049 29.664 16.193 30.984 ;
     RECT  16.121 39.168 16.193 39.912 ;
     RECT  16.193 39.168 16.229 39.816 ;
     RECT  16.045 6 16.261 13.368 ;
     RECT  16.229 39.168 16.301 39.192 ;
     RECT  16.117 0.576 16.307 1.848 ;
     RECT  16.193 14.736 16.307 17.064 ;
     RECT  15.329 27.84 16.333 27.912 ;
     RECT  16.307 15.216 16.337 15.624 ;
     RECT  16.193 29.664 16.409 30.6 ;
     RECT  15.827 22.8 16.441 22.824 ;
     RECT  16.157 36.384 16.445 36.408 ;
     RECT  16.261 6 16.513 13.656 ;
     RECT  15.869 3.552 16.553 4.296 ;
     RECT  16.553 3.984 16.589 4.296 ;
     RECT  16.441 22.8 16.657 22.92 ;
     RECT  15.941 23.904 16.657 24.984 ;
     RECT  16.307 1.104 16.691 1.848 ;
     RECT  16.333 27.84 16.693 28.488 ;
     RECT  16.409 29.664 16.697 30.264 ;
     RECT  15.649 19.968 16.841 21.384 ;
     RECT  16.657 37.536 16.841 37.56 ;
     RECT  16.691 1.68 16.901 1.848 ;
     RECT  15.971 18.432 16.909 18.984 ;
     RECT  16.697 29.712 16.985 30.264 ;
     RECT  16.873 37.2 16.985 37.224 ;
     RECT  16.985 29.712 17.027 29.88 ;
     RECT  16.693 26.88 17.053 28.488 ;
     RECT  16.901 1.68 17.089 1.944 ;
     RECT  16.909 18.432 17.089 19.128 ;
     RECT  16.513 5.856 17.093 13.656 ;
     RECT  16.307 16.608 17.125 17.064 ;
     RECT  17.089 18.288 17.125 19.128 ;
     RECT  16.337 15.6 17.305 15.624 ;
     RECT  17.125 16.608 17.305 19.128 ;
     RECT  17.305 15.6 17.341 19.128 ;
     RECT  16.841 20.256 17.345 21.384 ;
     RECT  17.276 0.528 17.363 0.552 ;
     RECT  16.589 4.272 17.377 4.296 ;
     RECT  17.093 5.856 17.377 12.792 ;
     RECT  17.053 26.832 17.377 28.488 ;
     RECT  17.377 4.272 17.381 12.792 ;
     RECT  17.089 1.68 17.485 2.28 ;
     RECT  17.341 15.456 17.605 19.128 ;
     RECT  16.657 22.8 17.605 24.984 ;
     RECT  17.377 26.016 17.605 28.488 ;
     RECT  17.605 22.8 17.653 28.488 ;
     RECT  17.485 1.68 17.737 2.712 ;
     RECT  17.737 1.68 17.747 2.856 ;
     RECT  17.605 14.784 17.852 19.128 ;
     RECT  17.345 20.256 17.852 21.24 ;
     RECT  17.381 4.464 18.133 12.792 ;
     RECT  17.747 1.728 18.161 2.856 ;
     RECT  18.161 1.728 18.421 3.432 ;
     RECT  18.133 4.464 18.421 13.704 ;
     RECT  18.421 1.728 18.608 13.704 ;
     RECT  17.852 14.784 18.608 21.24 ;
     RECT  17.653 22.416 18.608 28.488 ;
     RECT  17.027 29.856 18.608 29.88 ;
     RECT  18.608 1.728 18.712 41.052 ;
     RECT  18.712 1.728 18.904 40.782 ;
     RECT  18.904 3.6 19.001 27.912 ;
     RECT  18.904 1.728 19.289 2.52 ;
     RECT  19.289 2.256 19.693 2.52 ;
     RECT  19.001 3.6 19.909 9.576 ;
     RECT  19.717 1.104 19.955 1.128 ;
     RECT  19.001 10.608 19.973 27.912 ;
     RECT  17.377 0.048 20.005 0.072 ;
     RECT  19.973 10.608 20.045 27.432 ;
     RECT  20.005 0.048 20.185 0.12 ;
     RECT  20.185 0.048 20.225 0.6 ;
     RECT  20.045 22.656 20.297 27.432 ;
     RECT  19.909 3.216 20.333 9.576 ;
     RECT  20.333 3.408 20.435 9.576 ;
     RECT  20.435 4.992 20.437 9.576 ;
     RECT  20.045 10.608 20.437 21.624 ;
     RECT  20.297 22.656 20.477 26.424 ;
     RECT  20.435 3.408 20.621 3.96 ;
     RECT  20.437 4.992 20.621 21.624 ;
     RECT  20.677 1.776 20.965 1.8 ;
     RECT  20.965 1.728 21.013 1.8 ;
     RECT  20.621 3.936 21.107 3.96 ;
     RECT  20.225 0.096 21.116 0.6 ;
     RECT  21.013 1.728 21.116 1.848 ;
     RECT  18.904 29.856 21.193 29.88 ;
     RECT  20.621 7.92 21.197 21.624 ;
     RECT  21.116 0.096 21.203 1.848 ;
     RECT  21.203 0.096 21.305 0.6 ;
     RECT  20.477 25.728 21.445 26.424 ;
     RECT  20.297 27.408 21.445 27.432 ;
     RECT  21.445 25.728 21.485 27.432 ;
     RECT  20.621 4.992 21.509 6.888 ;
     RECT  21.203 1.68 21.589 1.848 ;
     RECT  20.477 22.656 21.589 24.744 ;
     RECT  21.485 25.728 21.589 27.192 ;
     RECT  21.589 1.68 21.593 1.896 ;
     RECT  21.509 4.56 21.593 6.888 ;
     RECT  21.593 1.728 21.676 1.896 ;
     RECT  21.197 8.304 21.733 21.624 ;
     RECT  21.589 22.656 21.733 27.192 ;
     RECT  21.733 8.304 21.953 27.192 ;
     RECT  21.305 0.096 21.971 0.552 ;
     RECT  21.593 4.944 22.021 6.888 ;
     RECT  21.953 8.304 22.241 23.112 ;
     RECT  22.241 21.792 22.349 23.112 ;
     RECT  22.021 4.944 22.489 6.984 ;
     RECT  22.241 8.304 22.489 20.808 ;
     RECT  21.953 24.192 22.501 27.192 ;
     RECT  22.46 28.416 22.501 28.44 ;
     RECT  21.193 29.856 22.501 30.216 ;
     RECT  21.971 0.096 22.525 0.408 ;
     RECT  22.501 24.192 22.547 28.44 ;
     RECT  22.489 4.944 22.573 20.808 ;
     RECT  22.501 29.616 22.588 31.128 ;
     RECT  22.573 4.944 22.705 6.744 ;
     RECT  22.345 2.928 22.741 2.952 ;
     RECT  21.676 1.728 22.745 1.752 ;
     RECT  22.573 8.304 22.835 20.808 ;
     RECT  22.741 2.736 22.849 2.952 ;
     RECT  22.705 4.272 22.849 6.744 ;
     RECT  22.835 8.304 22.853 14.712 ;
     RECT  22.349 21.792 22.853 21.816 ;
     RECT  22.835 16.032 22.889 20.808 ;
     RECT  22.849 2.736 23.281 6.744 ;
     RECT  22.588 29.76 23.677 31.128 ;
     RECT  23.281 2.496 23.713 6.744 ;
     RECT  22.853 8.304 23.713 14.664 ;
     RECT  22.547 24.192 23.713 27.624 ;
     RECT  22.889 16.56 23.785 20.808 ;
     RECT  23.713 2.496 23.821 14.664 ;
     RECT  23.821 2.496 23.852 15.336 ;
     RECT  23.785 16.56 23.852 21.144 ;
     RECT  22.349 22.8 23.857 23.112 ;
     RECT  23.857 42.192 23.929 42.216 ;
     RECT  23.852 2.496 24.008 21.144 ;
     RECT  23.857 22.464 24.008 23.112 ;
     RECT  23.713 24.192 24.008 27.72 ;
     RECT  23.677 29.76 24.008 31.416 ;
     RECT  23.929 41.616 24.008 42.216 ;
     RECT  24.008 2.148 24.112 42.216 ;
     RECT  24.112 2.418 24.253 42.216 ;
     RECT  24.253 2.418 24.304 43.08 ;
     RECT  24.304 7.344 24.437 27.816 ;
     RECT  24.437 27.504 24.515 27.816 ;
     RECT  24.304 29.376 24.515 31.56 ;
     RECT  24.437 7.344 24.604 26.28 ;
     RECT  24.515 30.864 24.869 31.56 ;
     RECT  24.604 7.344 24.905 17.688 ;
     RECT  24.515 27.504 24.941 27.72 ;
     RECT  24.604 18.72 24.977 26.28 ;
     RECT  24.304 2.496 25.013 5.736 ;
     RECT  24.869 31.392 25.091 31.56 ;
     RECT  24.304 39.36 25.093 43.08 ;
     RECT  24.977 22.32 25.121 26.28 ;
     RECT  25.091 31.392 25.121 31.512 ;
     RECT  24.515 29.376 25.157 29.88 ;
     RECT  24.905 9.408 25.235 17.688 ;
     RECT  25.235 9.408 25.265 10.344 ;
     RECT  25.121 22.32 25.337 24.696 ;
     RECT  24.905 7.344 25.405 8.232 ;
     RECT  25.265 9.408 25.517 10.296 ;
     RECT  25.337 22.32 25.553 24.648 ;
     RECT  25.553 22.848 25.625 24.648 ;
     RECT  25.121 25.824 25.625 26.28 ;
     RECT  25.013 5.616 25.667 5.736 ;
     RECT  25.013 2.496 25.697 4.584 ;
     RECT  25.667 5.616 25.708 5.64 ;
     RECT  24.977 18.72 25.715 21.144 ;
     RECT  25.625 23.088 25.733 24.648 ;
     RECT  25.405 6.816 25.805 8.232 ;
     RECT  25.715 18.72 25.805 19.992 ;
     RECT  24.304 32.592 25.805 32.616 ;
     RECT  25.235 12.048 25.841 17.688 ;
     RECT  25.805 18.72 25.841 18.792 ;
     RECT  25.715 21.12 25.841 21.144 ;
     RECT  25.841 12.048 25.949 17.64 ;
     RECT  25.949 12.288 26.003 17.64 ;
     RECT  25.697 2.496 26.057 4.248 ;
     RECT  26.003 12.288 26.129 14.856 ;
     RECT  22.525 0.048 26.165 0.408 ;
     RECT  25.517 9.408 26.165 9.816 ;
     RECT  24.941 27.696 26.197 27.72 ;
     RECT  26.165 0.144 26.237 0.408 ;
     RECT  26.057 2.496 26.273 3.768 ;
     RECT  26.237 0.144 26.309 0.168 ;
     RECT  26.273 2.592 26.309 3.768 ;
     RECT  26.165 9.504 26.309 9.816 ;
     RECT  25.805 6.816 26.377 6.84 ;
     RECT  25.121 31.488 26.377 31.512 ;
     RECT  25.733 23.088 26.381 24.456 ;
     RECT  25.805 19.776 26.453 19.992 ;
     RECT  25.093 40.08 26.485 43.08 ;
     RECT  26.309 9.552 26.525 9.816 ;
     RECT  25.805 7.92 26.561 8.232 ;
     RECT  26.197 26.736 26.597 27.72 ;
     RECT  25.801 38.016 26.737 38.808 ;
     RECT  26.309 3.456 26.741 3.768 ;
     RECT  25.841 18.768 26.741 18.792 ;
     RECT  26.485 40.032 26.771 43.08 ;
     RECT  26.561 7.92 26.813 7.944 ;
     RECT  26.377 31.488 26.813 32.088 ;
     RECT  26.771 40.032 26.813 41.928 ;
     RECT  25.157 29.856 26.845 29.88 ;
     RECT  26.737 37.92 26.881 38.952 ;
     RECT  26.453 19.776 27.101 19.8 ;
     RECT  26.771 43.056 27.155 43.08 ;
     RECT  26.129 12.528 27.173 14.856 ;
     RECT  26.881 37.584 27.205 38.952 ;
     RECT  26.381 23.616 27.209 24.456 ;
     RECT  26.377 6.72 27.277 6.84 ;
     RECT  26.845 29.76 27.277 29.88 ;
     RECT  26.813 31.488 27.277 31.752 ;
     RECT  26.741 3.744 27.281 3.768 ;
     RECT  27.173 12.576 27.395 14.856 ;
     RECT  27.395 14.112 27.397 14.856 ;
     RECT  26.003 15.84 27.397 17.64 ;
     RECT  26.525 9.744 27.445 9.816 ;
     RECT  27.349 11.232 27.445 11.256 ;
     RECT  27.395 12.576 27.461 13.032 ;
     RECT  27.397 14.112 27.484 17.64 ;
     RECT  27.445 9.744 27.533 11.256 ;
     RECT  27.461 12.864 27.533 13.032 ;
     RECT  27.097 21.408 27.565 21.432 ;
     RECT  27.209 23.952 27.605 24.456 ;
     RECT  27.133 25.824 27.817 25.848 ;
     RECT  26.597 26.832 27.817 27.72 ;
     RECT  27.533 11.232 27.857 11.256 ;
     RECT  27.205 37.152 27.877 38.952 ;
     RECT  26.813 40.08 27.877 41.928 ;
     RECT  27.533 9.744 27.925 9.864 ;
     RECT  27.877 37.152 27.925 41.928 ;
     RECT  27.925 9.408 27.997 9.864 ;
     RECT  27.925 37.152 28.019 42.168 ;
     RECT  27.385 33.024 28.033 33.048 ;
     RECT  28.019 37.152 28.033 39 ;
     RECT  27.484 15.984 28.037 17.64 ;
     RECT  27.997 9.072 28.069 9.864 ;
     RECT  27.565 21.408 28.105 21.672 ;
     RECT  27.277 6.72 28.109 7.416 ;
     RECT  27.277 29.76 28.145 31.752 ;
     RECT  28.105 21.408 28.177 22.344 ;
     RECT  28.033 33.024 28.181 33.48 ;
     RECT  28.019 40.368 28.181 42.168 ;
     RECT  28.069 8.88 28.217 9.864 ;
     RECT  28.037 16.56 28.249 17.64 ;
     RECT  27.817 25.824 28.289 27.72 ;
     RECT  27.533 13.008 28.325 13.032 ;
     RECT  28.181 33.12 28.325 33.48 ;
     RECT  28.289 26.256 28.361 27.72 ;
     RECT  27.484 14.112 28.501 14.904 ;
     RECT  28.181 40.848 28.573 42.168 ;
     RECT  27.605 23.952 28.645 24.408 ;
     RECT  28.033 36.48 28.969 39 ;
     RECT  28.249 16.56 29.005 18.6 ;
     RECT  28.501 14.112 29.077 14.952 ;
     RECT  28.604 35.376 29.077 35.4 ;
     RECT  28.969 36.432 29.113 39 ;
     RECT  28.573 40.848 29.173 42.216 ;
     RECT  28.645 23.952 29.185 25.08 ;
     RECT  28.177 20.976 29.221 22.344 ;
     RECT  29.185 23.376 29.221 25.08 ;
     RECT  29.173 40.848 29.267 42.984 ;
     RECT  29.113 36.432 29.269 39.096 ;
     RECT  29.267 42.192 29.269 42.984 ;
     RECT  28.933 28.416 29.401 28.44 ;
     RECT  28.145 29.808 29.401 31.752 ;
     RECT  28.393 7.488 29.408 7.512 ;
     RECT  28.217 9.072 29.408 9.816 ;
     RECT  29.077 14.112 29.408 15.432 ;
     RECT  29.005 16.56 29.408 19.368 ;
     RECT  29.221 20.976 29.408 25.08 ;
     RECT  28.361 26.256 29.408 27.192 ;
     RECT  29.401 28.416 29.408 31.752 ;
     RECT  28.325 33.312 29.408 33.48 ;
     RECT  29.077 35.088 29.408 35.448 ;
     RECT  29.269 36.432 29.408 39.864 ;
     RECT  29.267 40.848 29.408 41.16 ;
     RECT  29.269 42.192 29.459 43.032 ;
     RECT  29.408 2.148 29.512 41.16 ;
     RECT  29.512 2.418 29.704 41.16 ;
     RECT  29.704 35.424 29.788 41.16 ;
     RECT  29.788 35.424 29.843 41.016 ;
     RECT  29.704 22.176 29.873 22.488 ;
     RECT  29.459 42.912 29.987 43.032 ;
     RECT  29.704 30.336 30.305 31.752 ;
     RECT  29.704 24.192 30.341 24.408 ;
     RECT  29.987 42.912 30.341 42.936 ;
     RECT  29.843 40.464 30.419 41.016 ;
     RECT  29.704 21.12 30.449 21.144 ;
     RECT  29.873 22.176 30.629 22.2 ;
     RECT  29.843 35.424 30.697 39.336 ;
     RECT  30.341 24.336 30.755 24.408 ;
     RECT  29.704 26.256 30.881 29.016 ;
     RECT  29.704 14.112 30.995 14.136 ;
     RECT  30.697 34.176 31.021 39.336 ;
     RECT  30.755 24.336 31.061 24.36 ;
     RECT  30.881 26.256 31.205 27.192 ;
     RECT  30.305 30.816 31.205 31.752 ;
     RECT  30.419 40.992 31.277 41.016 ;
     RECT  30.881 28.416 31.385 29.016 ;
     RECT  30.697 23.328 31.457 23.352 ;
     RECT  31.205 26.256 31.565 26.472 ;
     RECT  31.021 34.176 31.571 39.912 ;
     RECT  31.205 30.912 31.637 31.752 ;
     RECT  31.565 26.256 31.705 26.28 ;
     RECT  31.571 38.064 31.709 39.912 ;
     RECT  31.637 31.488 32.137 31.752 ;
     RECT  31.993 32.976 32.137 33 ;
     RECT  32.137 31.488 32.173 33 ;
     RECT  31.571 34.176 32.173 37.08 ;
     RECT  31.993 29.664 32.629 29.688 ;
     RECT  32.173 31.488 32.629 37.08 ;
     RECT  31.705 25.584 32.705 26.28 ;
     RECT  32.629 29.664 32.713 37.08 ;
     RECT  31.709 38.064 32.713 39.816 ;
     RECT  32.705 25.584 32.732 26.808 ;
     RECT  32.732 25.584 32.771 27.336 ;
     RECT  32.771 26.256 32.773 27.336 ;
     RECT  31.385 28.416 32.773 28.44 ;
     RECT  32.773 26.256 32.789 28.44 ;
     RECT  32.789 27.312 32.819 28.44 ;
     RECT  32.789 26.256 32.825 26.28 ;
     RECT  32.819 28.176 32.893 28.44 ;
     RECT  32.713 29.664 32.893 39.816 ;
     RECT  32.893 28.176 32.977 39.816 ;
     RECT  32.977 28.176 33.113 37.992 ;
     RECT  33.113 28.176 33.149 29.112 ;
     RECT  32.977 39.024 33.181 39.816 ;
     RECT  33.181 39.024 33.221 40.44 ;
     RECT  33.221 40.416 33.469 40.44 ;
     RECT  33.113 30.432 34.124 37.992 ;
     RECT  33.221 39.024 34.124 39.096 ;
     RECT  34.124 30.432 34.405 39.096 ;
     RECT  34.405 29.568 34.549 39.096 ;
     RECT  33.469 40.416 34.549 40.68 ;
     RECT  33.149 28.176 34.808 28.44 ;
     RECT  34.549 29.568 34.808 40.68 ;
     RECT  34.808 2.148 34.912 41.052 ;
     RECT  34.912 2.418 35.104 41.052 ;
     RECT  35.104 28.176 35.201 28.2 ;
     RECT  35.104 29.472 35.341 41.052 ;
     RECT  35.341 29.472 35.737 41.112 ;
     RECT  35.737 29.472 35.993 42.024 ;
     RECT  35.993 29.616 37.073 42.024 ;
     RECT  37.073 31.152 37.109 42.024 ;
     RECT  37.073 29.616 37.541 29.64 ;
     RECT  37.109 31.248 38.077 42.024 ;
     RECT  38.077 30.72 38.833 42.024 ;
     RECT  38.833 30.624 39.517 42.024 ;
     RECT  39.517 30.384 39.661 42.024 ;
     RECT  39.661 30.336 40.057 42.024 ;
     RECT  40.057 29.616 40.208 42.024 ;
     RECT  40.208 2.148 40.312 42.024 ;
     RECT  40.312 2.418 40.504 42.024 ;
     RECT  40.504 29.136 40.529 42.024 ;
     RECT  40.529 32.304 41.281 42.024 ;
     RECT  40.529 29.136 42.253 31.272 ;
     RECT  41.281 32.304 42.253 42.12 ;
     RECT  42.253 29.136 43.116 29.16 ;
     RECT  42.253 29.16 43.164 29.232 ;
     RECT  42.253 29.232 43.116 29.256 ;
     RECT  42.253 29.256 43.164 29.328 ;
     RECT  42.253 29.328 43.116 29.352 ;
     RECT  42.253 29.352 43.164 29.424 ;
     RECT  42.253 29.424 43.116 29.448 ;
     RECT  42.253 29.448 43.164 29.52 ;
     RECT  42.253 29.52 43.116 29.544 ;
     RECT  42.253 29.544 43.164 29.616 ;
     RECT  42.253 29.616 43.116 29.64 ;
     RECT  42.253 29.64 43.164 29.712 ;
     RECT  42.253 29.712 43.116 29.736 ;
     RECT  42.253 29.736 43.164 29.808 ;
     RECT  42.253 29.808 43.116 29.832 ;
     RECT  42.253 29.832 43.164 29.904 ;
     RECT  42.253 29.904 43.116 29.928 ;
     RECT  42.253 29.928 43.164 30 ;
     RECT  42.253 30 43.116 30.024 ;
     RECT  42.253 30.024 43.164 30.096 ;
     RECT  42.253 30.096 43.116 30.12 ;
     RECT  42.253 30.12 43.164 30.192 ;
     RECT  42.253 30.192 43.116 30.216 ;
     RECT  42.253 30.216 43.164 30.288 ;
     RECT  42.253 30.288 43.116 30.312 ;
     RECT  42.253 30.312 43.164 30.384 ;
     RECT  42.253 30.384 43.116 30.408 ;
     RECT  42.253 30.408 43.164 30.48 ;
     RECT  42.253 30.48 43.116 30.504 ;
     RECT  42.253 30.504 43.164 30.576 ;
     RECT  42.253 30.576 43.116 30.6 ;
     RECT  42.253 30.6 43.164 30.672 ;
     RECT  42.253 30.672 43.116 30.696 ;
     RECT  42.253 30.696 43.164 30.768 ;
     RECT  42.253 30.768 43.116 30.792 ;
     RECT  42.253 30.792 43.164 30.864 ;
     RECT  42.253 30.864 43.116 30.888 ;
     RECT  42.253 30.888 43.164 30.96 ;
     RECT  42.253 30.96 43.116 30.984 ;
     RECT  42.253 30.984 43.164 31.056 ;
     RECT  42.253 31.056 43.116 31.08 ;
     RECT  42.253 31.08 43.164 31.152 ;
     RECT  42.253 31.152 43.116 31.176 ;
     RECT  42.253 31.176 43.164 31.248 ;
     RECT  42.253 31.248 43.116 31.272 ;
     RECT  42.253 31.272 43.164 31.344 ;
     RECT  42.253 31.344 43.116 31.368 ;
     RECT  42.253 31.368 43.164 32.208 ;
     RECT  42.253 32.208 43.116 32.232 ;
     RECT  42.253 32.232 43.164 32.304 ;
     RECT  42.253 32.304 43.116 32.328 ;
     RECT  42.253 32.328 43.164 32.4 ;
     RECT  42.253 32.4 43.116 32.424 ;
     RECT  42.253 32.424 43.164 32.496 ;
     RECT  42.253 32.496 43.116 32.52 ;
     RECT  42.253 32.52 43.164 32.592 ;
     RECT  42.253 32.592 43.116 32.616 ;
     RECT  42.253 32.616 43.164 32.688 ;
     RECT  42.253 32.688 43.116 32.712 ;
     RECT  42.253 32.712 43.164 32.784 ;
     RECT  42.253 32.784 43.116 32.808 ;
     RECT  42.253 32.808 43.164 32.88 ;
     RECT  42.253 32.88 43.116 32.904 ;
     RECT  42.253 32.904 43.164 32.976 ;
     RECT  42.253 32.976 43.116 33 ;
     RECT  42.253 33 43.164 33.072 ;
     RECT  42.253 33.072 43.116 33.096 ;
     RECT  42.253 33.096 43.164 33.168 ;
     RECT  42.253 33.168 43.116 33.192 ;
     RECT  42.253 33.192 43.164 33.264 ;
     RECT  42.253 33.264 43.116 33.288 ;
     RECT  42.253 33.288 43.164 33.36 ;
     RECT  42.253 33.36 43.116 33.384 ;
     RECT  42.253 33.384 43.164 33.456 ;
     RECT  42.253 33.456 43.116 33.48 ;
     RECT  42.253 33.48 43.164 33.552 ;
     RECT  42.253 33.552 43.116 33.576 ;
     RECT  42.253 33.576 43.164 33.648 ;
     RECT  42.253 33.648 43.116 33.672 ;
     RECT  42.253 33.672 43.164 33.744 ;
     RECT  42.253 33.744 43.116 33.768 ;
     RECT  42.253 33.768 43.164 33.84 ;
     RECT  42.253 33.84 43.116 33.864 ;
     RECT  42.253 33.864 43.164 33.936 ;
     RECT  42.253 33.936 43.116 33.96 ;
     RECT  42.253 33.96 43.164 34.032 ;
     RECT  42.253 34.032 43.116 34.056 ;
     RECT  42.253 34.056 43.164 34.128 ;
     RECT  42.253 34.128 43.116 34.152 ;
     RECT  42.253 34.152 43.164 34.224 ;
     RECT  42.253 34.224 43.116 34.248 ;
     RECT  42.253 34.248 43.164 34.32 ;
     RECT  42.253 34.32 43.116 34.344 ;
     RECT  42.253 34.344 43.164 34.416 ;
     RECT  42.253 34.416 43.116 34.44 ;
     RECT  42.253 34.44 43.164 34.512 ;
     RECT  42.253 34.512 43.116 34.536 ;
     RECT  42.253 34.536 43.164 34.608 ;
     RECT  42.253 34.608 43.116 34.632 ;
     RECT  42.253 34.632 43.164 34.704 ;
     RECT  42.253 34.704 43.116 34.728 ;
     RECT  42.253 34.728 43.164 34.8 ;
     RECT  42.253 34.8 43.116 34.824 ;
     RECT  42.253 34.824 43.164 34.896 ;
     RECT  42.253 34.896 43.116 34.92 ;
     RECT  42.253 34.92 43.164 34.992 ;
     RECT  42.253 34.992 43.116 35.016 ;
     RECT  42.253 35.016 43.164 35.088 ;
     RECT  42.253 35.088 43.116 35.112 ;
     RECT  42.253 35.112 43.164 35.184 ;
     RECT  42.253 35.184 43.116 35.208 ;
     RECT  42.253 35.208 43.164 35.28 ;
     RECT  42.253 35.28 43.116 35.304 ;
     RECT  42.253 35.304 43.164 35.376 ;
     RECT  42.253 35.376 43.116 35.4 ;
     RECT  42.253 35.4 43.164 35.472 ;
     RECT  42.253 35.472 43.116 35.496 ;
     RECT  42.253 35.496 43.164 35.568 ;
     RECT  42.253 35.568 43.116 35.592 ;
     RECT  42.253 35.592 43.164 35.664 ;
     RECT  42.253 35.664 43.116 35.688 ;
     RECT  42.253 35.688 43.164 35.76 ;
     RECT  42.253 35.76 43.116 35.784 ;
     RECT  42.253 35.784 43.164 35.856 ;
     RECT  42.253 35.856 43.116 35.88 ;
     RECT  42.253 35.88 43.164 35.952 ;
     RECT  42.253 35.952 43.116 35.976 ;
     RECT  42.253 35.976 43.164 36.048 ;
     RECT  42.253 36.048 43.116 36.072 ;
     RECT  42.253 36.072 43.164 36.144 ;
     RECT  42.253 36.144 43.116 36.168 ;
     RECT  42.253 36.168 43.164 36.24 ;
     RECT  42.253 36.24 43.116 36.264 ;
     RECT  42.253 36.264 43.164 36.336 ;
     RECT  42.253 36.336 43.116 36.36 ;
     RECT  42.253 36.36 43.164 36.432 ;
     RECT  42.253 36.432 43.116 36.456 ;
     RECT  42.253 36.456 43.164 36.528 ;
     RECT  42.253 36.528 43.116 36.552 ;
     RECT  42.253 36.552 43.164 36.624 ;
     RECT  42.253 36.624 43.116 36.648 ;
     RECT  42.253 36.648 43.164 36.72 ;
     RECT  42.253 36.72 43.116 36.744 ;
     RECT  42.253 36.744 43.164 36.816 ;
     RECT  42.253 36.816 43.116 36.84 ;
     RECT  42.253 36.84 43.164 36.912 ;
     RECT  42.253 36.912 43.116 36.936 ;
     RECT  42.253 36.936 43.164 37.008 ;
     RECT  42.253 37.008 43.116 37.032 ;
     RECT  42.253 37.032 43.164 37.104 ;
     RECT  42.253 37.104 43.116 37.128 ;
     RECT  42.253 37.128 43.164 37.2 ;
     RECT  42.253 37.2 43.116 37.224 ;
     RECT  42.253 37.224 43.164 37.296 ;
     RECT  42.253 37.296 43.116 37.32 ;
     RECT  42.253 37.32 43.164 37.392 ;
     RECT  42.253 37.392 43.116 37.416 ;
     RECT  42.253 37.416 43.164 37.488 ;
     RECT  42.253 37.488 43.116 37.512 ;
     RECT  42.253 37.512 43.164 37.584 ;
     RECT  42.253 37.584 43.116 37.608 ;
     RECT  42.253 37.608 43.164 37.68 ;
     RECT  42.253 37.68 43.116 37.704 ;
     RECT  42.253 37.704 43.164 37.776 ;
     RECT  42.253 37.776 43.116 37.8 ;
     RECT  42.253 37.8 43.164 37.872 ;
     RECT  42.253 37.872 43.116 37.896 ;
     RECT  42.253 37.896 43.164 37.968 ;
     RECT  42.253 37.968 43.116 37.992 ;
     RECT  42.253 37.992 43.164 38.064 ;
     RECT  42.253 38.064 43.116 38.088 ;
     RECT  42.253 38.088 43.164 38.16 ;
     RECT  42.253 38.16 43.116 38.184 ;
     RECT  42.253 38.184 43.164 38.256 ;
     RECT  42.253 38.256 43.116 38.28 ;
     RECT  42.253 38.28 43.164 39.12 ;
     RECT  42.253 39.12 43.116 39.144 ;
     RECT  42.253 39.144 43.164 39.216 ;
     RECT  42.253 39.216 43.116 39.24 ;
     RECT  42.253 39.24 43.164 39.312 ;
     RECT  42.253 39.312 43.116 39.336 ;
     RECT  42.253 39.336 43.164 39.408 ;
     RECT  42.253 39.408 43.116 39.432 ;
     RECT  42.253 39.432 43.164 39.504 ;
     RECT  42.253 39.504 43.116 39.528 ;
     RECT  42.253 39.528 43.164 39.6 ;
     RECT  42.253 39.6 43.116 39.624 ;
     RECT  42.253 39.624 43.164 39.696 ;
     RECT  42.253 39.696 43.116 39.72 ;
     RECT  42.253 39.72 43.164 39.792 ;
     RECT  42.253 39.792 43.116 39.816 ;
     RECT  42.253 39.816 43.164 39.888 ;
     RECT  42.253 39.888 43.116 39.912 ;
     RECT  42.253 39.912 43.164 39.984 ;
     RECT  42.253 39.984 43.116 40.008 ;
     RECT  42.253 40.008 43.164 40.08 ;
     RECT  42.253 40.08 43.116 40.104 ;
     RECT  42.253 40.104 43.164 40.176 ;
     RECT  42.253 40.176 43.116 40.2 ;
     RECT  42.253 40.2 43.164 40.272 ;
     RECT  42.253 40.272 43.116 40.296 ;
     RECT  42.253 40.296 43.164 40.368 ;
     RECT  42.253 40.368 43.116 40.392 ;
     RECT  42.253 40.392 43.164 40.464 ;
     RECT  42.253 40.464 43.116 40.488 ;
     RECT  42.253 40.488 43.164 40.56 ;
     RECT  42.253 40.56 43.116 40.584 ;
     RECT  42.253 40.584 43.164 40.656 ;
     RECT  42.253 40.656 43.116 40.68 ;
     RECT  42.253 40.68 43.164 40.752 ;
     RECT  42.253 40.752 43.116 40.776 ;
     RECT  42.253 40.776 43.164 40.848 ;
     RECT  42.253 40.848 43.116 40.872 ;
     RECT  42.253 40.872 43.164 40.944 ;
     RECT  42.253 40.944 43.116 40.968 ;
     RECT  42.253 40.968 43.164 41.04 ;
     RECT  42.253 41.04 43.116 41.064 ;
     RECT  42.253 41.064 43.164 41.136 ;
     RECT  42.253 41.136 43.116 41.16 ;
     RECT  42.253 41.16 43.164 41.232 ;
     RECT  42.253 41.232 43.116 41.256 ;
     RECT  42.253 41.256 43.164 41.328 ;
     RECT  42.253 41.328 43.116 41.352 ;
     RECT  42.253 41.352 43.164 41.424 ;
     RECT  42.253 41.424 43.116 41.448 ;
     RECT  42.253 41.448 43.164 41.52 ;
     RECT  42.253 41.52 43.116 41.544 ;
     RECT  42.253 41.544 43.164 41.616 ;
     RECT  42.253 41.616 43.116 41.64 ;
     RECT  42.253 41.64 43.164 41.712 ;
     RECT  42.253 41.712 43.116 41.736 ;
     RECT  42.253 41.736 43.164 41.808 ;
     RECT  42.253 41.808 43.116 41.832 ;
     RECT  42.253 41.832 43.164 41.904 ;
     RECT  42.253 41.904 43.116 41.928 ;
     RECT  42.253 41.928 43.164 42 ;
     RECT  42.253 42 43.116 42.024 ;
     RECT  42.253 42.024 43.164 42.096 ;
     RECT  42.253 42.096 43.116 42.12 ;
    LAYER M5 ;
     RECT  13.032 0.016 13.104 0.084 ;
     RECT  13.128 0.016 13.2 0.084 ;
     RECT  13.224 0.016 13.296 0.084 ;
     RECT  13.008 0.084 13.32 0.131 ;
     RECT  16.104 0.016 16.176 0.084 ;
     RECT  16.2 0.016 16.272 0.084 ;
     RECT  16.296 0.016 16.368 0.084 ;
     RECT  16.392 0.016 16.464 0.084 ;
     RECT  16.488 0.016 16.56 0.084 ;
     RECT  16.584 0.016 16.656 0.084 ;
     RECT  16.68 0.016 16.752 0.084 ;
     RECT  16.776 0.016 16.848 0.084 ;
     RECT  16.872 0.016 16.944 0.084 ;
     RECT  16.968 0.016 17.04 0.084 ;
     RECT  17.064 0.016 17.136 0.084 ;
     RECT  17.16 0.016 17.232 0.084 ;
     RECT  17.256 0.016 17.328 0.084 ;
     RECT  17.352 0.016 17.424 0.084 ;
     RECT  17.448 0.016 17.52 0.084 ;
     RECT  17.544 0.016 17.616 0.084 ;
     RECT  17.64 0.016 17.712 0.084 ;
     RECT  17.736 0.016 17.808 0.084 ;
     RECT  17.832 0.016 17.904 0.084 ;
     RECT  17.928 0.016 18 0.084 ;
     RECT  18.024 0.016 18.096 0.084 ;
     RECT  18.12 0.016 18.192 0.084 ;
     RECT  18.216 0.016 18.288 0.084 ;
     RECT  18.312 0.016 18.384 0.084 ;
     RECT  18.408 0.016 18.48 0.084 ;
     RECT  18.504 0.016 18.576 0.084 ;
     RECT  18.6 0.016 18.672 0.084 ;
     RECT  18.696 0.016 18.768 0.084 ;
     RECT  18.792 0.016 18.864 0.084 ;
     RECT  18.888 0.016 18.96 0.084 ;
     RECT  18.984 0.016 19.056 0.084 ;
     RECT  19.08 0.016 19.92 0.084 ;
     RECT  19.944 0.016 20.016 0.084 ;
     RECT  20.04 0.016 20.112 0.084 ;
     RECT  20.136 0.016 20.208 0.084 ;
     RECT  20.232 0.016 20.304 0.084 ;
     RECT  20.328 0.016 20.4 0.084 ;
     RECT  20.424 0.016 20.496 0.084 ;
     RECT  20.52 0.016 20.592 0.084 ;
     RECT  20.616 0.016 20.688 0.084 ;
     RECT  20.712 0.016 20.784 0.084 ;
     RECT  20.808 0.016 20.88 0.084 ;
     RECT  20.904 0.016 20.976 0.084 ;
     RECT  21 0.016 21.072 0.084 ;
     RECT  21.096 0.016 21.168 0.084 ;
     RECT  21.192 0.016 21.264 0.084 ;
     RECT  21.288 0.016 21.36 0.084 ;
     RECT  21.384 0.016 21.456 0.084 ;
     RECT  21.48 0.016 21.552 0.084 ;
     RECT  21.576 0.016 21.648 0.084 ;
     RECT  21.672 0.016 21.744 0.084 ;
     RECT  21.768 0.016 21.84 0.084 ;
     RECT  21.864 0.016 21.936 0.084 ;
     RECT  21.96 0.016 22.032 0.084 ;
     RECT  22.056 0.016 22.128 0.084 ;
     RECT  22.152 0.016 22.224 0.084 ;
     RECT  22.248 0.016 22.32 0.084 ;
     RECT  22.344 0.016 22.416 0.084 ;
     RECT  22.44 0.016 22.512 0.084 ;
     RECT  22.536 0.016 22.608 0.084 ;
     RECT  22.632 0.016 22.704 0.084 ;
     RECT  22.728 0.016 22.8 0.084 ;
     RECT  22.824 0.016 22.896 0.084 ;
     RECT  16.08 0.084 22.92 0.131 ;
     RECT  16.176 0.131 22.92 0.419 ;
     RECT  13.104 0.131 13.32 0.611 ;
     RECT  16.176 0.419 22.728 1.139 ;
     RECT  20.112 1.139 22.728 1.763 ;
     RECT  13.2 0.611 13.32 1.765 ;
     RECT  16.176 1.139 19.08 1.955 ;
     RECT  2.4 2.137 2.52 2.151 ;
     RECT  7.8 2.137 7.92 2.151 ;
     RECT  13.104 1.765 13.32 2.151 ;
     RECT  24 2.137 24.12 2.151 ;
     RECT  29.4 2.137 29.52 2.151 ;
     RECT  34.8 2.137 34.92 2.151 ;
     RECT  40.2 2.137 40.32 2.151 ;
     RECT  17.52 1.955 19.08 2.245 ;
     RECT  20.112 1.763 21.864 2.245 ;
     RECT  13.104 2.151 13.512 2.339 ;
     RECT  17.52 2.245 21.864 4.019 ;
     RECT  13.2 2.339 13.512 4.501 ;
     RECT  17.52 4.019 18.912 4.595 ;
     RECT  5.136 4.501 5.16 5.459 ;
     RECT  19.92 4.019 21.864 5.461 ;
     RECT  7.8 2.151 8.112 6.037 ;
     RECT  9.216 4.885 9.24 6.037 ;
     RECT  16.176 1.955 16.2 6.181 ;
     RECT  17.76 4.595 18.912 6.181 ;
     RECT  2.4 2.151 2.712 6.229 ;
     RECT  7.8 6.037 9.24 6.229 ;
     RECT  6.288 6.085 6.312 6.373 ;
     RECT  7.68 6.229 9.24 6.373 ;
     RECT  4.608 6.229 4.632 6.613 ;
     RECT  6.288 6.373 9.24 6.613 ;
     RECT  16.176 6.181 18.912 6.805 ;
     RECT  19.92 5.461 22.536 6.805 ;
     RECT  25.632 5.605 25.656 6.851 ;
     RECT  15.936 6.805 22.536 6.899 ;
     RECT  4.608 6.613 9.24 7.189 ;
     RECT  0.144 7.141 0.168 7.331 ;
     RECT  4.608 7.189 10.056 7.381 ;
     RECT  13.104 4.501 13.512 7.475 ;
     RECT  22.512 6.899 22.536 7.475 ;
     RECT  11.472 7.669 11.496 7.957 ;
     RECT  13.2 7.475 13.512 7.957 ;
     RECT  4.512 7.381 10.056 8.435 ;
     RECT  13.2 7.957 13.608 8.437 ;
     RECT  24 2.151 24.312 8.485 ;
     RECT  24 8.485 24.408 8.677 ;
     RECT  15.936 6.899 21.096 8.963 ;
     RECT  2.4 6.229 2.808 9.061 ;
     RECT  4.512 8.435 5.448 9.061 ;
     RECT  6.432 8.435 10.056 9.061 ;
     RECT  11.424 7.957 11.496 9.061 ;
     RECT  13.2 8.437 14.28 9.301 ;
     RECT  2.4 9.061 5.448 9.539 ;
     RECT  6.432 9.061 11.496 9.589 ;
     RECT  4.944 9.539 5.448 9.637 ;
     RECT  6.432 9.589 11.544 9.637 ;
     RECT  2.4 9.539 3.96 9.731 ;
     RECT  13.2 9.301 14.808 9.829 ;
     RECT  0.144 9.397 0.168 10.163 ;
     RECT  23.04 8.677 24.408 10.165 ;
     RECT  4.944 9.637 11.544 10.211 ;
     RECT  13.2 9.829 15.192 10.405 ;
     RECT  27.456 6.757 27.48 10.451 ;
     RECT  23.04 10.165 25.224 10.645 ;
     RECT  3.936 9.731 3.96 10.741 ;
     RECT  4.944 10.211 10.68 10.741 ;
     RECT  2.4 9.731 2.808 10.789 ;
     RECT  3.936 10.741 10.68 10.789 ;
     RECT  22.512 10.645 25.224 11.029 ;
     RECT  13.056 10.405 15.192 11.171 ;
     RECT  2.4 10.789 10.68 11.315 ;
     RECT  16.176 8.963 21.096 11.941 ;
     RECT  22.08 11.029 25.224 11.941 ;
     RECT  2.4 11.315 10.056 12.035 ;
     RECT  2.4 12.035 2.808 12.083 ;
     RECT  13.2 11.171 15.192 12.227 ;
     RECT  16.176 11.941 25.224 12.277 ;
     RECT  16.176 12.277 25.992 12.517 ;
     RECT  27.36 11.221 27.384 12.517 ;
     RECT  16.176 12.517 27.384 13.043 ;
     RECT  2.4 12.083 2.712 13.045 ;
     RECT  13.2 12.227 14.952 13.237 ;
     RECT  2.4 13.045 2.856 13.285 ;
     RECT  16.176 13.043 25.992 13.571 ;
     RECT  13.2 13.237 15 13.621 ;
     RECT  3.936 12.035 10.056 13.715 ;
     RECT  4.992 13.715 10.056 13.717 ;
     RECT  11.088 12.997 11.112 13.717 ;
     RECT  4.992 13.717 11.112 13.909 ;
     RECT  4.992 13.909 12.024 14.101 ;
     RECT  13.008 13.621 15 14.101 ;
     RECT  4.992 14.101 15 14.243 ;
     RECT  16.176 13.571 24.936 14.387 ;
     RECT  0.384 14.053 0.408 14.389 ;
     RECT  2.4 13.285 2.904 14.485 ;
     RECT  2.304 14.485 2.904 14.533 ;
     RECT  3.936 13.715 3.96 14.533 ;
     RECT  25.968 13.571 25.992 14.629 ;
     RECT  27.36 13.043 27.384 14.629 ;
     RECT  2.304 14.533 3.96 14.675 ;
     RECT  16.176 14.387 22.2 14.675 ;
     RECT  2.4 14.675 3.96 14.773 ;
     RECT  4.992 14.243 14.952 14.773 ;
     RECT  0.144 14.389 0.408 14.917 ;
     RECT  2.4 14.773 14.952 15.059 ;
     RECT  25.968 14.629 27.384 15.349 ;
     RECT  0.144 14.917 0.456 15.395 ;
     RECT  0.24 15.395 0.456 15.443 ;
     RECT  16.176 14.675 22.056 15.443 ;
     RECT  2.4 15.059 11.832 15.587 ;
     RECT  23.184 14.387 24.936 15.637 ;
     RECT  0.432 15.443 0.456 15.923 ;
     RECT  3.744 15.587 11.832 16.067 ;
     RECT  22.8 15.637 24.936 16.549 ;
     RECT  25.968 15.349 27.432 16.549 ;
     RECT  22.8 16.549 27.432 16.595 ;
     RECT  3.792 16.067 11.832 16.835 ;
     RECT  22.8 16.595 26.952 16.835 ;
     RECT  12.816 15.059 14.952 16.885 ;
     RECT  16.176 15.443 21.192 16.885 ;
     RECT  3.792 16.835 4.488 17.123 ;
     RECT  5.472 16.835 11.832 17.171 ;
     RECT  3.792 17.123 3.816 17.219 ;
     RECT  5.568 17.171 11.832 17.219 ;
     RECT  29.4 2.151 29.712 17.317 ;
     RECT  25.68 16.835 26.952 17.459 ;
     RECT  28.848 17.317 29.712 17.459 ;
     RECT  22.8 16.835 24.6 17.699 ;
     RECT  12.816 16.885 21.192 18.035 ;
     RECT  13.104 18.035 21.192 18.037 ;
     RECT  13.104 18.037 21.816 18.083 ;
     RECT  13.2 18.083 21.816 18.275 ;
     RECT  29.088 17.459 29.712 18.275 ;
     RECT  6.336 17.219 11.832 18.467 ;
     RECT  14.64 18.275 21.816 18.755 ;
     RECT  6.336 18.467 10.056 18.757 ;
     RECT  22.8 17.699 22.92 18.757 ;
     RECT  24 17.699 24.6 18.757 ;
     RECT  14.64 18.755 16.296 19.235 ;
     RECT  22.8 18.757 24.6 19.235 ;
     RECT  29.4 18.275 29.712 19.333 ;
     RECT  22.8 19.235 24.504 19.427 ;
     RECT  17.664 18.755 21.816 19.525 ;
     RECT  24 19.427 24.504 19.619 ;
     RECT  0.144 16.693 0.168 19.859 ;
     RECT  25.68 17.459 25.992 19.907 ;
     RECT  17.664 19.525 22.776 20.003 ;
     RECT  14.928 19.235 16.296 20.245 ;
     RECT  13.2 18.275 13.608 20.485 ;
     RECT  4.704 18.805 4.728 20.579 ;
     RECT  6.192 18.757 10.056 20.579 ;
     RECT  14.928 20.245 16.488 20.627 ;
     RECT  25.68 19.907 25.704 20.627 ;
     RECT  29.088 19.333 29.712 21.155 ;
     RECT  0.144 21.205 0.168 21.491 ;
     RECT  17.664 20.003 21.816 21.635 ;
     RECT  13.2 20.485 13.656 22.165 ;
     RECT  6.192 20.579 6.552 22.261 ;
     RECT  29.4 21.155 29.712 22.453 ;
     RECT  12.672 22.165 13.656 22.549 ;
     RECT  12.48 22.549 13.656 22.787 ;
     RECT  14.928 20.627 16.2 22.835 ;
     RECT  14.928 22.835 15.384 22.883 ;
     RECT  17.664 21.635 21.096 23.363 ;
     RECT  29.232 22.453 29.712 23.411 ;
     RECT  6.144 22.261 6.552 23.603 ;
     RECT  7.8 20.579 10.056 23.893 ;
     RECT  17.664 23.363 18.912 23.893 ;
     RECT  30.96 14.101 30.984 24.373 ;
     RECT  6.144 23.603 6.312 24.469 ;
     RECT  29.4 23.411 29.712 24.469 ;
     RECT  4.56 23.797 4.584 24.659 ;
     RECT  19.92 23.363 21.096 24.659 ;
     RECT  2.4 15.587 2.712 24.901 ;
     RECT  5.76 24.469 6.312 24.949 ;
     RECT  2.4 24.901 2.808 25.045 ;
     RECT  12.48 22.787 13.512 25.093 ;
     RECT  5.664 24.949 6.312 25.139 ;
     RECT  12.48 25.093 13.608 25.235 ;
     RECT  19.92 24.659 20.424 25.715 ;
     RECT  17.616 23.893 18.912 25.859 ;
     RECT  17.76 25.859 18.912 26.051 ;
     RECT  14.928 22.883 14.952 26.053 ;
     RECT  0.144 26.053 0.168 26.243 ;
     RECT  5.664 25.139 6.216 26.245 ;
     RECT  3.888 26.245 3.912 26.437 ;
     RECT  5.568 26.245 6.216 26.437 ;
     RECT  0.192 26.485 0.216 26.675 ;
     RECT  21.984 25.189 22.008 26.773 ;
     RECT  7.8 23.893 10.44 26.819 ;
     RECT  18.288 26.051 18.912 26.819 ;
     RECT  21.984 26.773 22.968 26.819 ;
     RECT  32.736 25.573 32.76 26.819 ;
     RECT  12.48 25.235 13.512 27.203 ;
     RECT  3.888 26.437 6.216 27.301 ;
     RECT  7.8 26.819 9.672 27.301 ;
     RECT  2.4 25.045 2.856 27.395 ;
     RECT  28.944 24.469 29.712 27.589 ;
     RECT  30.72 24.373 30.984 27.589 ;
     RECT  22.512 26.819 22.968 27.635 ;
     RECT  24 19.619 24.312 27.781 ;
     RECT  28.944 27.589 30.984 27.827 ;
     RECT  17.04 27.301 17.064 27.877 ;
     RECT  32.784 27.301 32.808 28.211 ;
     RECT  0.192 28.117 0.216 28.307 ;
     RECT  30.72 27.827 30.984 28.405 ;
     RECT  22.512 27.635 22.536 28.451 ;
     RECT  28.944 27.827 29.712 28.451 ;
     RECT  16.992 27.877 17.064 28.453 ;
     RECT  16.56 28.453 17.064 28.499 ;
     RECT  3.888 27.301 9.672 28.547 ;
     RECT  0.144 28.741 0.168 29.027 ;
     RECT  3.888 28.547 9.096 29.219 ;
     RECT  2.4 27.395 2.712 29.461 ;
     RECT  3.888 29.219 6.264 29.461 ;
     RECT  0.192 29.269 0.216 29.555 ;
     RECT  14.928 26.053 15.192 29.605 ;
     RECT  16.56 28.499 17.016 29.605 ;
     RECT  30.72 28.405 31.896 29.653 ;
     RECT  14.928 29.605 17.016 29.699 ;
     RECT  16.992 29.699 17.016 29.747 ;
     RECT  12 27.829 12.024 29.795 ;
     RECT  19.92 25.715 19.944 29.891 ;
     RECT  2.4 29.461 6.264 30.181 ;
     RECT  7.8 29.219 9.096 30.181 ;
     RECT  29.4 28.451 29.712 30.181 ;
     RECT  14.928 29.699 15.672 30.565 ;
     RECT  2.4 30.181 9.096 30.611 ;
     RECT  30.72 29.653 32.664 30.611 ;
     RECT  22.512 29.605 22.536 31.139 ;
     RECT  34.8 2.151 35.112 31.189 ;
     RECT  3.696 30.611 9.096 31.379 ;
     RECT  3.696 31.379 6.12 31.427 ;
     RECT  34.8 31.189 35.448 31.427 ;
     RECT  38.592 31.285 38.808 31.427 ;
     RECT  38.784 31.427 38.808 31.475 ;
     RECT  7.8 31.379 9.096 31.523 ;
     RECT  24 27.781 24.504 31.525 ;
     RECT  3.696 31.427 6.024 31.619 ;
     RECT  30.72 30.611 31.896 31.715 ;
     RECT  5.328 31.619 6.024 31.955 ;
     RECT  3.696 31.619 4.248 32.003 ;
     RECT  4.224 32.003 4.248 32.051 ;
     RECT  14.544 30.565 15.672 32.197 ;
     RECT  14.544 32.197 15.96 32.243 ;
     RECT  33.648 31.813 33.672 33.013 ;
     RECT  34.8 31.427 35.112 33.013 ;
     RECT  33.648 33.013 35.112 33.683 ;
     RECT  34.56 33.683 35.112 33.781 ;
     RECT  38.784 33.733 38.808 34.163 ;
     RECT  40.2 2.151 40.512 34.357 ;
     RECT  32.592 32.965 32.616 34.595 ;
     RECT  14.544 32.243 14.952 34.835 ;
     RECT  39.984 34.357 40.512 34.835 ;
     RECT  28.656 30.181 29.712 35.845 ;
     RECT  30.72 31.715 30.984 35.845 ;
     RECT  28.656 35.845 30.984 36.277 ;
     RECT  34.56 33.781 35.208 36.467 ;
     RECT  13.2 27.203 13.512 36.757 ;
     RECT  14.544 34.835 14.568 36.757 ;
     RECT  28.656 36.277 31.272 36.899 ;
     RECT  32.448 35.317 32.472 36.901 ;
     RECT  28.656 36.899 30.984 36.947 ;
     RECT  32.448 36.901 32.808 36.949 ;
     RECT  32.4 36.949 32.808 36.997 ;
     RECT  34.8 36.467 35.208 37.043 ;
     RECT  32.4 36.997 32.952 37.091 ;
     RECT  10.224 35.317 10.248 37.139 ;
     RECT  36.96 37.045 36.984 37.187 ;
     RECT  40.2 34.835 40.512 37.573 ;
     RECT  34.8 37.043 35.112 37.621 ;
     RECT  13.2 36.757 14.568 37.907 ;
     RECT  11.952 36.997 11.976 38.005 ;
     RECT  28.992 36.947 30.984 38.005 ;
     RECT  11.76 38.005 11.976 38.149 ;
     RECT  13.2 37.907 14.232 38.149 ;
     RECT  32.928 37.091 32.952 38.243 ;
     RECT  15.936 32.243 15.96 38.675 ;
     RECT  34.176 37.621 35.112 38.675 ;
     RECT  27.984 38.149 28.008 38.677 ;
     RECT  39.408 37.573 40.512 38.819 ;
     RECT  27.696 38.677 28.008 38.917 ;
     RECT  28.992 38.005 31.56 38.917 ;
     RECT  38.88 38.821 38.904 39.155 ;
     RECT  27.696 38.917 31.56 39.203 ;
     RECT  7.8 31.523 8.112 39.253 ;
     RECT  24 31.525 25.08 39.395 ;
     RECT  7.8 39.253 8.232 39.829 ;
     RECT  11.76 38.149 14.232 39.923 ;
     RECT  31.536 39.203 31.56 39.923 ;
     RECT  26.448 40.165 26.472 40.405 ;
     RECT  7.8 39.829 9.096 40.453 ;
     RECT  11.76 39.923 13.992 40.453 ;
     RECT  27.696 39.203 30.408 40.453 ;
     RECT  15.36 39.733 15.384 40.499 ;
     RECT  27.504 40.453 30.408 40.499 ;
     RECT  25.68 40.405 26.472 40.501 ;
     RECT  27.504 40.499 30.12 40.501 ;
     RECT  25.68 40.501 30.12 40.597 ;
     RECT  40.08 38.819 40.512 40.643 ;
     RECT  43.008 40.597 43.032 40.883 ;
     RECT  24 39.395 24.312 41.029 ;
     RECT  25.584 40.597 30.12 41.029 ;
     RECT  2.4 30.611 2.712 41.049 ;
     RECT  18.6 26.819 18.912 41.049 ;
     RECT  34.8 38.675 35.112 41.049 ;
     RECT  40.2 40.643 40.512 41.049 ;
     RECT  2.4 41.049 2.52 41.063 ;
     RECT  7.8 40.453 13.992 41.063 ;
     RECT  18.6 41.049 18.72 41.063 ;
     RECT  24 41.029 30.12 41.063 ;
     RECT  34.8 41.049 34.92 41.063 ;
     RECT  40.2 41.049 40.32 41.063 ;
     RECT  7.92 41.063 13.992 43.116 ;
     RECT  7.944 43.116 8.016 43.152 ;
     RECT  8.04 43.116 8.112 43.152 ;
     RECT  8.136 43.116 8.208 43.152 ;
     RECT  8.232 43.116 8.304 43.152 ;
     RECT  8.328 43.116 8.4 43.152 ;
     RECT  8.424 43.116 8.496 43.152 ;
     RECT  8.52 43.116 8.592 43.152 ;
     RECT  8.616 43.116 8.688 43.152 ;
     RECT  8.712 43.116 8.784 43.152 ;
     RECT  8.808 43.116 8.88 43.152 ;
     RECT  8.904 43.116 8.976 43.152 ;
     RECT  9 43.116 9.072 43.152 ;
     RECT  9.096 43.116 9.168 43.152 ;
     RECT  9.192 43.116 9.264 43.152 ;
     RECT  9.288 43.116 9.36 43.152 ;
     RECT  9.384 43.116 9.456 43.152 ;
     RECT  9.48 43.116 9.552 43.152 ;
     RECT  9.576 43.116 9.648 43.152 ;
     RECT  9.672 43.116 9.744 43.152 ;
     RECT  9.768 43.116 9.84 43.152 ;
     RECT  9.864 43.116 9.936 43.152 ;
     RECT  9.96 43.116 10.032 43.152 ;
     RECT  10.056 43.116 10.128 43.152 ;
     RECT  10.152 43.116 10.224 43.152 ;
     RECT  10.248 43.116 10.32 43.152 ;
     RECT  10.344 43.116 10.416 43.152 ;
     RECT  10.44 43.116 10.512 43.152 ;
     RECT  10.536 43.116 10.608 43.152 ;
     RECT  10.632 43.116 10.704 43.152 ;
     RECT  10.728 43.116 10.8 43.152 ;
     RECT  10.824 43.116 10.896 43.152 ;
     RECT  10.92 43.116 11.376 43.152 ;
     RECT  11.4 43.116 11.472 43.152 ;
     RECT  11.496 43.116 11.568 43.152 ;
     RECT  11.592 43.116 11.664 43.152 ;
     RECT  11.688 43.116 11.76 43.152 ;
     RECT  11.784 43.116 11.856 43.152 ;
     RECT  11.88 43.116 11.952 43.152 ;
     RECT  11.976 43.116 12.048 43.152 ;
     RECT  12.072 43.116 12.144 43.152 ;
     RECT  12.168 43.116 12.24 43.152 ;
     RECT  12.264 43.116 12.336 43.152 ;
     RECT  12.36 43.116 12.432 43.152 ;
     RECT  12.456 43.116 12.528 43.152 ;
     RECT  12.552 43.116 12.624 43.152 ;
     RECT  12.648 43.116 12.72 43.152 ;
     RECT  12.744 43.116 12.816 43.152 ;
     RECT  12.84 43.116 12.912 43.152 ;
     RECT  12.936 43.116 13.008 43.152 ;
     RECT  13.032 43.116 13.104 43.152 ;
     RECT  13.128 43.116 13.2 43.152 ;
     RECT  13.224 43.116 13.296 43.152 ;
     RECT  13.32 43.116 13.392 43.152 ;
     RECT  13.416 43.116 13.488 43.152 ;
     RECT  13.512 43.116 13.584 43.152 ;
     RECT  13.608 43.116 13.68 43.152 ;
     RECT  13.704 43.116 13.776 43.152 ;
     RECT  13.8 43.116 13.872 43.152 ;
     RECT  13.896 43.116 13.968 43.152 ;
     RECT  24.048 41.063 30.12 43.116 ;
     RECT  24.072 43.116 24.144 43.152 ;
     RECT  24.168 43.116 24.24 43.152 ;
     RECT  24.264 43.116 24.336 43.152 ;
     RECT  24.36 43.116 24.432 43.152 ;
     RECT  24.456 43.116 24.528 43.152 ;
     RECT  24.552 43.116 24.624 43.152 ;
     RECT  24.648 43.116 24.72 43.152 ;
     RECT  24.744 43.116 24.816 43.152 ;
     RECT  24.84 43.116 24.912 43.152 ;
     RECT  24.936 43.116 25.008 43.152 ;
     RECT  25.032 43.116 25.104 43.152 ;
     RECT  25.128 43.116 25.2 43.152 ;
     RECT  25.224 43.116 25.296 43.152 ;
     RECT  25.32 43.116 25.392 43.152 ;
     RECT  25.416 43.116 25.488 43.152 ;
     RECT  25.512 43.116 25.584 43.152 ;
     RECT  25.608 43.116 25.68 43.152 ;
     RECT  25.704 43.116 25.776 43.152 ;
     RECT  25.8 43.116 25.872 43.152 ;
     RECT  25.896 43.116 25.968 43.152 ;
     RECT  25.992 43.116 26.064 43.152 ;
     RECT  26.088 43.116 26.16 43.152 ;
     RECT  26.184 43.116 26.256 43.152 ;
     RECT  26.28 43.116 26.352 43.152 ;
     RECT  26.376 43.116 26.448 43.152 ;
     RECT  26.472 43.116 26.544 43.152 ;
     RECT  26.568 43.116 26.64 43.152 ;
     RECT  26.664 43.116 26.736 43.152 ;
     RECT  26.76 43.116 26.832 43.152 ;
     RECT  26.856 43.116 26.928 43.152 ;
     RECT  26.952 43.116 27.024 43.152 ;
     RECT  27.048 43.116 27.12 43.152 ;
     RECT  27.144 43.116 27.216 43.152 ;
     RECT  27.24 43.116 27.312 43.152 ;
     RECT  27.336 43.116 27.408 43.152 ;
     RECT  27.432 43.116 27.504 43.152 ;
     RECT  27.528 43.116 27.6 43.152 ;
     RECT  27.624 43.116 27.696 43.152 ;
     RECT  27.72 43.116 27.792 43.152 ;
     RECT  27.816 43.116 27.888 43.152 ;
     RECT  27.912 43.116 27.984 43.152 ;
     RECT  28.008 43.116 28.08 43.152 ;
     RECT  28.104 43.116 28.176 43.152 ;
     RECT  28.2 43.116 28.272 43.152 ;
     RECT  28.296 43.116 28.368 43.152 ;
     RECT  28.392 43.116 28.464 43.152 ;
     RECT  28.488 43.116 28.56 43.152 ;
     RECT  28.584 43.116 28.656 43.152 ;
     RECT  28.68 43.116 28.752 43.152 ;
     RECT  28.776 43.116 28.848 43.152 ;
     RECT  28.872 43.116 28.944 43.152 ;
     RECT  28.968 43.116 29.04 43.152 ;
     RECT  29.064 43.116 29.136 43.152 ;
     RECT  29.16 43.116 29.232 43.152 ;
     RECT  29.256 43.116 29.328 43.152 ;
     RECT  29.352 43.116 29.424 43.152 ;
     RECT  29.448 43.116 29.52 43.152 ;
     RECT  29.544 43.116 29.616 43.152 ;
     RECT  29.64 43.116 29.712 43.152 ;
     RECT  29.736 43.116 29.808 43.152 ;
     RECT  29.832 43.116 29.904 43.152 ;
     RECT  29.928 43.116 30 43.152 ;
     RECT  30.024 43.116 30.096 43.152 ;
     RECT  13.104 0.611 13.2 1.765 ;
     RECT  19.08 1.139 20.112 2.245 ;
     RECT  16.2 1.955 17.52 4.595 ;
     RECT  18.912 4.019 19.92 6.805 ;
     RECT  8.112 4.885 9.216 6.037 ;
     RECT  5.136 5.459 5.16 6.085 ;
     RECT  22.536 5.461 24 7.475 ;
     RECT  24.312 5.605 25.632 6.851 ;
     RECT  5.136 6.085 6.288 6.229 ;
     RECT  6.312 6.085 7.8 6.229 ;
     RECT  4.632 6.229 6.288 6.613 ;
     RECT  6.312 6.229 7.68 6.373 ;
     RECT  21.096 6.899 22.512 7.475 ;
     RECT  23.04 7.475 24 8.677 ;
     RECT  10.056 7.669 11.472 7.957 ;
     RECT  10.056 7.957 11.424 9.061 ;
     RECT  5.448 8.435 6.432 9.637 ;
     RECT  15.936 8.963 16.176 9.301 ;
     RECT  14.808 9.301 16.176 9.829 ;
     RECT  3.96 9.539 4.944 10.741 ;
     RECT  2.808 9.731 3.936 10.789 ;
     RECT  15.192 9.829 16.176 12.227 ;
     RECT  21.096 10.645 22.512 11.029 ;
     RECT  21.096 11.029 22.08 11.941 ;
     RECT  2.808 12.035 3.936 12.083 ;
     RECT  2.712 12.083 3.936 13.045 ;
     RECT  14.952 12.227 16.176 13.237 ;
     RECT  25.992 12.277 27.36 12.517 ;
     RECT  10.056 12.997 11.088 13.717 ;
     RECT  25.992 13.043 27.36 14.629 ;
     RECT  2.856 13.045 3.936 13.285 ;
     RECT  15 13.237 16.176 14.243 ;
     RECT  2.904 13.285 3.936 14.533 ;
     RECT  24.936 13.571 25.968 16.549 ;
     RECT  3.96 13.715 4.992 14.773 ;
     RECT  12.024 13.909 13.008 14.101 ;
     RECT  29.712 14.101 30.96 24.373 ;
     RECT  14.952 14.243 16.176 16.885 ;
     RECT  22.2 14.387 23.184 14.675 ;
     RECT  22.056 14.675 23.184 15.443 ;
     RECT  11.832 15.059 12.816 18.035 ;
     RECT  0.144 15.395 0.24 15.443 ;
     RECT  0.144 15.443 0.432 15.923 ;
     RECT  22.8 15.443 23.184 15.637 ;
     RECT  2.712 15.587 3.744 16.067 ;
     RECT  0.144 15.923 0.168 16.693 ;
     RECT  2.712 16.067 3.792 17.219 ;
     RECT  4.488 16.835 5.472 17.123 ;
     RECT  24.6 16.835 25.68 19.235 ;
     RECT  22.92 17.699 24 18.757 ;
     RECT  11.832 18.035 13.104 18.083 ;
     RECT  21.816 18.037 22.8 19.427 ;
     RECT  11.832 18.083 13.2 18.467 ;
     RECT  13.608 18.275 14.64 19.235 ;
     RECT  29.088 18.275 29.4 19.333 ;
     RECT  16.296 18.755 17.664 20.245 ;
     RECT  4.728 18.805 6.192 20.579 ;
     RECT  13.608 19.235 14.928 20.485 ;
     RECT  24.504 19.235 25.68 19.619 ;
     RECT  21.816 19.427 24 19.525 ;
     RECT  22.776 19.525 24 20.003 ;
     RECT  24.312 19.619 25.68 20.627 ;
     RECT  0.144 19.859 0.168 21.205 ;
     RECT  16.488 20.245 17.664 20.627 ;
     RECT  13.656 20.485 14.928 22.787 ;
     RECT  6.552 20.579 7.8 23.603 ;
     RECT  16.2 20.627 17.664 22.835 ;
     RECT  29.232 21.155 29.4 22.453 ;
     RECT  13.512 22.787 14.928 25.093 ;
     RECT  17.616 22.835 17.664 23.893 ;
     RECT  18.912 23.363 19.92 29.891 ;
     RECT  29.232 23.411 29.4 24.469 ;
     RECT  6.312 23.603 7.8 25.139 ;
     RECT  29.712 24.373 30.72 27.589 ;
     RECT  4.584 24.469 5.76 24.659 ;
     RECT  5.664 24.659 5.76 24.949 ;
     RECT  13.608 25.093 14.928 25.235 ;
     RECT  13.512 25.235 14.928 30.565 ;
     RECT  2.856 26.245 3.888 27.395 ;
     RECT  0.192 26.675 0.216 28.117 ;
     RECT  22.968 26.773 24 27.635 ;
     RECT  12.48 27.203 13.2 27.829 ;
     RECT  2.712 27.395 3.888 29.461 ;
     RECT  22.536 27.635 24 28.451 ;
     RECT  29.712 27.827 30.72 35.845 ;
     RECT  12.024 27.829 13.2 29.795 ;
     RECT  0.192 28.307 0.216 28.741 ;
     RECT  22.512 28.451 24 29.605 ;
     RECT  15.192 28.453 16.56 29.605 ;
     RECT  0.168 28.741 0.216 29.027 ;
     RECT  0.192 29.027 0.216 29.269 ;
     RECT  6.264 29.219 7.8 30.181 ;
     RECT  22.536 29.605 24 31.139 ;
     RECT  15.672 29.699 16.992 29.747 ;
     RECT  13.512 30.565 14.544 36.757 ;
     RECT  2.712 30.611 3.696 32.003 ;
     RECT  38.808 31.285 40.2 31.475 ;
     RECT  4.248 31.619 5.328 31.955 ;
     RECT  33.672 31.813 34.8 33.013 ;
     RECT  2.712 32.003 4.224 32.051 ;
     RECT  14.952 32.243 15.936 34.835 ;
     RECT  32.616 32.965 33.648 33.683 ;
     RECT  38.808 33.733 40.2 34.163 ;
     RECT  39.984 34.163 40.2 34.357 ;
     RECT  14.568 34.835 15.936 37.907 ;
     RECT  30.984 35.317 32.448 36.277 ;
     RECT  31.272 36.277 32.448 36.899 ;
     RECT  34.56 36.467 34.8 37.621 ;
     RECT  30.984 36.899 32.448 36.949 ;
     RECT  28.656 36.947 28.992 38.149 ;
     RECT  30.984 36.949 32.4 37.091 ;
     RECT  11.976 36.997 13.2 38.149 ;
     RECT  30.984 37.091 32.928 38.005 ;
     RECT  32.952 37.621 34.176 38.243 ;
     RECT  31.56 38.005 32.928 38.243 ;
     RECT  28.008 38.149 28.992 38.917 ;
     RECT  39.408 38.819 40.08 38.821 ;
     RECT  38.904 38.821 40.08 39.155 ;
     RECT  30.408 39.203 31.536 39.923 ;
     RECT  24.312 39.395 25.08 40.165 ;
     RECT  14.232 39.733 15.36 39.923 ;
     RECT  13.992 39.923 15.36 40.499 ;
     RECT  24.312 40.165 26.448 40.405 ;
     RECT  26.472 40.165 27.696 40.453 ;
     RECT  24.312 40.405 25.68 40.597 ;
     RECT  26.472 40.453 27.504 40.501 ;
     RECT  24.312 40.597 25.584 41.029 ;
  END
END ot_qwen_tp8_pv_wide_ctl
END LIBRARY
